##
## LEF for PtnCells ;
## created by Encounter v13.10-p003_1 on Wed Aug 21 15:55:15 2013
##

VERSION 5.6 ;

BUSBITCHARS "[]" ;
DIVIDERCHAR "/" ;

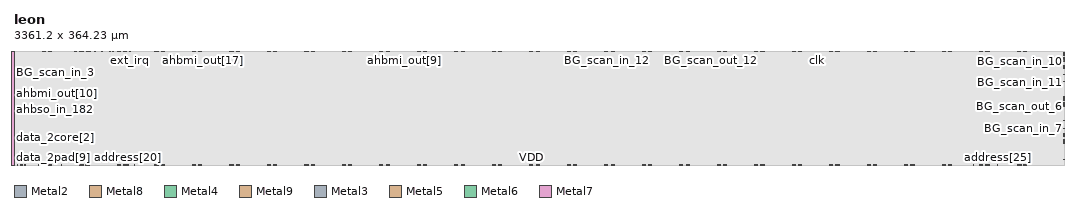
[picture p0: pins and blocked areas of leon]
MACRO leon
  CLASS BLOCK ;
  FOREIGN leon 0 0 ;
  ORIGIN 0.0000 0.0000 ;
  SIZE 3361.2000 BY 364.2300 ;
  SYMMETRY X Y R90 ;
  PIN resetn
    DIRECTION INPUT ;
    USE SIGNAL ;
    PORT
      LAYER Metal2 ;
        RECT 266.0650 363.9400 266.1350 364.2300 ;
    END
  END resetn
  PIN clk
    DIRECTION INPUT ;
    USE SIGNAL ;
    PORT
      LAYER Metal2 ;
        RECT 2571.4650 363.9400 2571.5350 364.2300 ;
    END
  END clk
  PIN clk_half
    DIRECTION INPUT ;
    USE CLOCK ;
    PORT
      LAYER Metal2 ;
        RECT 139.0650 363.9400 139.1350 364.2300 ;
    END
  END clk_half
  PIN address[27]
    DIRECTION OUTPUT ;
    USE SIGNAL ;
    PORT
      LAYER Metal2 ;
        RECT 2994.4650 0.0000 2994.5350 0.2900 ;
    END
  END address[27]
  PIN address[26]
    DIRECTION OUTPUT ;
    USE SIGNAL ;
    PORT
      LAYER Metal8 ;
        RECT 3071.6650 0.0000 3071.7350 0.2900 ;
    END
  END address[26]
  PIN address[25]
    DIRECTION OUTPUT ;
    USE SIGNAL ;
    PORT
      LAYER Metal2 ;
        RECT 3148.4650 0.0000 3148.5350 0.2900 ;
    END
  END address[25]
  PIN address[24]
    DIRECTION OUTPUT ;
    USE SIGNAL ;
    PORT
      LAYER Metal8 ;
        RECT 3225.2650 0.0000 3225.3350 0.2900 ;
    END
  END address[24]
  PIN address[23]
    DIRECTION OUTPUT ;
    USE SIGNAL ;
    PORT
      LAYER Metal2 ;
        RECT 366.0650 0.0000 366.1350 0.2900 ;
    END
  END address[23]
  PIN address[22]
    DIRECTION OUTPUT ;
    USE SIGNAL ;
    PORT
      LAYER Metal2 ;
        RECT 365.0650 0.0000 365.1350 0.2900 ;
    END
  END address[22]
  PIN address[21]
    DIRECTION OUTPUT ;
    USE SIGNAL ;
    PORT
      LAYER Metal4 ;
        RECT 365.8650 0.0000 365.9350 0.2900 ;
    END
  END address[21]
  PIN address[20]
    DIRECTION OUTPUT ;
    USE SIGNAL ;
    PORT
      LAYER Metal2 ;
        RECT 364.2650 0.0000 364.3350 0.2900 ;
    END
  END address[20]
  PIN address[19]
    DIRECTION OUTPUT ;
    USE SIGNAL ;
    PORT
      LAYER Metal9 ;
        RECT 3360.9100 19.0600 3361.2000 19.1300 ;
    END
  END address[19]
  PIN address[18]
    DIRECTION OUTPUT ;
    USE SIGNAL ;
    PORT
      LAYER Metal9 ;
        RECT 3360.9100 81.3800 3361.2000 81.4500 ;
    END
  END address[18]
  PIN address[17]
    DIRECTION OUTPUT ;
    USE SIGNAL ;
    PORT
      LAYER Metal9 ;
        RECT 3360.9100 143.7000 3361.2000 143.7700 ;
    END
  END address[17]
  PIN address[16]
    DIRECTION OUTPUT ;
    USE SIGNAL ;
    PORT
      LAYER Metal9 ;
        RECT 3360.9100 206.0200 3361.2000 206.0900 ;
    END
  END address[16]
  PIN address[15]
    DIRECTION OUTPUT ;
    USE SIGNAL ;
    PORT
      LAYER Metal9 ;
        RECT 3360.9100 268.3400 3361.2000 268.4100 ;
    END
  END address[15]
  PIN address[14]
    DIRECTION OUTPUT ;
    USE SIGNAL ;
    PORT
      LAYER Metal3 ;
        RECT 3360.9100 330.6600 3361.2000 330.7300 ;
    END
  END address[14]
  PIN address[13]
    DIRECTION OUTPUT ;
    USE SIGNAL ;
    PORT
      LAYER Metal2 ;
        RECT 338.8650 363.9400 338.9350 364.2300 ;
    END
  END address[13]
  PIN address[12]
    DIRECTION OUTPUT ;
    USE SIGNAL ;
    PORT
      LAYER Metal2 ;
        RECT 346.0650 363.9400 346.1350 364.2300 ;
    END
  END address[12]
  PIN address[11]
    DIRECTION OUTPUT ;
    USE SIGNAL ;
    PORT
      LAYER Metal2 ;
        RECT 3332.6650 363.9400 3332.7350 364.2300 ;
    END
  END address[11]
  PIN address[10]
    DIRECTION OUTPUT ;
    USE SIGNAL ;
    PORT
      LAYER Metal4 ;
        RECT 345.8650 363.9400 345.9350 364.2300 ;
    END
  END address[10]
  PIN address[9]
    DIRECTION OUTPUT ;
    USE SIGNAL ;
    PORT
      LAYER Metal2 ;
        RECT 348.0650 363.9400 348.1350 364.2300 ;
    END
  END address[9]
  PIN address[8]
    DIRECTION OUTPUT ;
    USE SIGNAL ;
    PORT
      LAYER Metal9 ;
        RECT 3360.9100 351.5600 3361.2000 351.6300 ;
    END
  END address[8]
  PIN address[7]
    DIRECTION OUTPUT ;
    USE SIGNAL ;
    PORT
      LAYER Metal3 ;
        RECT 3360.9100 351.9400 3361.2000 352.0100 ;
    END
  END address[7]
  PIN address[6]
    DIRECTION OUTPUT ;
    USE SIGNAL ;
    PORT
      LAYER Metal9 ;
        RECT 3360.9100 353.8400 3361.2000 353.9100 ;
    END
  END address[6]
  PIN address[5]
    DIRECTION OUTPUT ;
    USE SIGNAL ;
    PORT
      LAYER Metal2 ;
        RECT 341.0650 363.9400 341.1350 364.2300 ;
    END
  END address[5]
  PIN address[4]
    DIRECTION OUTPUT ;
    USE SIGNAL ;
    PORT
      LAYER Metal4 ;
        RECT 343.0650 363.9400 343.1350 364.2300 ;
    END
  END address[4]
  PIN address[3]
    DIRECTION OUTPUT ;
    USE SIGNAL ;
    PORT
      LAYER Metal9 ;
        RECT 3360.9100 357.2600 3361.2000 357.3300 ;
    END
  END address[3]
  PIN address[2]
    DIRECTION OUTPUT ;
    USE SIGNAL ;
    PORT
      LAYER Metal3 ;
        RECT 3360.9100 353.4600 3361.2000 353.5300 ;
    END
  END address[2]
  PIN address[1]
    DIRECTION OUTPUT ;
    USE SIGNAL ;
    PORT
      LAYER Metal2 ;
        RECT 328.0650 363.9400 328.1350 364.2300 ;
    END
  END address[1]
  PIN address[0]
    DIRECTION OUTPUT ;
    USE SIGNAL ;
    PORT
      LAYER Metal2 ;
        RECT 327.0650 363.9400 327.1350 364.2300 ;
    END
  END address[0]
  PIN data_2core[31]
    DIRECTION INPUT ;
    USE SIGNAL ;
    PORT
      LAYER Metal9 ;
        RECT 0.0000 261.8800 0.2900 261.9500 ;
    END
  END data_2core[31]
  PIN data_2core[30]
    DIRECTION INPUT ;
    USE SIGNAL ;
    PORT
      LAYER Metal3 ;
        RECT 0.0000 239.8400 0.2900 239.9100 ;
    END
  END data_2core[30]
  PIN data_2core[29]
    DIRECTION INPUT ;
    USE SIGNAL ;
    PORT
      LAYER Metal3 ;
        RECT 0.0000 224.6400 0.2900 224.7100 ;
    END
  END data_2core[29]
  PIN data_2core[28]
    DIRECTION INPUT ;
    USE SIGNAL ;
    PORT
      LAYER Metal3 ;
        RECT 0.0000 223.3100 0.2900 223.3800 ;
    END
  END data_2core[28]
  PIN data_2core[27]
    DIRECTION INPUT ;
    USE SIGNAL ;
    PORT
      LAYER Metal9 ;
        RECT 0.0000 221.2200 0.2900 221.2900 ;
    END
  END data_2core[27]
  PIN data_2core[26]
    DIRECTION INPUT ;
    USE SIGNAL ;
    PORT
      LAYER Metal3 ;
        RECT 0.0000 221.0300 0.2900 221.1000 ;
    END
  END data_2core[26]
  PIN data_2core[25]
    DIRECTION INPUT ;
    USE SIGNAL ;
    PORT
      LAYER Metal3 ;
        RECT 0.0000 238.1300 0.2900 238.2000 ;
    END
  END data_2core[25]
  PIN data_2core[24]
    DIRECTION INPUT ;
    USE SIGNAL ;
    PORT
      LAYER Metal9 ;
        RECT 0.0000 242.8800 0.2900 242.9500 ;
    END
  END data_2core[24]
  PIN data_2core[23]
    DIRECTION INPUT ;
    USE SIGNAL ;
    PORT
      LAYER Metal9 ;
        RECT 0.0000 241.7400 0.2900 241.8100 ;
    END
  END data_2core[23]
  PIN data_2core[22]
    DIRECTION INPUT ;
    USE SIGNAL ;
    PORT
      LAYER Metal3 ;
        RECT 0.0000 242.1200 0.2900 242.1900 ;
    END
  END data_2core[22]
  PIN data_2core[21]
    DIRECTION INPUT ;
    USE SIGNAL ;
    PORT
      LAYER Metal3 ;
        RECT 0.0000 244.9700 0.2900 245.0400 ;
    END
  END data_2core[21]
  PIN data_2core[20]
    DIRECTION INPUT ;
    USE SIGNAL ;
    PORT
      LAYER Metal9 ;
        RECT 0.0000 252.0000 0.2900 252.0700 ;
    END
  END data_2core[20]
  PIN data_2core[19]
    DIRECTION INPUT ;
    USE SIGNAL ;
    PORT
      LAYER Metal3 ;
        RECT 0.0000 255.2300 0.2900 255.3000 ;
    END
  END data_2core[19]
  PIN data_2core[18]
    DIRECTION INPUT ;
    USE SIGNAL ;
    PORT
      LAYER Metal9 ;
        RECT 0.0000 250.8600 0.2900 250.9300 ;
    END
  END data_2core[18]
  PIN data_2core[17]
    DIRECTION INPUT ;
    USE SIGNAL ;
    PORT
      LAYER Metal3 ;
        RECT 0.0000 241.7400 0.2900 241.8100 ;
    END
  END data_2core[17]
  PIN data_2core[16]
    DIRECTION INPUT ;
    USE SIGNAL ;
    PORT
      LAYER Metal5 ;
        RECT 0.0000 241.5500 0.2900 241.6200 ;
    END
  END data_2core[16]
  PIN data_2core[15]
    DIRECTION INPUT ;
    USE SIGNAL ;
    PORT
      LAYER Metal2 ;
        RECT 27.2650 0.0000 27.3350 0.2900 ;
    END
  END data_2core[15]
  PIN data_2core[14]
    DIRECTION INPUT ;
    USE SIGNAL ;
    PORT
      LAYER Metal9 ;
        RECT 0.0000 224.6400 0.2900 224.7100 ;
    END
  END data_2core[14]
  PIN data_2core[13]
    DIRECTION INPUT ;
    USE SIGNAL ;
    PORT
      LAYER Metal9 ;
        RECT 0.0000 223.1200 0.2900 223.1900 ;
    END
  END data_2core[13]
  PIN data_2core[12]
    DIRECTION INPUT ;
    USE SIGNAL ;
    PORT
      LAYER Metal2 ;
        RECT 21.2650 0.0000 21.3350 0.2900 ;
    END
  END data_2core[12]
  PIN data_2core[11]
    DIRECTION INPUT ;
    USE SIGNAL ;
    PORT
      LAYER Metal9 ;
        RECT 0.0000 234.9000 0.2900 234.9700 ;
    END
  END data_2core[11]
  PIN data_2core[10]
    DIRECTION INPUT ;
    USE SIGNAL ;
    PORT
      LAYER Metal9 ;
        RECT 0.0000 237.1800 0.2900 237.2500 ;
    END
  END data_2core[10]
  PIN data_2core[9]
    DIRECTION INPUT ;
    USE SIGNAL ;
    PORT
      LAYER Metal2 ;
        RECT 36.2650 0.0000 36.3350 0.2900 ;
    END
  END data_2core[9]
  PIN data_2core[8]
    DIRECTION INPUT ;
    USE SIGNAL ;
    PORT
      LAYER Metal9 ;
        RECT 0.0000 255.4200 0.2900 255.4900 ;
    END
  END data_2core[8]
  PIN data_2core[7]
    DIRECTION INPUT ;
    USE SIGNAL ;
    PORT
      LAYER Metal9 ;
        RECT 0.0000 304.8200 0.2900 304.8900 ;
    END
  END data_2core[7]
  PIN data_2core[6]
    DIRECTION INPUT ;
    USE SIGNAL ;
    PORT
      LAYER Metal9 ;
        RECT 0.0000 307.8600 0.2900 307.9300 ;
    END
  END data_2core[6]
  PIN data_2core[5]
    DIRECTION INPUT ;
    USE SIGNAL ;
    PORT
      LAYER Metal2 ;
        RECT 49.4650 363.9400 49.5350 364.2300 ;
    END
  END data_2core[5]
  PIN data_2core[4]
    DIRECTION INPUT ;
    USE SIGNAL ;
    PORT
      LAYER Metal3 ;
        RECT 0.0000 315.8400 0.2900 315.9100 ;
    END
  END data_2core[4]
  PIN data_2core[3]
    DIRECTION INPUT ;
    USE SIGNAL ;
    PORT
      LAYER Metal9 ;
        RECT 0.0000 306.3400 0.2900 306.4100 ;
    END
  END data_2core[3]
  PIN data_2core[2]
    DIRECTION INPUT ;
    USE SIGNAL ;
    PORT
      LAYER Metal9 ;
        RECT 0.0000 86.7000 0.2900 86.7700 ;
    END
  END data_2core[2]
  PIN data_2core[1]
    DIRECTION INPUT ;
    USE SIGNAL ;
    PORT
      LAYER Metal9 ;
        RECT 0.0000 55.9200 0.2900 55.9900 ;
    END
  END data_2core[1]
  PIN data_2core[0]
    DIRECTION INPUT ;
    USE SIGNAL ;
    PORT
      LAYER Metal9 ;
        RECT 0.0000 39.9600 0.2900 40.0300 ;
    END
  END data_2core[0]
  PIN data_2pad[31]
    DIRECTION OUTPUT ;
    USE SIGNAL ;
    PORT
      LAYER Metal9 ;
        RECT 0.0000 257.3200 0.2900 257.3900 ;
    END
  END data_2pad[31]
  PIN data_2pad[30]
    DIRECTION OUTPUT ;
    USE SIGNAL ;
    PORT
      LAYER Metal3 ;
        RECT 0.0000 237.1800 0.2900 237.2500 ;
    END
  END data_2pad[30]
  PIN data_2pad[29]
    DIRECTION OUTPUT ;
    USE SIGNAL ;
    PORT
      LAYER Metal5 ;
        RECT 0.0000 228.4400 0.2900 228.5100 ;
    END
  END data_2pad[29]
  PIN data_2pad[28]
    DIRECTION OUTPUT ;
    USE SIGNAL ;
    PORT
      LAYER Metal3 ;
        RECT 0.0000 231.2900 0.2900 231.3600 ;
    END
  END data_2pad[28]
  PIN data_2pad[27]
    DIRECTION OUTPUT ;
    USE SIGNAL ;
    PORT
      LAYER Metal5 ;
        RECT 0.0000 225.9700 0.2900 226.0400 ;
    END
  END data_2pad[27]
  PIN data_2pad[26]
    DIRECTION OUTPUT ;
    USE SIGNAL ;
    PORT
      LAYER Metal9 ;
        RECT 0.0000 228.4400 0.2900 228.5100 ;
    END
  END data_2pad[26]
  PIN data_2pad[25]
    DIRECTION OUTPUT ;
    USE SIGNAL ;
    PORT
      LAYER Metal5 ;
        RECT 0.0000 231.1000 0.2900 231.1700 ;
    END
  END data_2pad[25]
  PIN data_2pad[24]
    DIRECTION OUTPUT ;
    USE SIGNAL ;
    PORT
      LAYER Metal9 ;
        RECT 0.0000 233.3800 0.2900 233.4500 ;
    END
  END data_2pad[24]
  PIN data_2pad[23]
    DIRECTION OUTPUT ;
    USE SIGNAL ;
    PORT
      LAYER Metal9 ;
        RECT 0.0000 231.1000 0.2900 231.1700 ;
    END
  END data_2pad[23]
  PIN data_2pad[22]
    DIRECTION OUTPUT ;
    USE SIGNAL ;
    PORT
      LAYER Metal5 ;
        RECT 0.0000 230.7200 0.2900 230.7900 ;
    END
  END data_2pad[22]
  PIN data_2pad[21]
    DIRECTION OUTPUT ;
    USE SIGNAL ;
    PORT
      LAYER Metal9 ;
        RECT 0.0000 229.2000 0.2900 229.2700 ;
    END
  END data_2pad[21]
  PIN data_2pad[20]
    DIRECTION OUTPUT ;
    USE SIGNAL ;
    PORT
      LAYER Metal5 ;
        RECT 0.0000 226.3500 0.2900 226.4200 ;
    END
  END data_2pad[20]
  PIN data_2pad[19]
    DIRECTION OUTPUT ;
    USE SIGNAL ;
    PORT
      LAYER Metal5 ;
        RECT 0.0000 226.9200 0.2900 226.9900 ;
    END
  END data_2pad[19]
  PIN data_2pad[18]
    DIRECTION OUTPUT ;
    USE SIGNAL ;
    PORT
      LAYER Metal5 ;
        RECT 0.0000 231.6700 0.2900 231.7400 ;
    END
  END data_2pad[18]
  PIN data_2pad[17]
    DIRECTION OUTPUT ;
    USE SIGNAL ;
    PORT
      LAYER Metal9 ;
        RECT 0.0000 226.1600 0.2900 226.2300 ;
    END
  END data_2pad[17]
  PIN data_2pad[16]
    DIRECTION OUTPUT ;
    USE SIGNAL ;
    PORT
      LAYER Metal9 ;
        RECT 0.0000 227.6800 0.2900 227.7500 ;
    END
  END data_2pad[16]
  PIN data_2pad[15]
    DIRECTION OUTPUT ;
    USE SIGNAL ;
    PORT
      LAYER Metal2 ;
        RECT 23.2650 0.0000 23.3350 0.2900 ;
    END
  END data_2pad[15]
  PIN data_2pad[14]
    DIRECTION OUTPUT ;
    USE SIGNAL ;
    PORT
      LAYER Metal5 ;
        RECT 0.0000 230.3400 0.2900 230.4100 ;
    END
  END data_2pad[14]
  PIN data_2pad[13]
    DIRECTION OUTPUT ;
    USE SIGNAL ;
    PORT
      LAYER Metal9 ;
        RECT 0.0000 226.9200 0.2900 226.9900 ;
    END
  END data_2pad[13]
  PIN data_2pad[12]
    DIRECTION OUTPUT ;
    USE SIGNAL ;
    PORT
      LAYER Metal5 ;
        RECT 0.0000 227.3000 0.2900 227.3700 ;
    END
  END data_2pad[12]
  PIN data_2pad[11]
    DIRECTION OUTPUT ;
    USE SIGNAL ;
    PORT
      LAYER Metal9 ;
        RECT 0.0000 231.8600 0.2900 231.9300 ;
    END
  END data_2pad[11]
  PIN data_2pad[10]
    DIRECTION OUTPUT ;
    USE SIGNAL ;
    PORT
      LAYER Metal3 ;
        RECT 0.0000 240.6000 0.2900 240.6700 ;
    END
  END data_2pad[10]
  PIN data_2pad[9]
    DIRECTION OUTPUT ;
    USE SIGNAL ;
    PORT
      LAYER Metal2 ;
        RECT 34.2650 0.0000 34.3350 0.2900 ;
    END
  END data_2pad[9]
  PIN data_2pad[8]
    DIRECTION OUTPUT ;
    USE SIGNAL ;
    PORT
      LAYER Metal9 ;
        RECT 0.0000 245.5400 0.2900 245.6100 ;
    END
  END data_2pad[8]
  PIN data_2pad[7]
    DIRECTION OUTPUT ;
    USE SIGNAL ;
    PORT
      LAYER Metal9 ;
        RECT 0.0000 298.7400 0.2900 298.8100 ;
    END
  END data_2pad[7]
  PIN data_2pad[6]
    DIRECTION OUTPUT ;
    USE SIGNAL ;
    PORT
      LAYER Metal9 ;
        RECT 0.0000 302.1600 0.2900 302.2300 ;
    END
  END data_2pad[6]
  PIN data_2pad[5]
    DIRECTION OUTPUT ;
    USE SIGNAL ;
    PORT
      LAYER Metal9 ;
        RECT 0.0000 303.3000 0.2900 303.3700 ;
    END
  END data_2pad[5]
  PIN data_2pad[4]
    DIRECTION OUTPUT ;
    USE SIGNAL ;
    PORT
      LAYER Metal3 ;
        RECT 0.0000 306.7200 0.2900 306.7900 ;
    END
  END data_2pad[4]
  PIN data_2pad[3]
    DIRECTION OUTPUT ;
    USE SIGNAL ;
    PORT
      LAYER Metal4 ;
        RECT 26.4650 363.9400 26.5350 364.2300 ;
    END
  END data_2pad[3]
  PIN data_2pad[2]
    DIRECTION OUTPUT ;
    USE SIGNAL ;
    PORT
      LAYER Metal9 ;
        RECT 0.0000 282.7800 0.2900 282.8500 ;
    END
  END data_2pad[2]
  PIN data_2pad[1]
    DIRECTION OUTPUT ;
    USE SIGNAL ;
    PORT
      LAYER Metal3 ;
        RECT 0.0000 277.4600 0.2900 277.5300 ;
    END
  END data_2pad[1]
  PIN data_2pad[0]
    DIRECTION OUTPUT ;
    USE SIGNAL ;
    PORT
      LAYER Metal9 ;
        RECT 0.0000 274.4200 0.2900 274.4900 ;
    END
  END data_2pad[0]
  PIN data_en_n[3]
    DIRECTION OUTPUT ;
    USE SIGNAL ;
    PORT
      LAYER Metal2 ;
        RECT 10.8650 0.0000 10.9350 0.2900 ;
    END
  END data_en_n[3]
  PIN data_en_n[2]
    DIRECTION OUTPUT ;
    USE SIGNAL ;
    PORT
      LAYER Metal9 ;
        RECT 0.0000 35.7800 0.2900 35.8500 ;
    END
  END data_en_n[2]
  PIN data_en_n[1]
    DIRECTION OUTPUT ;
    USE SIGNAL ;
    PORT
      LAYER Metal9 ;
        RECT 0.0000 36.5400 0.2900 36.6100 ;
    END
  END data_en_n[1]
  PIN data_en_n[0]
    DIRECTION OUTPUT ;
    USE SIGNAL ;
    PORT
      LAYER Metal5 ;
        RECT 0.0000 330.8500 0.2900 330.9200 ;
    END
  END data_en_n[0]
  PIN ramsn_3
    DIRECTION OUTPUT ;
    USE SIGNAL ;
    PORT
      LAYER Metal2 ;
        RECT 309.0650 363.9400 309.1350 364.2300 ;
    END
  END ramsn_3
  PIN ramsn_2
    DIRECTION OUTPUT ;
    USE SIGNAL ;
    PORT
      LAYER Metal4 ;
        RECT 308.8650 363.9400 308.9350 364.2300 ;
    END
  END ramsn_2
  PIN ramsn_1
    DIRECTION OUTPUT ;
    USE SIGNAL ;
    PORT
      LAYER Metal2 ;
        RECT 309.8650 363.9400 309.9350 364.2300 ;
    END
  END ramsn_1
  PIN ramsn_0
    DIRECTION OUTPUT ;
    USE SIGNAL ;
    PORT
      LAYER Metal9 ;
        RECT 3360.9100 358.7800 3361.2000 358.8500 ;
    END
  END ramsn_0
  PIN ramoen_3
    DIRECTION OUTPUT ;
    USE SIGNAL ;
    PORT
      LAYER Metal2 ;
        RECT 317.0650 363.9400 317.1350 364.2300 ;
    END
  END ramoen_3
  PIN ramoen_2
    DIRECTION OUTPUT ;
    USE SIGNAL ;
    PORT
      LAYER Metal3 ;
        RECT 3360.9100 356.8800 3361.2000 356.9500 ;
    END
  END ramoen_2
  PIN ramoen_1
    DIRECTION OUTPUT ;
    USE SIGNAL ;
    PORT
      LAYER Metal4 ;
        RECT 316.8650 363.9400 316.9350 364.2300 ;
    END
  END ramoen_1
  PIN ramoen_0
    DIRECTION OUTPUT ;
    USE SIGNAL ;
    PORT
      LAYER Metal2 ;
        RECT 303.0650 363.9400 303.1350 364.2300 ;
    END
  END ramoen_0
  PIN rwen_2pad[3]
    DIRECTION OUTPUT ;
    USE SIGNAL ;
    PORT
      LAYER Metal2 ;
        RECT 267.0650 363.9400 267.1350 364.2300 ;
    END
  END rwen_2pad[3]
  PIN rwen_2pad[2]
    DIRECTION OUTPUT ;
    USE SIGNAL ;
    PORT
      LAYER Metal2 ;
        RECT 274.0650 363.9400 274.1350 364.2300 ;
    END
  END rwen_2pad[2]
  PIN rwen_2pad[1]
    DIRECTION OUTPUT ;
    USE SIGNAL ;
    PORT
      LAYER Metal9 ;
        RECT 3360.9100 353.0800 3361.2000 353.1500 ;
    END
  END rwen_2pad[1]
  PIN rwen_2pad[0]
    DIRECTION OUTPUT ;
    USE SIGNAL ;
    PORT
      LAYER Metal2 ;
        RECT 273.0650 363.9400 273.1350 364.2300 ;
    END
  END rwen_2pad[0]
  PIN romsn[1]
    DIRECTION OUTPUT ;
    USE SIGNAL ;
    PORT
      LAYER Metal2 ;
        RECT 301.0650 363.9400 301.1350 364.2300 ;
    END
  END romsn[1]
  PIN romsn[0]
    DIRECTION OUTPUT ;
    USE SIGNAL ;
    PORT
      LAYER Metal2 ;
        RECT 2506.2650 363.9400 2506.3350 364.2300 ;
    END
  END romsn[0]
  PIN iosn
    DIRECTION OUTPUT ;
    USE SIGNAL ;
    PORT
      LAYER Metal4 ;
        RECT 290.0650 363.9400 290.1350 364.2300 ;
    END
  END iosn
  PIN oen
    DIRECTION OUTPUT ;
    USE SIGNAL ;
    PORT
      LAYER Metal2 ;
        RECT 295.0650 363.9400 295.1350 364.2300 ;
    END
  END oen
  PIN read
    DIRECTION OUTPUT ;
    USE SIGNAL ;
    PORT
      LAYER Metal9 ;
        RECT 3360.9100 344.7200 3361.2000 344.7900 ;
    END
  END read
  PIN writen_2pad
    DIRECTION OUTPUT ;
    USE SIGNAL ;
    PORT
      LAYER Metal4 ;
        RECT 307.0650 363.9400 307.1350 364.2300 ;
    END
  END writen_2pad
  PIN pio_2core_14
    DIRECTION INPUT ;
    USE SIGNAL ;
    PORT
      LAYER Metal2 ;
        RECT 78.0650 0.0000 78.1350 0.2900 ;
    END
  END pio_2core_14
  PIN pio_2core_12
    DIRECTION INPUT ;
    USE SIGNAL ;
    PORT
      LAYER Metal2 ;
        RECT 385.4650 0.0000 385.5350 0.2900 ;
    END
  END pio_2core_12
  PIN pio_2core_0
    DIRECTION INPUT ;
    USE SIGNAL ;
    PORT
      LAYER Metal3 ;
        RECT 0.0000 255.9900 0.2900 256.0600 ;
    END
  END pio_2core_0
  PIN pio_2pad_15
    DIRECTION OUTPUT ;
    USE SIGNAL ;
    PORT
      LAYER Metal2 ;
        RECT 151.2650 0.0000 151.3350 0.2900 ;
    END
  END pio_2pad_15
  PIN pio_2pad_13
    DIRECTION OUTPUT ;
    USE SIGNAL ;
    PORT
      LAYER Metal2 ;
        RECT 228.2650 0.0000 228.3350 0.2900 ;
    END
  END pio_2pad_13
  PIN pio_2pad_5
    DIRECTION OUTPUT ;
    USE SIGNAL ;
    PORT
      LAYER Metal5 ;
        RECT 0.0000 286.7700 0.2900 286.8400 ;
    END
  END pio_2pad_5
  PIN pio_2pad_4
    DIRECTION OUTPUT ;
    USE SIGNAL ;
    PORT
      LAYER Metal3 ;
        RECT 0.0000 286.9600 0.2900 287.0300 ;
    END
  END pio_2pad_4
  PIN pio_2pad_1
    DIRECTION OUTPUT ;
    USE SIGNAL ;
    PORT
      LAYER Metal3 ;
        RECT 0.0000 288.1000 0.2900 288.1700 ;
    END
  END pio_2pad_1
  PIN ahbmi_out[35]
    DIRECTION OUTPUT ;
    USE SIGNAL ;
    PORT
      LAYER Metal5 ;
        RECT 0.0000 343.2000 0.2900 343.2700 ;
    END
  END ahbmi_out[35]
  PIN ahbmi_out[34]
    DIRECTION OUTPUT ;
    USE SIGNAL ;
    PORT
      LAYER Metal3 ;
        RECT 0.0000 340.5400 0.2900 340.6100 ;
    END
  END ahbmi_out[34]
  PIN ahbmi_out[33]
    DIRECTION OUTPUT ;
    USE SIGNAL ;
    PORT
      LAYER Metal5 ;
        RECT 0.0000 319.8300 0.2900 319.9000 ;
    END
  END ahbmi_out[33]
  PIN ahbmi_out[32]
    DIRECTION OUTPUT ;
    USE SIGNAL ;
    PORT
      LAYER Metal3 ;
        RECT 0.0000 283.5400 0.2900 283.6100 ;
    END
  END ahbmi_out[32]
  PIN ahbmi_out[31]
    DIRECTION OUTPUT ;
    USE SIGNAL ;
    PORT
      LAYER Metal5 ;
        RECT 0.0000 338.4500 0.2900 338.5200 ;
    END
  END ahbmi_out[31]
  PIN ahbmi_out[30]
    DIRECTION OUTPUT ;
    USE SIGNAL ;
    PORT
      LAYER Metal3 ;
        RECT 0.0000 278.2200 0.2900 278.2900 ;
    END
  END ahbmi_out[30]
  PIN ahbmi_out[29]
    DIRECTION OUTPUT ;
    USE SIGNAL ;
    PORT
      LAYER Metal3 ;
        RECT 0.0000 277.8400 0.2900 277.9100 ;
    END
  END ahbmi_out[29]
  PIN ahbmi_out[28]
    DIRECTION OUTPUT ;
    USE SIGNAL ;
    PORT
      LAYER Metal2 ;
        RECT 293.2650 363.9400 293.3350 364.2300 ;
    END
  END ahbmi_out[28]
  PIN ahbmi_out[27]
    DIRECTION OUTPUT ;
    USE SIGNAL ;
    PORT
      LAYER Metal3 ;
        RECT 0.0000 226.5400 0.2900 226.6100 ;
    END
  END ahbmi_out[27]
  PIN ahbmi_out[26]
    DIRECTION OUTPUT ;
    USE SIGNAL ;
    PORT
      LAYER Metal3 ;
        RECT 0.0000 226.1600 0.2900 226.2300 ;
    END
  END ahbmi_out[26]
  PIN ahbmi_out[25]
    DIRECTION OUTPUT ;
    USE SIGNAL ;
    PORT
      LAYER Metal3 ;
        RECT 0.0000 227.6800 0.2900 227.7500 ;
    END
  END ahbmi_out[25]
  PIN ahbmi_out[24]
    DIRECTION OUTPUT ;
    USE SIGNAL ;
    PORT
      LAYER Metal3 ;
        RECT 0.0000 228.0600 0.2900 228.1300 ;
    END
  END ahbmi_out[24]
  PIN ahbmi_out[23]
    DIRECTION OUTPUT ;
    USE SIGNAL ;
    PORT
      LAYER Metal3 ;
        RECT 0.0000 229.2000 0.2900 229.2700 ;
    END
  END ahbmi_out[23]
  PIN ahbmi_out[22]
    DIRECTION OUTPUT ;
    USE SIGNAL ;
    PORT
      LAYER Metal3 ;
        RECT 0.0000 229.5800 0.2900 229.6500 ;
    END
  END ahbmi_out[22]
  PIN ahbmi_out[21]
    DIRECTION OUTPUT ;
    USE SIGNAL ;
    PORT
      LAYER Metal2 ;
        RECT 620.0650 363.9400 620.1350 364.2300 ;
    END
  END ahbmi_out[21]
  PIN ahbmi_out[20]
    DIRECTION OUTPUT ;
    USE SIGNAL ;
    PORT
      LAYER Metal2 ;
        RECT 624.0650 363.9400 624.1350 364.2300 ;
    END
  END ahbmi_out[20]
  PIN ahbmi_out[19]
    DIRECTION OUTPUT ;
    USE SIGNAL ;
    PORT
      LAYER Metal2 ;
        RECT 627.6650 363.9400 627.7350 364.2300 ;
    END
  END ahbmi_out[19]
  PIN ahbmi_out[18]
    DIRECTION OUTPUT ;
    USE SIGNAL ;
    PORT
      LAYER Metal2 ;
        RECT 837.4650 363.9400 837.5350 364.2300 ;
    END
  END ahbmi_out[18]
  PIN ahbmi_out[17]
    DIRECTION OUTPUT ;
    USE SIGNAL ;
    PORT
      LAYER Metal2 ;
        RECT 604.8650 363.9400 604.9350 364.2300 ;
    END
  END ahbmi_out[17]
  PIN ahbmi_out[16]
    DIRECTION OUTPUT ;
    USE SIGNAL ;
    PORT
      LAYER Metal3 ;
        RECT 0.0000 230.3400 0.2900 230.4100 ;
    END
  END ahbmi_out[16]
  PIN ahbmi_out[15]
    DIRECTION OUTPUT ;
    USE SIGNAL ;
    PORT
      LAYER Metal3 ;
        RECT 0.0000 230.7200 0.2900 230.7900 ;
    END
  END ahbmi_out[15]
  PIN ahbmi_out[14]
    DIRECTION OUTPUT ;
    USE SIGNAL ;
    PORT
      LAYER Metal2 ;
        RECT 485.0650 363.9400 485.1350 364.2300 ;
    END
  END ahbmi_out[14]
  PIN ahbmi_out[13]
    DIRECTION OUTPUT ;
    USE SIGNAL ;
    PORT
      LAYER Metal2 ;
        RECT 488.2650 363.9400 488.3350 364.2300 ;
    END
  END ahbmi_out[13]
  PIN ahbmi_out[12]
    DIRECTION OUTPUT ;
    USE SIGNAL ;
    PORT
      LAYER Metal3 ;
        RECT 0.0000 228.8200 0.2900 228.8900 ;
    END
  END ahbmi_out[12]
  PIN ahbmi_out[11]
    DIRECTION OUTPUT ;
    USE SIGNAL ;
    PORT
      LAYER Metal2 ;
        RECT 506.0650 363.9400 506.1350 364.2300 ;
    END
  END ahbmi_out[11]
  PIN ahbmi_out[10]
    DIRECTION OUTPUT ;
    USE SIGNAL ;
    PORT
      LAYER Metal3 ;
        RECT 0.0000 229.9600 0.2900 230.0300 ;
    END
  END ahbmi_out[10]
  PIN ahbmi_out[9]
    DIRECTION OUTPUT ;
    USE SIGNAL ;
    PORT
      LAYER Metal2 ;
        RECT 1250.0650 363.9400 1250.1350 364.2300 ;
    END
  END ahbmi_out[9]
  PIN ahbmi_out[8]
    DIRECTION OUTPUT ;
    USE SIGNAL ;
    PORT
      LAYER Metal2 ;
        RECT 821.8650 363.9400 821.9350 364.2300 ;
    END
  END ahbmi_out[8]
  PIN ahbmi_out[7]
    DIRECTION OUTPUT ;
    USE SIGNAL ;
    PORT
      LAYER Metal5 ;
        RECT 0.0000 228.8200 0.2900 228.8900 ;
    END
  END ahbmi_out[7]
  PIN ahbmi_out[6]
    DIRECTION OUTPUT ;
    USE SIGNAL ;
    PORT
      LAYER Metal5 ;
        RECT 0.0000 228.0600 0.2900 228.1300 ;
    END
  END ahbmi_out[6]
  PIN ahbmi_out[5]
    DIRECTION OUTPUT ;
    USE SIGNAL ;
    PORT
      LAYER Metal5 ;
        RECT 0.0000 227.6800 0.2900 227.7500 ;
    END
  END ahbmi_out[5]
  PIN ahbmi_out[4]
    DIRECTION OUTPUT ;
    USE SIGNAL ;
    PORT
      LAYER Metal3 ;
        RECT 0.0000 228.4400 0.2900 228.5100 ;
    END
  END ahbmi_out[4]
  PIN ahbmi_out[3]
    DIRECTION OUTPUT ;
    USE SIGNAL ;
    PORT
      LAYER Metal3 ;
        RECT 0.0000 226.9200 0.2900 226.9900 ;
    END
  END ahbmi_out[3]
  PIN ahbmi_out[2]
    DIRECTION OUTPUT ;
    USE SIGNAL ;
    PORT
      LAYER Metal3 ;
        RECT 0.0000 227.3000 0.2900 227.3700 ;
    END
  END ahbmi_out[2]
  PIN ahbmi_out[1]
    DIRECTION OUTPUT ;
    USE SIGNAL ;
    PORT
      LAYER Metal3 ;
        RECT 0.0000 224.2600 0.2900 224.3300 ;
    END
  END ahbmi_out[1]
  PIN ahbmi_out[0]
    DIRECTION OUTPUT ;
    USE SIGNAL ;
    PORT
      LAYER Metal4 ;
        RECT 292.0650 363.9400 292.1350 364.2300 ;
    END
  END ahbmi_out[0]
  PIN ahbmo_in_78
    DIRECTION INPUT ;
    USE SIGNAL ;
    PORT
      LAYER Metal3 ;
        RECT 0.0000 297.2200 0.2900 297.2900 ;
    END
  END ahbmo_in_78
  PIN ahbmo_in_77
    DIRECTION INPUT ;
    USE SIGNAL ;
    PORT
      LAYER Metal2 ;
        RECT 247.4650 363.9400 247.5350 364.2300 ;
    END
  END ahbmo_in_77
  PIN ahbmo_in_76
    DIRECTION INPUT ;
    USE SIGNAL ;
    PORT
      LAYER Metal3 ;
        RECT 0.0000 297.6000 0.2900 297.6700 ;
    END
  END ahbmo_in_76
  PIN ahbmo_in_75
    DIRECTION INPUT ;
    USE SIGNAL ;
    PORT
      LAYER Metal2 ;
        RECT 245.2650 363.9400 245.3350 364.2300 ;
    END
  END ahbmo_in_75
  PIN ahbmo_in_74
    DIRECTION INPUT ;
    USE SIGNAL ;
    PORT
      LAYER Metal5 ;
        RECT 0.0000 298.7400 0.2900 298.8100 ;
    END
  END ahbmo_in_74
  PIN ahbmo_in_73
    DIRECTION INPUT ;
    USE SIGNAL ;
    PORT
      LAYER Metal2 ;
        RECT 246.2650 363.9400 246.3350 364.2300 ;
    END
  END ahbmo_in_73
  PIN ahbmo_in_72
    DIRECTION INPUT ;
    USE SIGNAL ;
    PORT
      LAYER Metal3 ;
        RECT 0.0000 298.7400 0.2900 298.8100 ;
    END
  END ahbmo_in_72
  PIN ahbmo_in_71
    DIRECTION INPUT ;
    USE SIGNAL ;
    PORT
      LAYER Metal5 ;
        RECT 0.0000 299.1200 0.2900 299.1900 ;
    END
  END ahbmo_in_71
  PIN ahbmo_in_70
    DIRECTION INPUT ;
    USE SIGNAL ;
    PORT
      LAYER Metal3 ;
        RECT 0.0000 299.1200 0.2900 299.1900 ;
    END
  END ahbmo_in_70
  PIN ahbmo_in_69
    DIRECTION INPUT ;
    USE SIGNAL ;
    PORT
      LAYER Metal5 ;
        RECT 0.0000 299.5000 0.2900 299.5700 ;
    END
  END ahbmo_in_69
  PIN ahbmo_in_68
    DIRECTION INPUT ;
    USE SIGNAL ;
    PORT
      LAYER Metal9 ;
        RECT 0.0000 299.8800 0.2900 299.9500 ;
    END
  END ahbmo_in_68
  PIN ahbmo_in_67
    DIRECTION INPUT ;
    USE SIGNAL ;
    PORT
      LAYER Metal2 ;
        RECT 255.2650 363.9400 255.3350 364.2300 ;
    END
  END ahbmo_in_67
  PIN ahbmo_in_66
    DIRECTION INPUT ;
    USE SIGNAL ;
    PORT
      LAYER Metal5 ;
        RECT 0.0000 299.8800 0.2900 299.9500 ;
    END
  END ahbmo_in_66
  PIN ahbmo_in_65
    DIRECTION INPUT ;
    USE SIGNAL ;
    PORT
      LAYER Metal3 ;
        RECT 0.0000 299.8800 0.2900 299.9500 ;
    END
  END ahbmo_in_65
  PIN ahbmo_in_64
    DIRECTION INPUT ;
    USE SIGNAL ;
    PORT
      LAYER Metal5 ;
        RECT 0.0000 300.2600 0.2900 300.3300 ;
    END
  END ahbmo_in_64
  PIN ahbmo_in_63
    DIRECTION INPUT ;
    USE SIGNAL ;
    PORT
      LAYER Metal9 ;
        RECT 0.0000 300.6400 0.2900 300.7100 ;
    END
  END ahbmo_in_63
  PIN ahbmo_in_62
    DIRECTION INPUT ;
    USE SIGNAL ;
    PORT
      LAYER Metal5 ;
        RECT 0.0000 300.6400 0.2900 300.7100 ;
    END
  END ahbmo_in_62
  PIN ahbmo_in_61
    DIRECTION INPUT ;
    USE SIGNAL ;
    PORT
      LAYER Metal2 ;
        RECT 252.2650 363.9400 252.3350 364.2300 ;
    END
  END ahbmo_in_61
  PIN ahbmo_in_60
    DIRECTION INPUT ;
    USE SIGNAL ;
    PORT
      LAYER Metal3 ;
        RECT 0.0000 300.6400 0.2900 300.7100 ;
    END
  END ahbmo_in_60
  PIN ahbmo_in_59
    DIRECTION INPUT ;
    USE SIGNAL ;
    PORT
      LAYER Metal5 ;
        RECT 0.0000 301.0200 0.2900 301.0900 ;
    END
  END ahbmo_in_59
  PIN ahbmo_in_58
    DIRECTION INPUT ;
    USE SIGNAL ;
    PORT
      LAYER Metal2 ;
        RECT 251.2650 363.9400 251.3350 364.2300 ;
    END
  END ahbmo_in_58
  PIN ahbmo_in_57
    DIRECTION INPUT ;
    USE SIGNAL ;
    PORT
      LAYER Metal2 ;
        RECT 249.2650 363.9400 249.3350 364.2300 ;
    END
  END ahbmo_in_57
  PIN ahbmo_in_56
    DIRECTION INPUT ;
    USE SIGNAL ;
    PORT
      LAYER Metal2 ;
        RECT 244.2650 363.9400 244.3350 364.2300 ;
    END
  END ahbmo_in_56
  PIN ahbmo_in_55
    DIRECTION INPUT ;
    USE SIGNAL ;
    PORT
      LAYER Metal9 ;
        RECT 0.0000 301.4000 0.2900 301.4700 ;
    END
  END ahbmo_in_55
  PIN ahbmo_in_54
    DIRECTION INPUT ;
    USE SIGNAL ;
    PORT
      LAYER Metal5 ;
        RECT 0.0000 301.4000 0.2900 301.4700 ;
    END
  END ahbmo_in_54
  PIN ahbmo_in_53
    DIRECTION INPUT ;
    USE SIGNAL ;
    PORT
      LAYER Metal5 ;
        RECT 0.0000 301.7800 0.2900 301.8500 ;
    END
  END ahbmo_in_53
  PIN ahbmo_in_52
    DIRECTION INPUT ;
    USE SIGNAL ;
    PORT
      LAYER Metal3 ;
        RECT 0.0000 301.7800 0.2900 301.8500 ;
    END
  END ahbmo_in_52
  PIN ahbmo_in_51
    DIRECTION INPUT ;
    USE SIGNAL ;
    PORT
      LAYER Metal5 ;
        RECT 0.0000 302.1600 0.2900 302.2300 ;
    END
  END ahbmo_in_51
  PIN ahbmo_in_50
    DIRECTION INPUT ;
    USE SIGNAL ;
    PORT
      LAYER Metal3 ;
        RECT 0.0000 302.1600 0.2900 302.2300 ;
    END
  END ahbmo_in_50
  PIN ahbmo_in_49
    DIRECTION INPUT ;
    USE SIGNAL ;
    PORT
      LAYER Metal5 ;
        RECT 0.0000 302.5400 0.2900 302.6100 ;
    END
  END ahbmo_in_49
  PIN ahbmo_in_48
    DIRECTION INPUT ;
    USE SIGNAL ;
    PORT
      LAYER Metal3 ;
        RECT 0.0000 302.5400 0.2900 302.6100 ;
    END
  END ahbmo_in_48
  PIN ahbmo_in_47
    DIRECTION INPUT ;
    USE SIGNAL ;
    PORT
      LAYER Metal5 ;
        RECT 0.0000 302.9200 0.2900 302.9900 ;
    END
  END ahbmo_in_47
  PIN ahbmo_in_46
    DIRECTION INPUT ;
    USE SIGNAL ;
    PORT
      LAYER Metal3 ;
        RECT 0.0000 302.9200 0.2900 302.9900 ;
    END
  END ahbmo_in_46
  PIN ahbmo_in_45
    DIRECTION INPUT ;
    USE SIGNAL ;
    PORT
      LAYER Metal5 ;
        RECT 0.0000 303.3000 0.2900 303.3700 ;
    END
  END ahbmo_in_45
  PIN ahbmo_in_44
    DIRECTION INPUT ;
    USE SIGNAL ;
    PORT
      LAYER Metal3 ;
        RECT 0.0000 303.3000 0.2900 303.3700 ;
    END
  END ahbmo_in_44
  PIN ahbmo_in_43
    DIRECTION INPUT ;
    USE SIGNAL ;
    PORT
      LAYER Metal5 ;
        RECT 0.0000 303.6800 0.2900 303.7500 ;
    END
  END ahbmo_in_43
  PIN ahbmo_in_42
    DIRECTION INPUT ;
    USE SIGNAL ;
    PORT
      LAYER Metal5 ;
        RECT 0.0000 297.6000 0.2900 297.6700 ;
    END
  END ahbmo_in_42
  PIN ahbmo_in_41
    DIRECTION INPUT ;
    USE SIGNAL ;
    PORT
      LAYER Metal9 ;
        RECT 0.0000 297.9800 0.2900 298.0500 ;
    END
  END ahbmo_in_41
  PIN ahbmo_in_40
    DIRECTION INPUT ;
    USE SIGNAL ;
    PORT
      LAYER Metal5 ;
        RECT 0.0000 297.9800 0.2900 298.0500 ;
    END
  END ahbmo_in_40
  PIN ahbmo_in_39
    DIRECTION INPUT ;
    USE SIGNAL ;
    PORT
      LAYER Metal3 ;
        RECT 0.0000 297.9800 0.2900 298.0500 ;
    END
  END ahbmo_in_39
  PIN ahbmo_in_36
    DIRECTION INPUT ;
    USE SIGNAL ;
    PORT
      LAYER Metal5 ;
        RECT 0.0000 298.3600 0.2900 298.4300 ;
    END
  END ahbmo_in_36
  PIN ahbmo_in_35
    DIRECTION INPUT ;
    USE SIGNAL ;
    PORT
      LAYER Metal3 ;
        RECT 0.0000 298.3600 0.2900 298.4300 ;
    END
  END ahbmo_in_35
  PIN ahbmo_in_34
    DIRECTION INPUT ;
    USE SIGNAL ;
    PORT
      LAYER Metal2 ;
        RECT 78.2650 363.9400 78.3350 364.2300 ;
    END
  END ahbmo_in_34
  PIN ahbmo_in_33
    DIRECTION INPUT ;
    USE SIGNAL ;
    PORT
      LAYER Metal2 ;
        RECT 171.2650 363.9400 171.3350 364.2300 ;
    END
  END ahbmo_in_33
  PIN ahbmo_in_32
    DIRECTION INPUT ;
    USE SIGNAL ;
    PORT
      LAYER Metal2 ;
        RECT 172.2650 363.9400 172.3350 364.2300 ;
    END
  END ahbmo_in_32
  PIN ahbmo_in_31
    DIRECTION INPUT ;
    USE SIGNAL ;
    PORT
      LAYER Metal3 ;
        RECT 0.0000 303.6800 0.2900 303.7500 ;
    END
  END ahbmo_in_31
  PIN ahbmo_in_30
    DIRECTION INPUT ;
    USE SIGNAL ;
    PORT
      LAYER Metal2 ;
        RECT 191.2650 363.9400 191.3350 364.2300 ;
    END
  END ahbmo_in_30
  PIN ahbmo_in_29
    DIRECTION INPUT ;
    USE SIGNAL ;
    PORT
      LAYER Metal9 ;
        RECT 0.0000 304.0600 0.2900 304.1300 ;
    END
  END ahbmo_in_29
  PIN ahbmo_in_28
    DIRECTION INPUT ;
    USE SIGNAL ;
    PORT
      LAYER Metal2 ;
        RECT 195.2650 363.9400 195.3350 364.2300 ;
    END
  END ahbmo_in_28
  PIN ahbmo_in_27
    DIRECTION INPUT ;
    USE SIGNAL ;
    PORT
      LAYER Metal5 ;
        RECT 0.0000 304.0600 0.2900 304.1300 ;
    END
  END ahbmo_in_27
  PIN ahbmo_in_26
    DIRECTION INPUT ;
    USE SIGNAL ;
    PORT
      LAYER Metal3 ;
        RECT 0.0000 304.0600 0.2900 304.1300 ;
    END
  END ahbmo_in_26
  PIN ahbmo_in_25
    DIRECTION INPUT ;
    USE SIGNAL ;
    PORT
      LAYER Metal2 ;
        RECT 206.4650 363.9400 206.5350 364.2300 ;
    END
  END ahbmo_in_25
  PIN ahbmo_in_24
    DIRECTION INPUT ;
    USE SIGNAL ;
    PORT
      LAYER Metal5 ;
        RECT 0.0000 304.4400 0.2900 304.5100 ;
    END
  END ahbmo_in_24
  PIN ahbmo_in_23
    DIRECTION INPUT ;
    USE SIGNAL ;
    PORT
      LAYER Metal3 ;
        RECT 0.0000 304.4400 0.2900 304.5100 ;
    END
  END ahbmo_in_23
  PIN ahbmo_in_22
    DIRECTION INPUT ;
    USE SIGNAL ;
    PORT
      LAYER Metal5 ;
        RECT 0.0000 304.8200 0.2900 304.8900 ;
    END
  END ahbmo_in_22
  PIN ahbmo_in_21
    DIRECTION INPUT ;
    USE SIGNAL ;
    PORT
      LAYER Metal5 ;
        RECT 0.0000 305.2000 0.2900 305.2700 ;
    END
  END ahbmo_in_21
  PIN ahbmo_in_20
    DIRECTION INPUT ;
    USE SIGNAL ;
    PORT
      LAYER Metal9 ;
        RECT 0.0000 305.5800 0.2900 305.6500 ;
    END
  END ahbmo_in_20
  PIN ahbmo_in_19
    DIRECTION INPUT ;
    USE SIGNAL ;
    PORT
      LAYER Metal5 ;
        RECT 0.0000 305.5800 0.2900 305.6500 ;
    END
  END ahbmo_in_19
  PIN ahbmo_in_18
    DIRECTION INPUT ;
    USE SIGNAL ;
    PORT
      LAYER Metal3 ;
        RECT 0.0000 305.5800 0.2900 305.6500 ;
    END
  END ahbmo_in_18
  PIN ahbmo_in_17
    DIRECTION INPUT ;
    USE SIGNAL ;
    PORT
      LAYER Metal5 ;
        RECT 0.0000 305.9600 0.2900 306.0300 ;
    END
  END ahbmo_in_17
  PIN ahbmo_in_16
    DIRECTION INPUT ;
    USE SIGNAL ;
    PORT
      LAYER Metal3 ;
        RECT 0.0000 305.9600 0.2900 306.0300 ;
    END
  END ahbmo_in_16
  PIN ahbmo_in_15
    DIRECTION INPUT ;
    USE SIGNAL ;
    PORT
      LAYER Metal5 ;
        RECT 0.0000 306.3400 0.2900 306.4100 ;
    END
  END ahbmo_in_15
  PIN ahbmo_in_14
    DIRECTION INPUT ;
    USE SIGNAL ;
    PORT
      LAYER Metal3 ;
        RECT 0.0000 306.3400 0.2900 306.4100 ;
    END
  END ahbmo_in_14
  PIN ahbmo_in_13
    DIRECTION INPUT ;
    USE SIGNAL ;
    PORT
      LAYER Metal5 ;
        RECT 0.0000 306.7200 0.2900 306.7900 ;
    END
  END ahbmo_in_13
  PIN ahbmo_in_12
    DIRECTION INPUT ;
    USE SIGNAL ;
    PORT
      LAYER Metal9 ;
        RECT 0.0000 307.1000 0.2900 307.1700 ;
    END
  END ahbmo_in_12
  PIN ahbmo_in_11
    DIRECTION INPUT ;
    USE SIGNAL ;
    PORT
      LAYER Metal5 ;
        RECT 0.0000 307.1000 0.2900 307.1700 ;
    END
  END ahbmo_in_11
  PIN ahbmo_in_10
    DIRECTION INPUT ;
    USE SIGNAL ;
    PORT
      LAYER Metal4 ;
        RECT 205.2650 363.9400 205.3350 364.2300 ;
    END
  END ahbmo_in_10
  PIN ahbmo_in_9
    DIRECTION INPUT ;
    USE SIGNAL ;
    PORT
      LAYER Metal5 ;
        RECT 0.0000 307.4800 0.2900 307.5500 ;
    END
  END ahbmo_in_9
  PIN ahbmo_in_8
    DIRECTION INPUT ;
    USE SIGNAL ;
    PORT
      LAYER Metal3 ;
        RECT 0.0000 307.4800 0.2900 307.5500 ;
    END
  END ahbmo_in_8
  PIN ahbmo_in_7
    DIRECTION INPUT ;
    USE SIGNAL ;
    PORT
      LAYER Metal5 ;
        RECT 0.0000 307.8600 0.2900 307.9300 ;
    END
  END ahbmo_in_7
  PIN ahbmo_in_6
    DIRECTION INPUT ;
    USE SIGNAL ;
    PORT
      LAYER Metal5 ;
        RECT 0.0000 308.2400 0.2900 308.3100 ;
    END
  END ahbmo_in_6
  PIN ahbmo_in_5
    DIRECTION INPUT ;
    USE SIGNAL ;
    PORT
      LAYER Metal3 ;
        RECT 0.0000 308.4300 0.2900 308.5000 ;
    END
  END ahbmo_in_5
  PIN ahbmo_in_4
    DIRECTION INPUT ;
    USE SIGNAL ;
    PORT
      LAYER Metal5 ;
        RECT 0.0000 308.6200 0.2900 308.6900 ;
    END
  END ahbmo_in_4
  PIN ahbmo_in_3
    DIRECTION INPUT ;
    USE SIGNAL ;
    PORT
      LAYER Metal3 ;
        RECT 0.0000 308.8100 0.2900 308.8800 ;
    END
  END ahbmo_in_3
  PIN ahbmo_in_2
    DIRECTION INPUT ;
    USE SIGNAL ;
    PORT
      LAYER Metal9 ;
        RECT 0.0000 309.0000 0.2900 309.0700 ;
    END
  END ahbmo_in_2
  PIN ahbmo_in_1
    DIRECTION INPUT ;
    USE SIGNAL ;
    PORT
      LAYER Metal5 ;
        RECT 0.0000 309.0000 0.2900 309.0700 ;
    END
  END ahbmo_in_1
  PIN ahbmo_in_0
    DIRECTION INPUT ;
    USE SIGNAL ;
    PORT
      LAYER Metal3 ;
        RECT 0.0000 309.1900 0.2900 309.2600 ;
    END
  END ahbmo_in_0
  PIN ahbsi_out[587]
    DIRECTION OUTPUT ;
    USE SIGNAL ;
    PORT
      LAYER Metal3 ;
        RECT 0.0000 346.4300 0.2900 346.5000 ;
    END
  END ahbsi_out[587]
  PIN ahbsi_out[586]
    DIRECTION OUTPUT ;
    USE SIGNAL ;
    PORT
      LAYER Metal2 ;
        RECT 1680.6650 363.9400 1680.7350 364.2300 ;
    END
  END ahbsi_out[586]
  PIN ahbsi_out[585]
    DIRECTION OUTPUT ;
    USE SIGNAL ;
    PORT
      LAYER Metal4 ;
        RECT 1680.6650 363.9400 1680.7350 364.2300 ;
    END
  END ahbsi_out[585]
  PIN ahbsi_out[584]
    DIRECTION OUTPUT ;
    USE SIGNAL ;
    PORT
      LAYER Metal6 ;
        RECT 1680.6650 363.9400 1680.7350 364.2300 ;
    END
  END ahbsi_out[584]
  PIN ahbsi_out[583]
    DIRECTION OUTPUT ;
    USE SIGNAL ;
    PORT
      LAYER Metal2 ;
        RECT 1680.2650 363.9400 1680.3350 364.2300 ;
    END
  END ahbsi_out[583]
  PIN ahbsi_out[582]
    DIRECTION OUTPUT ;
    USE SIGNAL ;
    PORT
      LAYER Metal4 ;
        RECT 1680.2650 363.9400 1680.3350 364.2300 ;
    END
  END ahbsi_out[582]
  PIN ahbsi_out[581]
    DIRECTION OUTPUT ;
    USE SIGNAL ;
    PORT
      LAYER Metal6 ;
        RECT 1680.2650 363.9400 1680.3350 364.2300 ;
    END
  END ahbsi_out[581]
  PIN ahbsi_out[580]
    DIRECTION OUTPUT ;
    USE SIGNAL ;
    PORT
      LAYER Metal2 ;
        RECT 1681.0650 363.9400 1681.1350 364.2300 ;
    END
  END ahbsi_out[580]
  PIN ahbsi_out[579]
    DIRECTION OUTPUT ;
    USE SIGNAL ;
    PORT
      LAYER Metal4 ;
        RECT 1681.0650 363.9400 1681.1350 364.2300 ;
    END
  END ahbsi_out[579]
  PIN ahbsi_out[578]
    DIRECTION OUTPUT ;
    USE SIGNAL ;
    PORT
      LAYER Metal6 ;
        RECT 1681.0650 363.9400 1681.1350 364.2300 ;
    END
  END ahbsi_out[578]
  PIN ahbsi_out[577]
    DIRECTION OUTPUT ;
    USE SIGNAL ;
    PORT
      LAYER Metal2 ;
        RECT 1679.8650 363.9400 1679.9350 364.2300 ;
    END
  END ahbsi_out[577]
  PIN ahbsi_out[576]
    DIRECTION OUTPUT ;
    USE SIGNAL ;
    PORT
      LAYER Metal4 ;
        RECT 1679.8650 363.9400 1679.9350 364.2300 ;
    END
  END ahbsi_out[576]
  PIN ahbsi_out[575]
    DIRECTION OUTPUT ;
    USE SIGNAL ;
    PORT
      LAYER Metal6 ;
        RECT 1679.8650 363.9400 1679.9350 364.2300 ;
    END
  END ahbsi_out[575]
  PIN ahbsi_out[574]
    DIRECTION OUTPUT ;
    USE SIGNAL ;
    PORT
      LAYER Metal2 ;
        RECT 1681.4650 363.9400 1681.5350 364.2300 ;
    END
  END ahbsi_out[574]
  PIN ahbsi_out[573]
    DIRECTION OUTPUT ;
    USE SIGNAL ;
    PORT
      LAYER Metal4 ;
        RECT 1681.4650 363.9400 1681.5350 364.2300 ;
    END
  END ahbsi_out[573]
  PIN ahbsi_out[572]
    DIRECTION OUTPUT ;
    USE SIGNAL ;
    PORT
      LAYER Metal6 ;
        RECT 1681.4650 363.9400 1681.5350 364.2300 ;
    END
  END ahbsi_out[572]
  PIN ahbsi_out[571]
    DIRECTION OUTPUT ;
    USE SIGNAL ;
    PORT
      LAYER Metal8 ;
        RECT 1681.4650 363.9400 1681.5350 364.2300 ;
    END
  END ahbsi_out[571]
  PIN ahbsi_out[570]
    DIRECTION OUTPUT ;
    USE SIGNAL ;
    PORT
      LAYER Metal2 ;
        RECT 1679.4650 363.9400 1679.5350 364.2300 ;
    END
  END ahbsi_out[570]
  PIN ahbsi_out[569]
    DIRECTION OUTPUT ;
    USE SIGNAL ;
    PORT
      LAYER Metal4 ;
        RECT 1679.4650 363.9400 1679.5350 364.2300 ;
    END
  END ahbsi_out[569]
  PIN ahbsi_out[568]
    DIRECTION OUTPUT ;
    USE SIGNAL ;
    PORT
      LAYER Metal6 ;
        RECT 1679.4650 363.9400 1679.5350 364.2300 ;
    END
  END ahbsi_out[568]
  PIN ahbsi_out[567]
    DIRECTION OUTPUT ;
    USE SIGNAL ;
    PORT
      LAYER Metal2 ;
        RECT 1681.8650 363.9400 1681.9350 364.2300 ;
    END
  END ahbsi_out[567]
  PIN ahbsi_out[566]
    DIRECTION OUTPUT ;
    USE SIGNAL ;
    PORT
      LAYER Metal4 ;
        RECT 1681.8650 363.9400 1681.9350 364.2300 ;
    END
  END ahbsi_out[566]
  PIN ahbsi_out[565]
    DIRECTION OUTPUT ;
    USE SIGNAL ;
    PORT
      LAYER Metal6 ;
        RECT 1681.8650 363.9400 1681.9350 364.2300 ;
    END
  END ahbsi_out[565]
  PIN ahbsi_out[564]
    DIRECTION OUTPUT ;
    USE SIGNAL ;
    PORT
      LAYER Metal8 ;
        RECT 1681.8650 363.9400 1681.9350 364.2300 ;
    END
  END ahbsi_out[564]
  PIN ahbsi_out[563]
    DIRECTION OUTPUT ;
    USE SIGNAL ;
    PORT
      LAYER Metal2 ;
        RECT 1679.0650 363.9400 1679.1350 364.2300 ;
    END
  END ahbsi_out[563]
  PIN ahbsi_out[562]
    DIRECTION OUTPUT ;
    USE SIGNAL ;
    PORT
      LAYER Metal4 ;
        RECT 1679.0650 363.9400 1679.1350 364.2300 ;
    END
  END ahbsi_out[562]
  PIN ahbsi_out[561]
    DIRECTION OUTPUT ;
    USE SIGNAL ;
    PORT
      LAYER Metal3 ;
        RECT 0.0000 353.0800 0.2900 353.1500 ;
    END
  END ahbsi_out[561]
  PIN ahbsi_out[560]
    DIRECTION OUTPUT ;
    USE SIGNAL ;
    PORT
      LAYER Metal4 ;
        RECT 56.2650 363.9400 56.3350 364.2300 ;
    END
  END ahbsi_out[560]
  PIN ahbsi_out[559]
    DIRECTION OUTPUT ;
    USE SIGNAL ;
    PORT
      LAYER Metal2 ;
        RECT 56.0650 363.9400 56.1350 364.2300 ;
    END
  END ahbsi_out[559]
  PIN ahbsi_out[558]
    DIRECTION OUTPUT ;
    USE SIGNAL ;
    PORT
      LAYER Metal3 ;
        RECT 0.0000 347.7600 0.2900 347.8300 ;
    END
  END ahbsi_out[558]
  PIN ahbsi_out[557]
    DIRECTION OUTPUT ;
    USE SIGNAL ;
    PORT
      LAYER Metal3 ;
        RECT 0.0000 345.2900 0.2900 345.3600 ;
    END
  END ahbsi_out[557]
  PIN ahbsi_out[556]
    DIRECTION OUTPUT ;
    USE SIGNAL ;
    PORT
      LAYER Metal6 ;
        RECT 1679.0650 363.9400 1679.1350 364.2300 ;
    END
  END ahbsi_out[556]
  PIN ahbsi_out[555]
    DIRECTION OUTPUT ;
    USE SIGNAL ;
    PORT
      LAYER Metal2 ;
        RECT 1682.2650 363.9400 1682.3350 364.2300 ;
    END
  END ahbsi_out[555]
  PIN ahbsi_out[554]
    DIRECTION OUTPUT ;
    USE SIGNAL ;
    PORT
      LAYER Metal3 ;
        RECT 0.0000 351.9400 0.2900 352.0100 ;
    END
  END ahbsi_out[554]
  PIN ahbsi_out[553]
    DIRECTION OUTPUT ;
    USE SIGNAL ;
    PORT
      LAYER Metal2 ;
        RECT 51.4650 363.9400 51.5350 364.2300 ;
    END
  END ahbsi_out[553]
  PIN ahbsi_out[552]
    DIRECTION OUTPUT ;
    USE SIGNAL ;
    PORT
      LAYER Metal3 ;
        RECT 0.0000 338.6400 0.2900 338.7100 ;
    END
  END ahbsi_out[552]
  PIN ahbsi_out[551]
    DIRECTION OUTPUT ;
    USE SIGNAL ;
    PORT
      LAYER Metal5 ;
        RECT 0.0000 350.4200 0.2900 350.4900 ;
    END
  END ahbsi_out[551]
  PIN ahbsi_out[550]
    DIRECTION OUTPUT ;
    USE SIGNAL ;
    PORT
      LAYER Metal3 ;
        RECT 0.0000 358.9700 0.2900 359.0400 ;
    END
  END ahbsi_out[550]
  PIN ahbsi_out[549]
    DIRECTION OUTPUT ;
    USE SIGNAL ;
    PORT
      LAYER Metal2 ;
        RECT 64.2650 363.9400 64.3350 364.2300 ;
    END
  END ahbsi_out[549]
  PIN ahbsi_out[548]
    DIRECTION OUTPUT ;
    USE SIGNAL ;
    PORT
      LAYER Metal4 ;
        RECT 1682.2650 363.9400 1682.3350 364.2300 ;
    END
  END ahbsi_out[548]
  PIN ahbsi_out[547]
    DIRECTION OUTPUT ;
    USE SIGNAL ;
    PORT
      LAYER Metal6 ;
        RECT 1682.2650 363.9400 1682.3350 364.2300 ;
    END
  END ahbsi_out[547]
  PIN ahbsi_out[546]
    DIRECTION OUTPUT ;
    USE SIGNAL ;
    PORT
      LAYER Metal8 ;
        RECT 1682.2650 363.9400 1682.3350 364.2300 ;
    END
  END ahbsi_out[546]
  PIN ahbsi_out[545]
    DIRECTION OUTPUT ;
    USE SIGNAL ;
    PORT
      LAYER Metal3 ;
        RECT 0.0000 350.6100 0.2900 350.6800 ;
    END
  END ahbsi_out[545]
  PIN ahbsi_out[544]
    DIRECTION OUTPUT ;
    USE SIGNAL ;
    PORT
      LAYER Metal3 ;
        RECT 0.0000 339.0200 0.2900 339.0900 ;
    END
  END ahbsi_out[544]
  PIN ahbsi_out[543]
    DIRECTION OUTPUT ;
    USE SIGNAL ;
    PORT
      LAYER Metal5 ;
        RECT 0.0000 316.6000 0.2900 316.6700 ;
    END
  END ahbsi_out[543]
  PIN ahbsi_out[542]
    DIRECTION OUTPUT ;
    USE SIGNAL ;
    PORT
      LAYER Metal3 ;
        RECT 0.0000 316.7900 0.2900 316.8600 ;
    END
  END ahbsi_out[542]
  PIN ahbsi_out[541]
    DIRECTION OUTPUT ;
    USE SIGNAL ;
    PORT
      LAYER Metal3 ;
        RECT 0.0000 324.9600 0.2900 325.0300 ;
    END
  END ahbsi_out[541]
  PIN ahbsi_out[540]
    DIRECTION OUTPUT ;
    USE SIGNAL ;
    PORT
      LAYER Metal2 ;
        RECT 11.0650 363.9400 11.1350 364.2300 ;
    END
  END ahbsi_out[540]
  PIN ahbsi_out[539]
    DIRECTION OUTPUT ;
    USE SIGNAL ;
    PORT
      LAYER Metal4 ;
        RECT 10.2650 363.9400 10.3350 364.2300 ;
    END
  END ahbsi_out[539]
  PIN ahbsi_out[538]
    DIRECTION OUTPUT ;
    USE SIGNAL ;
    PORT
      LAYER Metal3 ;
        RECT 0.0000 339.4000 0.2900 339.4700 ;
    END
  END ahbsi_out[538]
  PIN ahbsi_out[537]
    DIRECTION OUTPUT ;
    USE SIGNAL ;
    PORT
      LAYER Metal5 ;
        RECT 0.0000 339.9700 0.2900 340.0400 ;
    END
  END ahbsi_out[537]
  PIN ahbsi_out[536]
    DIRECTION OUTPUT ;
    USE SIGNAL ;
    PORT
      LAYER Metal3 ;
        RECT 0.0000 339.7800 0.2900 339.8500 ;
    END
  END ahbsi_out[536]
  PIN ahbsi_out[535]
    DIRECTION OUTPUT ;
    USE SIGNAL ;
    PORT
      LAYER Metal2 ;
        RECT 36.0650 363.9400 36.1350 364.2300 ;
    END
  END ahbsi_out[535]
  PIN ahbsi_out[534]
    DIRECTION OUTPUT ;
    USE SIGNAL ;
    PORT
      LAYER Metal3 ;
        RECT 0.0000 335.6000 0.2900 335.6700 ;
    END
  END ahbsi_out[534]
  PIN ahbsi_out[533]
    DIRECTION OUTPUT ;
    USE SIGNAL ;
    PORT
      LAYER Metal3 ;
        RECT 0.0000 331.4200 0.2900 331.4900 ;
    END
  END ahbsi_out[533]
  PIN ahbsi_out[532]
    DIRECTION OUTPUT ;
    USE SIGNAL ;
    PORT
      LAYER Metal3 ;
        RECT 0.0000 328.3800 0.2900 328.4500 ;
    END
  END ahbsi_out[532]
  PIN ahbsi_out[531]
    DIRECTION OUTPUT ;
    USE SIGNAL ;
    PORT
      LAYER Metal3 ;
        RECT 0.0000 323.8200 0.2900 323.8900 ;
    END
  END ahbsi_out[531]
  PIN ahbsi_out[530]
    DIRECTION OUTPUT ;
    USE SIGNAL ;
    PORT
      LAYER Metal3 ;
        RECT 0.0000 321.9200 0.2900 321.9900 ;
    END
  END ahbsi_out[530]
  PIN ahbsi_out[529]
    DIRECTION OUTPUT ;
    USE SIGNAL ;
    PORT
      LAYER Metal3 ;
        RECT 0.0000 325.3400 0.2900 325.4100 ;
    END
  END ahbsi_out[529]
  PIN ahbsi_out[528]
    DIRECTION OUTPUT ;
    USE SIGNAL ;
    PORT
      LAYER Metal3 ;
        RECT 0.0000 326.8600 0.2900 326.9300 ;
    END
  END ahbsi_out[528]
  PIN ahbsi_out[527]
    DIRECTION OUTPUT ;
    USE SIGNAL ;
    PORT
      LAYER Metal3 ;
        RECT 0.0000 328.0000 0.2900 328.0700 ;
    END
  END ahbsi_out[527]
  PIN ahbsi_out[526]
    DIRECTION OUTPUT ;
    USE SIGNAL ;
    PORT
      LAYER Metal2 ;
        RECT 10.4650 363.9400 10.5350 364.2300 ;
    END
  END ahbsi_out[526]
  PIN ahbsi_out[525]
    DIRECTION OUTPUT ;
    USE SIGNAL ;
    PORT
      LAYER Metal3 ;
        RECT 0.0000 348.5200 0.2900 348.5900 ;
    END
  END ahbsi_out[525]
  PIN ahbsi_out[524]
    DIRECTION OUTPUT ;
    USE SIGNAL ;
    PORT
      LAYER Metal3 ;
        RECT 0.0000 355.3600 0.2900 355.4300 ;
    END
  END ahbsi_out[524]
  PIN ahbsi_out[523]
    DIRECTION OUTPUT ;
    USE SIGNAL ;
    PORT
      LAYER Metal3 ;
        RECT 0.0000 354.9800 0.2900 355.0500 ;
    END
  END ahbsi_out[523]
  PIN ahbsi_out[522]
    DIRECTION OUTPUT ;
    USE SIGNAL ;
    PORT
      LAYER Metal2 ;
        RECT 13.4650 363.9400 13.5350 364.2300 ;
    END
  END ahbsi_out[522]
  PIN ahbsi_out[521]
    DIRECTION OUTPUT ;
    USE SIGNAL ;
    PORT
      LAYER Metal3 ;
        RECT 0.0000 358.4000 0.2900 358.4700 ;
    END
  END ahbsi_out[521]
  PIN ahbsi_out[520]
    DIRECTION OUTPUT ;
    USE SIGNAL ;
    PORT
      LAYER Metal3 ;
        RECT 0.0000 357.2600 0.2900 357.3300 ;
    END
  END ahbsi_out[520]
  PIN ahbsi_out[519]
    DIRECTION OUTPUT ;
    USE SIGNAL ;
    PORT
      LAYER Metal3 ;
        RECT 0.0000 356.5000 0.2900 356.5700 ;
    END
  END ahbsi_out[519]
  PIN ahbsi_out[518]
    DIRECTION OUTPUT ;
    USE SIGNAL ;
    PORT
      LAYER Metal3 ;
        RECT 0.0000 352.7000 0.2900 352.7700 ;
    END
  END ahbsi_out[518]
  PIN ahbsi_out[517]
    DIRECTION OUTPUT ;
    USE SIGNAL ;
    PORT
      LAYER Metal3 ;
        RECT 0.0000 349.2800 0.2900 349.3500 ;
    END
  END ahbsi_out[517]
  PIN ahbsi_out[516]
    DIRECTION OUTPUT ;
    USE SIGNAL ;
    PORT
      LAYER Metal3 ;
        RECT 0.0000 344.7200 0.2900 344.7900 ;
    END
  END ahbsi_out[516]
  PIN ahbsi_out[515]
    DIRECTION OUTPUT ;
    USE SIGNAL ;
    PORT
      LAYER Metal3 ;
        RECT 0.0000 331.9900 0.2900 332.0600 ;
    END
  END ahbsi_out[515]
  PIN ahbsi_out[514]
    DIRECTION OUTPUT ;
    USE SIGNAL ;
    PORT
      LAYER Metal3 ;
        RECT 0.0000 327.6200 0.2900 327.6900 ;
    END
  END ahbsi_out[514]
  PIN ahbsi_out[513]
    DIRECTION OUTPUT ;
    USE SIGNAL ;
    PORT
      LAYER Metal2 ;
        RECT 1678.6650 363.9400 1678.7350 364.2300 ;
    END
  END ahbsi_out[513]
  PIN ahbsi_out[512]
    DIRECTION OUTPUT ;
    USE SIGNAL ;
    PORT
      LAYER Metal4 ;
        RECT 1678.6650 363.9400 1678.7350 364.2300 ;
    END
  END ahbsi_out[512]
  PIN ahbsi_out[511]
    DIRECTION OUTPUT ;
    USE SIGNAL ;
    PORT
      LAYER Metal6 ;
        RECT 1678.6650 363.9400 1678.7350 364.2300 ;
    END
  END ahbsi_out[511]
  PIN ahbsi_out[510]
    DIRECTION OUTPUT ;
    USE SIGNAL ;
    PORT
      LAYER Metal2 ;
        RECT 1682.6650 363.9400 1682.7350 364.2300 ;
    END
  END ahbsi_out[510]
  PIN ahbsi_out[509]
    DIRECTION OUTPUT ;
    USE SIGNAL ;
    PORT
      LAYER Metal2 ;
        RECT 170.8650 363.9400 170.9350 364.2300 ;
    END
  END ahbsi_out[509]
  PIN ahbsi_out[508]
    DIRECTION OUTPUT ;
    USE SIGNAL ;
    PORT
      LAYER Metal4 ;
        RECT 1682.6650 363.9400 1682.7350 364.2300 ;
    END
  END ahbsi_out[508]
  PIN ahbsi_out[507]
    DIRECTION OUTPUT ;
    USE SIGNAL ;
    PORT
      LAYER Metal6 ;
        RECT 1682.6650 363.9400 1682.7350 364.2300 ;
    END
  END ahbsi_out[507]
  PIN ahbsi_out[506]
    DIRECTION OUTPUT ;
    USE SIGNAL ;
    PORT
      LAYER Metal8 ;
        RECT 1682.6650 363.9400 1682.7350 364.2300 ;
    END
  END ahbsi_out[506]
  PIN ahbsi_out[505]
    DIRECTION OUTPUT ;
    USE SIGNAL ;
    PORT
      LAYER Metal2 ;
        RECT 1678.2650 363.9400 1678.3350 364.2300 ;
    END
  END ahbsi_out[505]
  PIN ahbsi_out[504]
    DIRECTION OUTPUT ;
    USE SIGNAL ;
    PORT
      LAYER Metal4 ;
        RECT 1678.2650 363.9400 1678.3350 364.2300 ;
    END
  END ahbsi_out[504]
  PIN ahbsi_out[503]
    DIRECTION OUTPUT ;
    USE SIGNAL ;
    PORT
      LAYER Metal5 ;
        RECT 0.0000 332.9400 0.2900 333.0100 ;
    END
  END ahbsi_out[503]
  PIN ahbsi_out[502]
    DIRECTION OUTPUT ;
    USE SIGNAL ;
    PORT
      LAYER Metal6 ;
        RECT 1678.2650 363.9400 1678.3350 364.2300 ;
    END
  END ahbsi_out[502]
  PIN ahbsi_out[501]
    DIRECTION OUTPUT ;
    USE SIGNAL ;
    PORT
      LAYER Metal2 ;
        RECT 1683.0650 363.9400 1683.1350 364.2300 ;
    END
  END ahbsi_out[501]
  PIN ahbsi_out[500]
    DIRECTION OUTPUT ;
    USE SIGNAL ;
    PORT
      LAYER Metal4 ;
        RECT 1683.0650 363.9400 1683.1350 364.2300 ;
    END
  END ahbsi_out[500]
  PIN ahbsi_out[499]
    DIRECTION OUTPUT ;
    USE SIGNAL ;
    PORT
      LAYER Metal6 ;
        RECT 1683.0650 363.9400 1683.1350 364.2300 ;
    END
  END ahbsi_out[499]
  PIN ahbsi_out[498]
    DIRECTION OUTPUT ;
    USE SIGNAL ;
    PORT
      LAYER Metal8 ;
        RECT 1683.0650 363.9400 1683.1350 364.2300 ;
    END
  END ahbsi_out[498]
  PIN ahbsi_out[497]
    DIRECTION OUTPUT ;
    USE SIGNAL ;
    PORT
      LAYER Metal2 ;
        RECT 1677.8650 363.9400 1677.9350 364.2300 ;
    END
  END ahbsi_out[497]
  PIN ahbsi_out[496]
    DIRECTION OUTPUT ;
    USE SIGNAL ;
    PORT
      LAYER Metal4 ;
        RECT 1677.8650 363.9400 1677.9350 364.2300 ;
    END
  END ahbsi_out[496]
  PIN ahbsi_out[495]
    DIRECTION OUTPUT ;
    USE SIGNAL ;
    PORT
      LAYER Metal6 ;
        RECT 1677.8650 363.9400 1677.9350 364.2300 ;
    END
  END ahbsi_out[495]
  PIN ahbsi_out[494]
    DIRECTION OUTPUT ;
    USE SIGNAL ;
    PORT
      LAYER Metal2 ;
        RECT 1683.4650 363.9400 1683.5350 364.2300 ;
    END
  END ahbsi_out[494]
  PIN ahbsi_out[493]
    DIRECTION OUTPUT ;
    USE SIGNAL ;
    PORT
      LAYER Metal4 ;
        RECT 1683.4650 363.9400 1683.5350 364.2300 ;
    END
  END ahbsi_out[493]
  PIN ahbsi_out[492]
    DIRECTION OUTPUT ;
    USE SIGNAL ;
    PORT
      LAYER Metal6 ;
        RECT 1683.4650 363.9400 1683.5350 364.2300 ;
    END
  END ahbsi_out[492]
  PIN ahbsi_out[491]
    DIRECTION OUTPUT ;
    USE SIGNAL ;
    PORT
      LAYER Metal8 ;
        RECT 1683.4650 363.9400 1683.5350 364.2300 ;
    END
  END ahbsi_out[491]
  PIN ahbsi_out[490]
    DIRECTION OUTPUT ;
    USE SIGNAL ;
    PORT
      LAYER Metal2 ;
        RECT 1677.4650 363.9400 1677.5350 364.2300 ;
    END
  END ahbsi_out[490]
  PIN ahbsi_out[489]
    DIRECTION OUTPUT ;
    USE SIGNAL ;
    PORT
      LAYER Metal4 ;
        RECT 1677.4650 363.9400 1677.5350 364.2300 ;
    END
  END ahbsi_out[489]
  PIN ahbsi_out[488]
    DIRECTION OUTPUT ;
    USE SIGNAL ;
    PORT
      LAYER Metal6 ;
        RECT 1677.4650 363.9400 1677.5350 364.2300 ;
    END
  END ahbsi_out[488]
  PIN ahbsi_out[487]
    DIRECTION OUTPUT ;
    USE SIGNAL ;
    PORT
      LAYER Metal5 ;
        RECT 0.0000 333.7000 0.2900 333.7700 ;
    END
  END ahbsi_out[487]
  PIN ahbsi_out[486]
    DIRECTION OUTPUT ;
    USE SIGNAL ;
    PORT
      LAYER Metal2 ;
        RECT 1683.8650 363.9400 1683.9350 364.2300 ;
    END
  END ahbsi_out[486]
  PIN ahbsi_out[485]
    DIRECTION OUTPUT ;
    USE SIGNAL ;
    PORT
      LAYER Metal4 ;
        RECT 1683.8650 363.9400 1683.9350 364.2300 ;
    END
  END ahbsi_out[485]
  PIN ahbsi_out[484]
    DIRECTION OUTPUT ;
    USE SIGNAL ;
    PORT
      LAYER Metal6 ;
        RECT 1683.8650 363.9400 1683.9350 364.2300 ;
    END
  END ahbsi_out[484]
  PIN ahbsi_out[483]
    DIRECTION OUTPUT ;
    USE SIGNAL ;
    PORT
      LAYER Metal8 ;
        RECT 1683.8650 363.9400 1683.9350 364.2300 ;
    END
  END ahbsi_out[483]
  PIN ahbsi_out[482]
    DIRECTION OUTPUT ;
    USE SIGNAL ;
    PORT
      LAYER Metal3 ;
        RECT 0.0000 359.3500 0.2900 359.4200 ;
    END
  END ahbsi_out[482]
  PIN ahbsi_out[481]
    DIRECTION OUTPUT ;
    USE SIGNAL ;
    PORT
      LAYER Metal5 ;
        RECT 0.0000 359.1600 0.2900 359.2300 ;
    END
  END ahbsi_out[481]
  PIN ahbsi_out[480]
    DIRECTION OUTPUT ;
    USE SIGNAL ;
    PORT
      LAYER Metal9 ;
        RECT 0.0000 357.2600 0.2900 357.3300 ;
    END
  END ahbsi_out[480]
  PIN ahbsi_out[479]
    DIRECTION OUTPUT ;
    USE SIGNAL ;
    PORT
      LAYER Metal5 ;
        RECT 0.0000 347.7600 0.2900 347.8300 ;
    END
  END ahbsi_out[479]
  PIN ahbsi_out[478]
    DIRECTION OUTPUT ;
    USE SIGNAL ;
    PORT
      LAYER Metal5 ;
        RECT 0.0000 347.0000 0.2900 347.0700 ;
    END
  END ahbsi_out[478]
  PIN ahbsi_out[477]
    DIRECTION OUTPUT ;
    USE SIGNAL ;
    PORT
      LAYER Metal5 ;
        RECT 0.0000 348.1400 0.2900 348.2100 ;
    END
  END ahbsi_out[477]
  PIN ahbsi_out[476]
    DIRECTION OUTPUT ;
    USE SIGNAL ;
    PORT
      LAYER Metal5 ;
        RECT 0.0000 349.2800 0.2900 349.3500 ;
    END
  END ahbsi_out[476]
  PIN ahbsi_out[475]
    DIRECTION OUTPUT ;
    USE SIGNAL ;
    PORT
      LAYER Metal3 ;
        RECT 0.0000 353.8400 0.2900 353.9100 ;
    END
  END ahbsi_out[475]
  PIN ahbsi_out[474]
    DIRECTION OUTPUT ;
    USE SIGNAL ;
    PORT
      LAYER Metal5 ;
        RECT 0.0000 357.2600 0.2900 357.3300 ;
    END
  END ahbsi_out[474]
  PIN ahbsi_out[473]
    DIRECTION OUTPUT ;
    USE SIGNAL ;
    PORT
      LAYER Metal9 ;
        RECT 0.0000 356.5000 0.2900 356.5700 ;
    END
  END ahbsi_out[473]
  PIN ahbsi_out[472]
    DIRECTION OUTPUT ;
    USE SIGNAL ;
    PORT
      LAYER Metal2 ;
        RECT 1677.0650 363.9400 1677.1350 364.2300 ;
    END
  END ahbsi_out[472]
  PIN ahbsi_out[471]
    DIRECTION OUTPUT ;
    USE SIGNAL ;
    PORT
      LAYER Metal4 ;
        RECT 1677.0650 363.9400 1677.1350 364.2300 ;
    END
  END ahbsi_out[471]
  PIN ahbsi_out[470]
    DIRECTION OUTPUT ;
    USE SIGNAL ;
    PORT
      LAYER Metal5 ;
        RECT 0.0000 359.5400 0.2900 359.6100 ;
    END
  END ahbsi_out[470]
  PIN ahbsi_out[469]
    DIRECTION OUTPUT ;
    USE SIGNAL ;
    PORT
      LAYER Metal9 ;
        RECT 0.0000 347.3800 0.2900 347.4500 ;
    END
  END ahbsi_out[469]
  PIN ahbsi_out[468]
    DIRECTION OUTPUT ;
    USE SIGNAL ;
    PORT
      LAYER Metal5 ;
        RECT 0.0000 347.3800 0.2900 347.4500 ;
    END
  END ahbsi_out[468]
  PIN ahbsi_out[467]
    DIRECTION OUTPUT ;
    USE SIGNAL ;
    PORT
      LAYER Metal9 ;
        RECT 0.0000 353.8400 0.2900 353.9100 ;
    END
  END ahbsi_out[467]
  PIN ahbsi_out[466]
    DIRECTION OUTPUT ;
    USE SIGNAL ;
    PORT
      LAYER Metal5 ;
        RECT 0.0000 353.8400 0.2900 353.9100 ;
    END
  END ahbsi_out[466]
  PIN ahbsi_out[465]
    DIRECTION OUTPUT ;
    USE SIGNAL ;
    PORT
      LAYER Metal9 ;
        RECT 0.0000 351.9400 0.2900 352.0100 ;
    END
  END ahbsi_out[465]
  PIN ahbsi_out[464]
    DIRECTION OUTPUT ;
    USE SIGNAL ;
    PORT
      LAYER Metal6 ;
        RECT 1677.0650 363.9400 1677.1350 364.2300 ;
    END
  END ahbsi_out[464]
  PIN ahbsi_out[463]
    DIRECTION OUTPUT ;
    USE SIGNAL ;
    PORT
      LAYER Metal2 ;
        RECT 1684.2650 363.9400 1684.3350 364.2300 ;
    END
  END ahbsi_out[463]
  PIN ahbsi_out[462]
    DIRECTION OUTPUT ;
    USE SIGNAL ;
    PORT
      LAYER Metal4 ;
        RECT 1684.2650 363.9400 1684.3350 364.2300 ;
    END
  END ahbsi_out[462]
  PIN ahbsi_out[461]
    DIRECTION OUTPUT ;
    USE SIGNAL ;
    PORT
      LAYER Metal3 ;
        RECT 0.0000 346.0500 0.2900 346.1200 ;
    END
  END ahbsi_out[461]
  PIN ahbsi_out[460]
    DIRECTION OUTPUT ;
    USE SIGNAL ;
    PORT
      LAYER Metal4 ;
        RECT 18.4650 363.9400 18.5350 364.2300 ;
    END
  END ahbsi_out[460]
  PIN ahbsi_out[459]
    DIRECTION OUTPUT ;
    USE SIGNAL ;
    PORT
      LAYER Metal3 ;
        RECT 0.0000 324.5800 0.2900 324.6500 ;
    END
  END ahbsi_out[459]
  PIN ahbsi_out[458]
    DIRECTION OUTPUT ;
    USE SIGNAL ;
    PORT
      LAYER Metal4 ;
        RECT 18.8650 363.9400 18.9350 364.2300 ;
    END
  END ahbsi_out[458]
  PIN ahbsi_out[457]
    DIRECTION OUTPUT ;
    USE SIGNAL ;
    PORT
      LAYER Metal9 ;
        RECT 0.0000 323.4400 0.2900 323.5100 ;
    END
  END ahbsi_out[457]
  PIN ahbsi_out[456]
    DIRECTION OUTPUT ;
    USE SIGNAL ;
    PORT
      LAYER Metal5 ;
        RECT 0.0000 328.7600 0.2900 328.8300 ;
    END
  END ahbsi_out[456]
  PIN ahbsi_out[455]
    DIRECTION OUTPUT ;
    USE SIGNAL ;
    PORT
      LAYER Metal2 ;
        RECT 4.6650 363.9400 4.7350 364.2300 ;
    END
  END ahbsi_out[455]
  PIN ahbsi_out[454]
    DIRECTION OUTPUT ;
    USE SIGNAL ;
    PORT
      LAYER Metal5 ;
        RECT 0.0000 351.9400 0.2900 352.0100 ;
    END
  END ahbsi_out[454]
  PIN ahbsi_out[453]
    DIRECTION OUTPUT ;
    USE SIGNAL ;
    PORT
      LAYER Metal3 ;
        RECT 0.0000 351.1800 0.2900 351.2500 ;
    END
  END ahbsi_out[453]
  PIN ahbsi_out[452]
    DIRECTION OUTPUT ;
    USE SIGNAL ;
    PORT
      LAYER Metal3 ;
        RECT 0.0000 348.1400 0.2900 348.2100 ;
    END
  END ahbsi_out[452]
  PIN ahbsi_out[451]
    DIRECTION OUTPUT ;
    USE SIGNAL ;
    PORT
      LAYER Metal4 ;
        RECT 16.0650 363.9400 16.1350 364.2300 ;
    END
  END ahbsi_out[451]
  PIN ahbsi_out[450]
    DIRECTION OUTPUT ;
    USE SIGNAL ;
    PORT
      LAYER Metal2 ;
        RECT 18.2650 363.9400 18.3350 364.2300 ;
    END
  END ahbsi_out[450]
  PIN ahbsi_out[449]
    DIRECTION OUTPUT ;
    USE SIGNAL ;
    PORT
      LAYER Metal2 ;
        RECT 24.4650 363.9400 24.5350 364.2300 ;
    END
  END ahbsi_out[449]
  PIN ahbsi_out[448]
    DIRECTION OUTPUT ;
    USE SIGNAL ;
    PORT
      LAYER Metal2 ;
        RECT 41.0650 363.9400 41.1350 364.2300 ;
    END
  END ahbsi_out[448]
  PIN ahbsi_out[447]
    DIRECTION OUTPUT ;
    USE SIGNAL ;
    PORT
      LAYER Metal2 ;
        RECT 41.4650 363.9400 41.5350 364.2300 ;
    END
  END ahbsi_out[447]
  PIN ahbsi_out[446]
    DIRECTION OUTPUT ;
    USE SIGNAL ;
    PORT
      LAYER Metal2 ;
        RECT 28.2650 363.9400 28.3350 364.2300 ;
    END
  END ahbsi_out[446]
  PIN ahbsi_out[445]
    DIRECTION OUTPUT ;
    USE SIGNAL ;
    PORT
      LAYER Metal2 ;
        RECT 22.0650 363.9400 22.1350 364.2300 ;
    END
  END ahbsi_out[445]
  PIN ahbsi_out[444]
    DIRECTION OUTPUT ;
    USE SIGNAL ;
    PORT
      LAYER Metal2 ;
        RECT 16.2650 363.9400 16.3350 364.2300 ;
    END
  END ahbsi_out[444]
  PIN ahbsi_out[443]
    DIRECTION OUTPUT ;
    USE SIGNAL ;
    PORT
      LAYER Metal5 ;
        RECT 0.0000 340.5400 0.2900 340.6100 ;
    END
  END ahbsi_out[443]
  PIN ahbsi_out[442]
    DIRECTION OUTPUT ;
    USE SIGNAL ;
    PORT
      LAYER Metal9 ;
        RECT 0.0000 340.9200 0.2900 340.9900 ;
    END
  END ahbsi_out[442]
  PIN ahbsi_out[441]
    DIRECTION OUTPUT ;
    USE SIGNAL ;
    PORT
      LAYER Metal9 ;
        RECT 0.0000 345.8600 0.2900 345.9300 ;
    END
  END ahbsi_out[441]
  PIN ahbsi_out[440]
    DIRECTION OUTPUT ;
    USE SIGNAL ;
    PORT
      LAYER Metal5 ;
        RECT 0.0000 355.9300 0.2900 356.0000 ;
    END
  END ahbsi_out[440]
  PIN ahbsi_out[439]
    DIRECTION OUTPUT ;
    USE SIGNAL ;
    PORT
      LAYER Metal9 ;
        RECT 0.0000 359.5400 0.2900 359.6100 ;
    END
  END ahbsi_out[439]
  PIN ahbsi_out[438]
    DIRECTION OUTPUT ;
    USE SIGNAL ;
    PORT
      LAYER Metal2 ;
        RECT 13.0650 363.9400 13.1350 364.2300 ;
    END
  END ahbsi_out[438]
  PIN ahbsi_out[437]
    DIRECTION OUTPUT ;
    USE SIGNAL ;
    PORT
      LAYER Metal8 ;
        RECT 10.4650 363.9400 10.5350 364.2300 ;
    END
  END ahbsi_out[437]
  PIN ahbsi_out[436]
    DIRECTION OUTPUT ;
    USE SIGNAL ;
    PORT
      LAYER Metal2 ;
        RECT 14.4650 363.9400 14.5350 364.2300 ;
    END
  END ahbsi_out[436]
  PIN ahbsi_out[435]
    DIRECTION OUTPUT ;
    USE SIGNAL ;
    PORT
      LAYER Metal2 ;
        RECT 17.2650 363.9400 17.3350 364.2300 ;
    END
  END ahbsi_out[435]
  PIN ahbsi_out[434]
    DIRECTION OUTPUT ;
    USE SIGNAL ;
    PORT
      LAYER Metal2 ;
        RECT 21.6650 363.9400 21.7350 364.2300 ;
    END
  END ahbsi_out[434]
  PIN ahbsi_out[433]
    DIRECTION OUTPUT ;
    USE SIGNAL ;
    PORT
      LAYER Metal2 ;
        RECT 19.4650 363.9400 19.5350 364.2300 ;
    END
  END ahbsi_out[433]
  PIN ahbsi_out[432]
    DIRECTION OUTPUT ;
    USE SIGNAL ;
    PORT
      LAYER Metal2 ;
        RECT 15.0650 363.9400 15.1350 364.2300 ;
    END
  END ahbsi_out[432]
  PIN ahbsi_out[431]
    DIRECTION OUTPUT ;
    USE SIGNAL ;
    PORT
      LAYER Metal2 ;
        RECT 19.0650 363.9400 19.1350 364.2300 ;
    END
  END ahbsi_out[431]
  PIN ahbsi_out[430]
    DIRECTION OUTPUT ;
    USE SIGNAL ;
    PORT
      LAYER Metal2 ;
        RECT 27.4650 363.9400 27.5350 364.2300 ;
    END
  END ahbsi_out[430]
  PIN ahbsi_out[429]
    DIRECTION OUTPUT ;
    USE SIGNAL ;
    PORT
      LAYER Metal6 ;
        RECT 1684.2650 363.9400 1684.3350 364.2300 ;
    END
  END ahbsi_out[429]
  PIN ahbsi_out[428]
    DIRECTION OUTPUT ;
    USE SIGNAL ;
    PORT
      LAYER Metal8 ;
        RECT 1684.2650 363.9400 1684.3350 364.2300 ;
    END
  END ahbsi_out[428]
  PIN ahbsi_out[427]
    DIRECTION OUTPUT ;
    USE SIGNAL ;
    PORT
      LAYER Metal2 ;
        RECT 1676.6650 363.9400 1676.7350 364.2300 ;
    END
  END ahbsi_out[427]
  PIN ahbsi_out[426]
    DIRECTION OUTPUT ;
    USE SIGNAL ;
    PORT
      LAYER Metal4 ;
        RECT 1676.6650 363.9400 1676.7350 364.2300 ;
    END
  END ahbsi_out[426]
  PIN ahbsi_out[425]
    DIRECTION OUTPUT ;
    USE SIGNAL ;
    PORT
      LAYER Metal9 ;
        RECT 0.0000 349.2800 0.2900 349.3500 ;
    END
  END ahbsi_out[425]
  PIN ahbsi_out[424]
    DIRECTION OUTPUT ;
    USE SIGNAL ;
    PORT
      LAYER Metal6 ;
        RECT 1676.6650 363.9400 1676.7350 364.2300 ;
    END
  END ahbsi_out[424]
  PIN ahbsi_out[423]
    DIRECTION OUTPUT ;
    USE SIGNAL ;
    PORT
      LAYER Metal2 ;
        RECT 1684.6650 363.9400 1684.7350 364.2300 ;
    END
  END ahbsi_out[423]
  PIN ahbsi_out[422]
    DIRECTION OUTPUT ;
    USE SIGNAL ;
    PORT
      LAYER Metal4 ;
        RECT 1684.6650 363.9400 1684.7350 364.2300 ;
    END
  END ahbsi_out[422]
  PIN ahbsi_out[421]
    DIRECTION OUTPUT ;
    USE SIGNAL ;
    PORT
      LAYER Metal6 ;
        RECT 1684.6650 363.9400 1684.7350 364.2300 ;
    END
  END ahbsi_out[421]
  PIN ahbsi_out[420]
    DIRECTION OUTPUT ;
    USE SIGNAL ;
    PORT
      LAYER Metal8 ;
        RECT 1684.6650 363.9400 1684.7350 364.2300 ;
    END
  END ahbsi_out[420]
  PIN ahbsi_out[419]
    DIRECTION OUTPUT ;
    USE SIGNAL ;
    PORT
      LAYER Metal2 ;
        RECT 166.2650 363.9400 166.3350 364.2300 ;
    END
  END ahbsi_out[419]
  PIN ahbsi_out[418]
    DIRECTION OUTPUT ;
    USE SIGNAL ;
    PORT
      LAYER Metal5 ;
        RECT 0.0000 353.4600 0.2900 353.5300 ;
    END
  END ahbsi_out[418]
  PIN ahbsi_out[417]
    DIRECTION OUTPUT ;
    USE SIGNAL ;
    PORT
      LAYER Metal2 ;
        RECT 253.4650 363.9400 253.5350 364.2300 ;
    END
  END ahbsi_out[417]
  PIN ahbsi_out[416]
    DIRECTION OUTPUT ;
    USE SIGNAL ;
    PORT
      LAYER Metal2 ;
        RECT 284.2650 363.9400 284.3350 364.2300 ;
    END
  END ahbsi_out[416]
  PIN ahbsi_out[415]
    DIRECTION OUTPUT ;
    USE SIGNAL ;
    PORT
      LAYER Metal9 ;
        RECT 0.0000 343.5800 0.2900 343.6500 ;
    END
  END ahbsi_out[415]
  PIN ahbsi_out[414]
    DIRECTION OUTPUT ;
    USE SIGNAL ;
    PORT
      LAYER Metal5 ;
        RECT 0.0000 342.4400 0.2900 342.5100 ;
    END
  END ahbsi_out[414]
  PIN ahbsi_out[413]
    DIRECTION OUTPUT ;
    USE SIGNAL ;
    PORT
      LAYER Metal2 ;
        RECT 329.2650 363.9400 329.3350 364.2300 ;
    END
  END ahbsi_out[413]
  PIN ahbsi_out[412]
    DIRECTION OUTPUT ;
    USE SIGNAL ;
    PORT
      LAYER Metal9 ;
        RECT 0.0000 342.8200 0.2900 342.8900 ;
    END
  END ahbsi_out[412]
  PIN ahbsi_out[411]
    DIRECTION OUTPUT ;
    USE SIGNAL ;
    PORT
      LAYER Metal5 ;
        RECT 0.0000 345.1000 0.2900 345.1700 ;
    END
  END ahbsi_out[411]
  PIN ahbsi_out[410]
    DIRECTION OUTPUT ;
    USE SIGNAL ;
    PORT
      LAYER Metal2 ;
        RECT 346.8650 363.9400 346.9350 364.2300 ;
    END
  END ahbsi_out[410]
  PIN ahbsi_out[409]
    DIRECTION OUTPUT ;
    USE SIGNAL ;
    PORT
      LAYER Metal5 ;
        RECT 0.0000 342.0600 0.2900 342.1300 ;
    END
  END ahbsi_out[409]
  PIN ahbsi_out[408]
    DIRECTION OUTPUT ;
    USE SIGNAL ;
    PORT
      LAYER Metal3 ;
        RECT 0.0000 343.9600 0.2900 344.0300 ;
    END
  END ahbsi_out[408]
  PIN ahbsi_out[407]
    DIRECTION OUTPUT ;
    USE SIGNAL ;
    PORT
      LAYER Metal5 ;
        RECT 0.0000 344.3400 0.2900 344.4100 ;
    END
  END ahbsi_out[407]
  PIN ahbsi_out[406]
    DIRECTION OUTPUT ;
    USE SIGNAL ;
    PORT
      LAYER Metal5 ;
        RECT 0.0000 343.5800 0.2900 343.6500 ;
    END
  END ahbsi_out[406]
  PIN ahbsi_out[405]
    DIRECTION OUTPUT ;
    USE SIGNAL ;
    PORT
      LAYER Metal2 ;
        RECT 312.0650 363.9400 312.1350 364.2300 ;
    END
  END ahbsi_out[405]
  PIN ahbsi_out[404]
    DIRECTION OUTPUT ;
    USE SIGNAL ;
    PORT
      LAYER Metal5 ;
        RECT 0.0000 339.5900 0.2900 339.6600 ;
    END
  END ahbsi_out[404]
  PIN ahbsi_out[403]
    DIRECTION OUTPUT ;
    USE SIGNAL ;
    PORT
      LAYER Metal2 ;
        RECT 307.2650 363.9400 307.3350 364.2300 ;
    END
  END ahbsi_out[403]
  PIN ahbsi_out[402]
    DIRECTION OUTPUT ;
    USE SIGNAL ;
    PORT
      LAYER Metal3 ;
        RECT 0.0000 337.5000 0.2900 337.5700 ;
    END
  END ahbsi_out[402]
  PIN ahbsi_out[401]
    DIRECTION OUTPUT ;
    USE SIGNAL ;
    PORT
      LAYER Metal2 ;
        RECT 288.2650 363.9400 288.3350 364.2300 ;
    END
  END ahbsi_out[401]
  PIN ahbsi_out[400]
    DIRECTION OUTPUT ;
    USE SIGNAL ;
    PORT
      LAYER Metal4 ;
        RECT 264.0650 363.9400 264.1350 364.2300 ;
    END
  END ahbsi_out[400]
  PIN ahbsi_out[399]
    DIRECTION OUTPUT ;
    USE SIGNAL ;
    PORT
      LAYER Metal2 ;
        RECT 169.0650 363.9400 169.1350 364.2300 ;
    END
  END ahbsi_out[399]
  PIN ahbsi_out[398]
    DIRECTION OUTPUT ;
    USE SIGNAL ;
    PORT
      LAYER Metal9 ;
        RECT 0.0000 354.6000 0.2900 354.6700 ;
    END
  END ahbsi_out[398]
  PIN ahbsi_out[397]
    DIRECTION OUTPUT ;
    USE SIGNAL ;
    PORT
      LAYER Metal5 ;
        RECT 0.0000 354.7900 0.2900 354.8600 ;
    END
  END ahbsi_out[397]
  PIN ahbsi_out[396]
    DIRECTION OUTPUT ;
    USE SIGNAL ;
    PORT
      LAYER Metal3 ;
        RECT 0.0000 354.2200 0.2900 354.2900 ;
    END
  END ahbsi_out[396]
  PIN ahbsi_out[395]
    DIRECTION OUTPUT ;
    USE SIGNAL ;
    PORT
      LAYER Metal5 ;
        RECT 0.0000 348.5200 0.2900 348.5900 ;
    END
  END ahbsi_out[395]
  PIN ahbsi_out[394]
    DIRECTION OUTPUT ;
    USE SIGNAL ;
    PORT
      LAYER Metal9 ;
        RECT 0.0000 346.6200 0.2900 346.6900 ;
    END
  END ahbsi_out[394]
  PIN ahbsi_out[393]
    DIRECTION OUTPUT ;
    USE SIGNAL ;
    PORT
      LAYER Metal5 ;
        RECT 0.0000 356.8800 0.2900 356.9500 ;
    END
  END ahbsi_out[393]
  PIN ahbsi_out[392]
    DIRECTION OUTPUT ;
    USE SIGNAL ;
    PORT
      LAYER Metal3 ;
        RECT 0.0000 356.1200 0.2900 356.1900 ;
    END
  END ahbsi_out[392]
  PIN ahbsi_out[391]
    DIRECTION OUTPUT ;
    USE SIGNAL ;
    PORT
      LAYER Metal3 ;
        RECT 0.0000 354.6000 0.2900 354.6700 ;
    END
  END ahbsi_out[391]
  PIN ahbsi_out[390]
    DIRECTION OUTPUT ;
    USE SIGNAL ;
    PORT
      LAYER Metal3 ;
        RECT 0.0000 352.3200 0.2900 352.3900 ;
    END
  END ahbsi_out[390]
  PIN ahbsi_out[389]
    DIRECTION OUTPUT ;
    USE SIGNAL ;
    PORT
      LAYER Metal2 ;
        RECT 52.6650 363.9400 52.7350 364.2300 ;
    END
  END ahbsi_out[389]
  PIN ahbsi_out[388]
    DIRECTION OUTPUT ;
    USE SIGNAL ;
    PORT
      LAYER Metal2 ;
        RECT 85.2650 363.9400 85.3350 364.2300 ;
    END
  END ahbsi_out[388]
  PIN ahbsi_out[387]
    DIRECTION OUTPUT ;
    USE SIGNAL ;
    PORT
      LAYER Metal5 ;
        RECT 0.0000 351.5600 0.2900 351.6300 ;
    END
  END ahbsi_out[387]
  PIN ahbsi_out[386]
    DIRECTION OUTPUT ;
    USE SIGNAL ;
    PORT
      LAYER Metal3 ;
        RECT 0.0000 347.0000 0.2900 347.0700 ;
    END
  END ahbsi_out[386]
  PIN ahbsi_out[385]
    DIRECTION OUTPUT ;
    USE SIGNAL ;
    PORT
      LAYER Metal9 ;
        RECT 0.0000 348.5200 0.2900 348.5900 ;
    END
  END ahbsi_out[385]
  PIN ahbsi_out[384]
    DIRECTION OUTPUT ;
    USE SIGNAL ;
    PORT
      LAYER Metal2 ;
        RECT 1676.2650 363.9400 1676.3350 364.2300 ;
    END
  END ahbsi_out[384]
  PIN ahbsi_out[383]
    DIRECTION OUTPUT ;
    USE SIGNAL ;
    PORT
      LAYER Metal5 ;
        RECT 0.0000 343.9600 0.2900 344.0300 ;
    END
  END ahbsi_out[383]
  PIN ahbsi_out[382]
    DIRECTION OUTPUT ;
    USE SIGNAL ;
    PORT
      LAYER Metal9 ;
        RECT 0.0000 345.1000 0.2900 345.1700 ;
    END
  END ahbsi_out[382]
  PIN ahbsi_out[381]
    DIRECTION OUTPUT ;
    USE SIGNAL ;
    PORT
      LAYER Metal2 ;
        RECT 67.0650 363.9400 67.1350 364.2300 ;
    END
  END ahbsi_out[381]
  PIN ahbsi_out[380]
    DIRECTION OUTPUT ;
    USE SIGNAL ;
    PORT
      LAYER Metal9 ;
        RECT 0.0000 350.4200 0.2900 350.4900 ;
    END
  END ahbsi_out[380]
  PIN ahbsi_out[379]
    DIRECTION OUTPUT ;
    USE SIGNAL ;
    PORT
      LAYER Metal5 ;
        RECT 0.0000 350.8000 0.2900 350.8700 ;
    END
  END ahbsi_out[379]
  PIN ahbsi_out[378]
    DIRECTION OUTPUT ;
    USE SIGNAL ;
    PORT
      LAYER Metal2 ;
        RECT 103.0650 363.9400 103.1350 364.2300 ;
    END
  END ahbsi_out[378]
  PIN ahbsi_out[377]
    DIRECTION OUTPUT ;
    USE SIGNAL ;
    PORT
      LAYER Metal5 ;
        RECT 0.0000 346.6200 0.2900 346.6900 ;
    END
  END ahbsi_out[377]
  PIN ahbsi_out[376]
    DIRECTION OUTPUT ;
    USE SIGNAL ;
    PORT
      LAYER Metal5 ;
        RECT 0.0000 337.1200 0.2900 337.1900 ;
    END
  END ahbsi_out[376]
  PIN ahbsi_out[375]
    DIRECTION OUTPUT ;
    USE SIGNAL ;
    PORT
      LAYER Metal5 ;
        RECT 0.0000 337.6900 0.2900 337.7600 ;
    END
  END ahbsi_out[375]
  PIN ahbsi_out[374]
    DIRECTION OUTPUT ;
    USE SIGNAL ;
    PORT
      LAYER Metal3 ;
        RECT 0.0000 324.2000 0.2900 324.2700 ;
    END
  END ahbsi_out[374]
  PIN ahbsi_out[373]
    DIRECTION OUTPUT ;
    USE SIGNAL ;
    PORT
      LAYER Metal6 ;
        RECT 10.6650 363.9400 10.7350 364.2300 ;
    END
  END ahbsi_out[373]
  PIN ahbsi_out[372]
    DIRECTION OUTPUT ;
    USE SIGNAL ;
    PORT
      LAYER Metal5 ;
        RECT 0.0000 338.0700 0.2900 338.1400 ;
    END
  END ahbsi_out[372]
  PIN ahbsi_out[371]
    DIRECTION OUTPUT ;
    USE SIGNAL ;
    PORT
      LAYER Metal3 ;
        RECT 0.0000 320.9700 0.2900 321.0400 ;
    END
  END ahbsi_out[371]
  PIN ahbsi_out[370]
    DIRECTION OUTPUT ;
    USE SIGNAL ;
    PORT
      LAYER Metal3 ;
        RECT 0.0000 318.8800 0.2900 318.9500 ;
    END
  END ahbsi_out[370]
  PIN ahbsi_out[369]
    DIRECTION OUTPUT ;
    USE SIGNAL ;
    PORT
      LAYER Metal3 ;
        RECT 0.0000 326.4800 0.2900 326.5500 ;
    END
  END ahbsi_out[369]
  PIN ahbsi_out[368]
    DIRECTION OUTPUT ;
    USE SIGNAL ;
    PORT
      LAYER Metal3 ;
        RECT 0.0000 336.5500 0.2900 336.6200 ;
    END
  END ahbsi_out[368]
  PIN ahbsi_out[367]
    DIRECTION OUTPUT ;
    USE SIGNAL ;
    PORT
      LAYER Metal5 ;
        RECT 0.0000 335.4100 0.2900 335.4800 ;
    END
  END ahbsi_out[367]
  PIN ahbsi_out[366]
    DIRECTION OUTPUT ;
    USE SIGNAL ;
    PORT
      LAYER Metal3 ;
        RECT 0.0000 336.9300 0.2900 337.0000 ;
    END
  END ahbsi_out[366]
  PIN ahbsi_out[365]
    DIRECTION OUTPUT ;
    USE SIGNAL ;
    PORT
      LAYER Metal3 ;
        RECT 0.0000 337.8800 0.2900 337.9500 ;
    END
  END ahbsi_out[365]
  PIN ahbsi_out[364]
    DIRECTION OUTPUT ;
    USE SIGNAL ;
    PORT
      LAYER Metal3 ;
        RECT 0.0000 338.2600 0.2900 338.3300 ;
    END
  END ahbsi_out[364]
  PIN ahbsi_out[363]
    DIRECTION OUTPUT ;
    USE SIGNAL ;
    PORT
      LAYER Metal5 ;
        RECT 0.0000 341.3000 0.2900 341.3700 ;
    END
  END ahbsi_out[363]
  PIN ahbsi_out[362]
    DIRECTION OUTPUT ;
    USE SIGNAL ;
    PORT
      LAYER Metal3 ;
        RECT 0.0000 347.3800 0.2900 347.4500 ;
    END
  END ahbsi_out[362]
  PIN ahbsi_out[361]
    DIRECTION OUTPUT ;
    USE SIGNAL ;
    PORT
      LAYER Metal5 ;
        RECT 0.0000 346.2400 0.2900 346.3100 ;
    END
  END ahbsi_out[361]
  PIN ahbsi_out[360]
    DIRECTION OUTPUT ;
    USE SIGNAL ;
    PORT
      LAYER Metal5 ;
        RECT 0.0000 345.8600 0.2900 345.9300 ;
    END
  END ahbsi_out[360]
  PIN ahbsi_out[359]
    DIRECTION OUTPUT ;
    USE SIGNAL ;
    PORT
      LAYER Metal2 ;
        RECT 38.4650 363.9400 38.5350 364.2300 ;
    END
  END ahbsi_out[359]
  PIN ahbsi_out[358]
    DIRECTION OUTPUT ;
    USE SIGNAL ;
    PORT
      LAYER Metal5 ;
        RECT 0.0000 350.0400 0.2900 350.1100 ;
    END
  END ahbsi_out[358]
  PIN ahbsi_out[357]
    DIRECTION OUTPUT ;
    USE SIGNAL ;
    PORT
      LAYER Metal3 ;
        RECT 0.0000 351.5600 0.2900 351.6300 ;
    END
  END ahbsi_out[357]
  PIN ahbsi_out[356]
    DIRECTION OUTPUT ;
    USE SIGNAL ;
    PORT
      LAYER Metal2 ;
        RECT 34.8650 363.9400 34.9350 364.2300 ;
    END
  END ahbsi_out[356]
  PIN ahbsi_out[355]
    DIRECTION OUTPUT ;
    USE SIGNAL ;
    PORT
      LAYER Metal9 ;
        RECT 0.0000 358.0200 0.2900 358.0900 ;
    END
  END ahbsi_out[355]
  PIN ahbsi_out[354]
    DIRECTION OUTPUT ;
    USE SIGNAL ;
    PORT
      LAYER Metal2 ;
        RECT 23.2650 363.9400 23.3350 364.2300 ;
    END
  END ahbsi_out[354]
  PIN ahbsi_out[353]
    DIRECTION OUTPUT ;
    USE SIGNAL ;
    PORT
      LAYER Metal5 ;
        RECT 0.0000 356.5000 0.2900 356.5700 ;
    END
  END ahbsi_out[353]
  PIN ahbsi_out[352]
    DIRECTION OUTPUT ;
    USE SIGNAL ;
    PORT
      LAYER Metal3 ;
        RECT 0.0000 355.7400 0.2900 355.8100 ;
    END
  END ahbsi_out[352]
  PIN ahbsi_out[351]
    DIRECTION OUTPUT ;
    USE SIGNAL ;
    PORT
      LAYER Metal3 ;
        RECT 0.0000 349.6600 0.2900 349.7300 ;
    END
  END ahbsi_out[351]
  PIN ahbsi_out[350]
    DIRECTION OUTPUT ;
    USE SIGNAL ;
    PORT
      LAYER Metal5 ;
        RECT 0.0000 348.9000 0.2900 348.9700 ;
    END
  END ahbsi_out[350]
  PIN ahbsi_out[349]
    DIRECTION OUTPUT ;
    USE SIGNAL ;
    PORT
      LAYER Metal5 ;
        RECT 0.0000 313.3700 0.2900 313.4400 ;
    END
  END ahbsi_out[349]
  PIN ahbsi_out[348]
    DIRECTION OUTPUT ;
    USE SIGNAL ;
    PORT
      LAYER Metal3 ;
        RECT 0.0000 310.3300 0.2900 310.4000 ;
    END
  END ahbsi_out[348]
  PIN ahbsi_out[347]
    DIRECTION OUTPUT ;
    USE SIGNAL ;
    PORT
      LAYER Metal3 ;
        RECT 0.0000 316.4100 0.2900 316.4800 ;
    END
  END ahbsi_out[347]
  PIN ahbsi_out[346]
    DIRECTION OUTPUT ;
    USE SIGNAL ;
    PORT
      LAYER Metal3 ;
        RECT 0.0000 327.2400 0.2900 327.3100 ;
    END
  END ahbsi_out[346]
  PIN ahbsi_out[345]
    DIRECTION OUTPUT ;
    USE SIGNAL ;
    PORT
      LAYER Metal4 ;
        RECT 1676.2650 363.9400 1676.3350 364.2300 ;
    END
  END ahbsi_out[345]
  PIN ahbsi_out[344]
    DIRECTION OUTPUT ;
    USE SIGNAL ;
    PORT
      LAYER Metal6 ;
        RECT 1676.2650 363.9400 1676.3350 364.2300 ;
    END
  END ahbsi_out[344]
  PIN ahbsi_out[343]
    DIRECTION OUTPUT ;
    USE SIGNAL ;
    PORT
      LAYER Metal2 ;
        RECT 1685.0650 363.9400 1685.1350 364.2300 ;
    END
  END ahbsi_out[343]
  PIN ahbsi_out[342]
    DIRECTION OUTPUT ;
    USE SIGNAL ;
    PORT
      LAYER Metal4 ;
        RECT 1685.0650 363.9400 1685.1350 364.2300 ;
    END
  END ahbsi_out[342]
  PIN ahbsi_out[341]
    DIRECTION OUTPUT ;
    USE SIGNAL ;
    PORT
      LAYER Metal5 ;
        RECT 0.0000 349.6600 0.2900 349.7300 ;
    END
  END ahbsi_out[341]
  PIN ahbsi_out[340]
    DIRECTION OUTPUT ;
    USE SIGNAL ;
    PORT
      LAYER Metal6 ;
        RECT 1685.0650 363.9400 1685.1350 364.2300 ;
    END
  END ahbsi_out[340]
  PIN ahbsi_out[339]
    DIRECTION OUTPUT ;
    USE SIGNAL ;
    PORT
      LAYER Metal8 ;
        RECT 1685.0650 363.9400 1685.1350 364.2300 ;
    END
  END ahbsi_out[339]
  PIN ahbsi_out[338]
    DIRECTION OUTPUT ;
    USE SIGNAL ;
    PORT
      LAYER Metal2 ;
        RECT 1675.8650 363.9400 1675.9350 364.2300 ;
    END
  END ahbsi_out[338]
  PIN ahbsi_out[337]
    DIRECTION OUTPUT ;
    USE SIGNAL ;
    PORT
      LAYER Metal4 ;
        RECT 1675.8650 363.9400 1675.9350 364.2300 ;
    END
  END ahbsi_out[337]
  PIN ahbsi_out[336]
    DIRECTION OUTPUT ;
    USE SIGNAL ;
    PORT
      LAYER Metal6 ;
        RECT 1675.8650 363.9400 1675.9350 364.2300 ;
    END
  END ahbsi_out[336]
  PIN ahbsi_out[335]
    DIRECTION OUTPUT ;
    USE SIGNAL ;
    PORT
      LAYER Metal2 ;
        RECT 77.2650 363.9400 77.3350 364.2300 ;
    END
  END ahbsi_out[335]
  PIN ahbsi_out[334]
    DIRECTION OUTPUT ;
    USE SIGNAL ;
    PORT
      LAYER Metal2 ;
        RECT 1685.4650 363.9400 1685.5350 364.2300 ;
    END
  END ahbsi_out[334]
  PIN ahbsi_out[333]
    DIRECTION OUTPUT ;
    USE SIGNAL ;
    PORT
      LAYER Metal4 ;
        RECT 1685.4650 363.9400 1685.5350 364.2300 ;
    END
  END ahbsi_out[333]
  PIN ahbsi_out[332]
    DIRECTION OUTPUT ;
    USE SIGNAL ;
    PORT
      LAYER Metal6 ;
        RECT 1685.4650 363.9400 1685.5350 364.2300 ;
    END
  END ahbsi_out[332]
  PIN ahbsi_out[331]
    DIRECTION OUTPUT ;
    USE SIGNAL ;
    PORT
      LAYER Metal8 ;
        RECT 1685.4650 363.9400 1685.5350 364.2300 ;
    END
  END ahbsi_out[331]
  PIN ahbsi_out[330]
    DIRECTION OUTPUT ;
    USE SIGNAL ;
    PORT
      LAYER Metal2 ;
        RECT 1675.4650 363.9400 1675.5350 364.2300 ;
    END
  END ahbsi_out[330]
  PIN ahbsi_out[329]
    DIRECTION OUTPUT ;
    USE SIGNAL ;
    PORT
      LAYER Metal4 ;
        RECT 1675.4650 363.9400 1675.5350 364.2300 ;
    END
  END ahbsi_out[329]
  PIN ahbsi_out[328]
    DIRECTION OUTPUT ;
    USE SIGNAL ;
    PORT
      LAYER Metal6 ;
        RECT 1675.4650 363.9400 1675.5350 364.2300 ;
    END
  END ahbsi_out[328]
  PIN ahbsi_out[327]
    DIRECTION OUTPUT ;
    USE SIGNAL ;
    PORT
      LAYER Metal2 ;
        RECT 1685.8650 363.9400 1685.9350 364.2300 ;
    END
  END ahbsi_out[327]
  PIN ahbsi_out[326]
    DIRECTION OUTPUT ;
    USE SIGNAL ;
    PORT
      LAYER Metal4 ;
        RECT 1685.8650 363.9400 1685.9350 364.2300 ;
    END
  END ahbsi_out[326]
  PIN ahbsi_out[325]
    DIRECTION OUTPUT ;
    USE SIGNAL ;
    PORT
      LAYER Metal6 ;
        RECT 1685.8650 363.9400 1685.9350 364.2300 ;
    END
  END ahbsi_out[325]
  PIN ahbsi_out[324]
    DIRECTION OUTPUT ;
    USE SIGNAL ;
    PORT
      LAYER Metal8 ;
        RECT 1685.8650 363.9400 1685.9350 364.2300 ;
    END
  END ahbsi_out[324]
  PIN ahbsi_out[323]
    DIRECTION OUTPUT ;
    USE SIGNAL ;
    PORT
      LAYER Metal2 ;
        RECT 1675.0650 363.9400 1675.1350 364.2300 ;
    END
  END ahbsi_out[323]
  PIN ahbsi_out[322]
    DIRECTION OUTPUT ;
    USE SIGNAL ;
    PORT
      LAYER Metal4 ;
        RECT 1675.0650 363.9400 1675.1350 364.2300 ;
    END
  END ahbsi_out[322]
  PIN ahbsi_out[321]
    DIRECTION OUTPUT ;
    USE SIGNAL ;
    PORT
      LAYER Metal6 ;
        RECT 1675.0650 363.9400 1675.1350 364.2300 ;
    END
  END ahbsi_out[321]
  PIN ahbsi_out[320]
    DIRECTION OUTPUT ;
    USE SIGNAL ;
    PORT
      LAYER Metal2 ;
        RECT 1686.2650 363.9400 1686.3350 364.2300 ;
    END
  END ahbsi_out[320]
  PIN ahbsi_out[319]
    DIRECTION OUTPUT ;
    USE SIGNAL ;
    PORT
      LAYER Metal4 ;
        RECT 1686.2650 363.9400 1686.3350 364.2300 ;
    END
  END ahbsi_out[319]
  PIN ahbsi_out[318]
    DIRECTION OUTPUT ;
    USE SIGNAL ;
    PORT
      LAYER Metal6 ;
        RECT 1686.2650 363.9400 1686.3350 364.2300 ;
    END
  END ahbsi_out[318]
  PIN ahbsi_out[317]
    DIRECTION OUTPUT ;
    USE SIGNAL ;
    PORT
      LAYER Metal8 ;
        RECT 1686.2650 363.9400 1686.3350 364.2300 ;
    END
  END ahbsi_out[317]
  PIN ahbsi_out[316]
    DIRECTION OUTPUT ;
    USE SIGNAL ;
    PORT
      LAYER Metal2 ;
        RECT 1674.6650 363.9400 1674.7350 364.2300 ;
    END
  END ahbsi_out[316]
  PIN ahbsi_out[315]
    DIRECTION OUTPUT ;
    USE SIGNAL ;
    PORT
      LAYER Metal3 ;
        RECT 0.0000 334.8400 0.2900 334.9100 ;
    END
  END ahbsi_out[315]
  PIN ahbsi_out[314]
    DIRECTION OUTPUT ;
    USE SIGNAL ;
    PORT
      LAYER Metal5 ;
        RECT 0.0000 320.5900 0.2900 320.6600 ;
    END
  END ahbsi_out[314]
  PIN ahbsi_out[313]
    DIRECTION OUTPUT ;
    USE SIGNAL ;
    PORT
      LAYER Metal3 ;
        RECT 0.0000 325.7200 0.2900 325.7900 ;
    END
  END ahbsi_out[313]
  PIN ahbsi_out[312]
    DIRECTION OUTPUT ;
    USE SIGNAL ;
    PORT
      LAYER Metal5 ;
        RECT 0.0000 327.2400 0.2900 327.3100 ;
    END
  END ahbsi_out[312]
  PIN ahbsi_out[311]
    DIRECTION OUTPUT ;
    USE SIGNAL ;
    PORT
      LAYER Metal9 ;
        RECT 0.0000 326.4800 0.2900 326.5500 ;
    END
  END ahbsi_out[311]
  PIN ahbsi_out[310]
    DIRECTION OUTPUT ;
    USE SIGNAL ;
    PORT
      LAYER Metal9 ;
        RECT 0.0000 328.3800 0.2900 328.4500 ;
    END
  END ahbsi_out[310]
  PIN ahbsi_out[309]
    DIRECTION OUTPUT ;
    USE SIGNAL ;
    PORT
      LAYER Metal5 ;
        RECT 0.0000 331.9900 0.2900 332.0600 ;
    END
  END ahbsi_out[309]
  PIN ahbsi_out[308]
    DIRECTION OUTPUT ;
    USE SIGNAL ;
    PORT
      LAYER Metal5 ;
        RECT 0.0000 335.0300 0.2900 335.1000 ;
    END
  END ahbsi_out[308]
  PIN ahbsi_out[307]
    DIRECTION OUTPUT ;
    USE SIGNAL ;
    PORT
      LAYER Metal3 ;
        RECT 0.0000 336.1700 0.2900 336.2400 ;
    END
  END ahbsi_out[307]
  PIN ahbsi_out[306]
    DIRECTION OUTPUT ;
    USE SIGNAL ;
    PORT
      LAYER Metal5 ;
        RECT 0.0000 340.9200 0.2900 340.9900 ;
    END
  END ahbsi_out[306]
  PIN ahbsi_out[305]
    DIRECTION OUTPUT ;
    USE SIGNAL ;
    PORT
      LAYER Metal9 ;
        RECT 0.0000 340.1600 0.2900 340.2300 ;
    END
  END ahbsi_out[305]
  PIN ahbsi_out[304]
    DIRECTION OUTPUT ;
    USE SIGNAL ;
    PORT
      LAYER Metal4 ;
        RECT 1674.6650 363.9400 1674.7350 364.2300 ;
    END
  END ahbsi_out[304]
  PIN ahbsi_out[303]
    DIRECTION OUTPUT ;
    USE SIGNAL ;
    PORT
      LAYER Metal6 ;
        RECT 1674.6650 363.9400 1674.7350 364.2300 ;
    END
  END ahbsi_out[303]
  PIN ahbsi_out[302]
    DIRECTION OUTPUT ;
    USE SIGNAL ;
    PORT
      LAYER Metal2 ;
        RECT 72.8650 363.9400 72.9350 364.2300 ;
    END
  END ahbsi_out[302]
  PIN ahbsi_out[301]
    DIRECTION OUTPUT ;
    USE SIGNAL ;
    PORT
      LAYER Metal4 ;
        RECT 132.2650 363.9400 132.3350 364.2300 ;
    END
  END ahbsi_out[301]
  PIN ahbsi_out[300]
    DIRECTION OUTPUT ;
    USE SIGNAL ;
    PORT
      LAYER Metal4 ;
        RECT 133.8650 363.9400 133.9350 364.2300 ;
    END
  END ahbsi_out[300]
  PIN ahbsi_out[299]
    DIRECTION OUTPUT ;
    USE SIGNAL ;
    PORT
      LAYER Metal2 ;
        RECT 133.2650 363.9400 133.3350 364.2300 ;
    END
  END ahbsi_out[299]
  PIN ahbsi_out[298]
    DIRECTION OUTPUT ;
    USE SIGNAL ;
    PORT
      LAYER Metal2 ;
        RECT 132.2650 363.9400 132.3350 364.2300 ;
    END
  END ahbsi_out[298]
  PIN ahbsi_out[297]
    DIRECTION OUTPUT ;
    USE SIGNAL ;
    PORT
      LAYER Metal2 ;
        RECT 133.6650 363.9400 133.7350 364.2300 ;
    END
  END ahbsi_out[297]
  PIN ahbsi_out[296]
    DIRECTION OUTPUT ;
    USE SIGNAL ;
    PORT
      LAYER Metal2 ;
        RECT 1686.6650 363.9400 1686.7350 364.2300 ;
    END
  END ahbsi_out[296]
  PIN ahbsi_out[295]
    DIRECTION OUTPUT ;
    USE SIGNAL ;
    PORT
      LAYER Metal4 ;
        RECT 1686.6650 363.9400 1686.7350 364.2300 ;
    END
  END ahbsi_out[295]
  PIN ahbsi_out[294]
    DIRECTION OUTPUT ;
    USE SIGNAL ;
    PORT
      LAYER Metal6 ;
        RECT 1686.6650 363.9400 1686.7350 364.2300 ;
    END
  END ahbsi_out[294]
  PIN ahbsi_out[293]
    DIRECTION OUTPUT ;
    USE SIGNAL ;
    PORT
      LAYER Metal3 ;
        RECT 0.0000 257.3200 0.2900 257.3900 ;
    END
  END ahbsi_out[293]
  PIN ahbsi_out[292]
    DIRECTION OUTPUT ;
    USE SIGNAL ;
    PORT
      LAYER Metal5 ;
        RECT 0.0000 255.6100 0.2900 255.6800 ;
    END
  END ahbsi_out[292]
  PIN ahbsi_out[291]
    DIRECTION OUTPUT ;
    USE SIGNAL ;
    PORT
      LAYER Metal3 ;
        RECT 0.0000 250.4800 0.2900 250.5500 ;
    END
  END ahbsi_out[291]
  PIN ahbsi_out[290]
    DIRECTION OUTPUT ;
    USE SIGNAL ;
    PORT
      LAYER Metal9 ;
        RECT 0.0000 240.2200 0.2900 240.2900 ;
    END
  END ahbsi_out[290]
  PIN ahbsi_out[289]
    DIRECTION OUTPUT ;
    USE SIGNAL ;
    PORT
      LAYER Metal9 ;
        RECT 0.0000 229.9600 0.2900 230.0300 ;
    END
  END ahbsi_out[289]
  PIN ahbsi_out[288]
    DIRECTION OUTPUT ;
    USE SIGNAL ;
    PORT
      LAYER Metal5 ;
        RECT 0.0000 233.3800 0.2900 233.4500 ;
    END
  END ahbsi_out[288]
  PIN ahbsi_out[287]
    DIRECTION OUTPUT ;
    USE SIGNAL ;
    PORT
      LAYER Metal3 ;
        RECT 0.0000 233.3800 0.2900 233.4500 ;
    END
  END ahbsi_out[287]
  PIN ahbsi_out[286]
    DIRECTION OUTPUT ;
    USE SIGNAL ;
    PORT
      LAYER Metal5 ;
        RECT 0.0000 235.0900 0.2900 235.1600 ;
    END
  END ahbsi_out[286]
  PIN ahbsi_out[285]
    DIRECTION OUTPUT ;
    USE SIGNAL ;
    PORT
      LAYER Metal3 ;
        RECT 0.0000 231.6700 0.2900 231.7400 ;
    END
  END ahbsi_out[285]
  PIN ahbsi_out[284]
    DIRECTION OUTPUT ;
    USE SIGNAL ;
    PORT
      LAYER Metal5 ;
        RECT 0.0000 240.2200 0.2900 240.2900 ;
    END
  END ahbsi_out[284]
  PIN ahbsi_out[283]
    DIRECTION OUTPUT ;
    USE SIGNAL ;
    PORT
      LAYER Metal5 ;
        RECT 0.0000 229.9600 0.2900 230.0300 ;
    END
  END ahbsi_out[283]
  PIN ahbsi_out[282]
    DIRECTION OUTPUT ;
    USE SIGNAL ;
    PORT
      LAYER Metal5 ;
        RECT 0.0000 243.6400 0.2900 243.7100 ;
    END
  END ahbsi_out[282]
  PIN ahbsi_out[281]
    DIRECTION OUTPUT ;
    USE SIGNAL ;
    PORT
      LAYER Metal5 ;
        RECT 0.0000 245.3500 0.2900 245.4200 ;
    END
  END ahbsi_out[281]
  PIN ahbsi_out[280]
    DIRECTION OUTPUT ;
    USE SIGNAL ;
    PORT
      LAYER Metal5 ;
        RECT 0.0000 248.7700 0.2900 248.8400 ;
    END
  END ahbsi_out[280]
  PIN ahbsi_out[279]
    DIRECTION OUTPUT ;
    USE SIGNAL ;
    PORT
      LAYER Metal3 ;
        RECT 0.0000 235.0900 0.2900 235.1600 ;
    END
  END ahbsi_out[279]
  PIN ahbsi_out[278]
    DIRECTION OUTPUT ;
    USE SIGNAL ;
    PORT
      LAYER Metal5 ;
        RECT 0.0000 238.5100 0.2900 238.5800 ;
    END
  END ahbsi_out[278]
  PIN ahbsi_out[277]
    DIRECTION OUTPUT ;
    USE SIGNAL ;
    PORT
      LAYER Metal3 ;
        RECT 0.0000 238.5100 0.2900 238.5800 ;
    END
  END ahbsi_out[277]
  PIN ahbsi_out[276]
    DIRECTION OUTPUT ;
    USE SIGNAL ;
    PORT
      LAYER Metal3 ;
        RECT 0.0000 247.0600 0.2900 247.1300 ;
    END
  END ahbsi_out[276]
  PIN ahbsi_out[275]
    DIRECTION OUTPUT ;
    USE SIGNAL ;
    PORT
      LAYER Metal3 ;
        RECT 0.0000 240.2200 0.2900 240.2900 ;
    END
  END ahbsi_out[275]
  PIN ahbsi_out[274]
    DIRECTION OUTPUT ;
    USE SIGNAL ;
    PORT
      LAYER Metal3 ;
        RECT 0.0000 245.3500 0.2900 245.4200 ;
    END
  END ahbsi_out[274]
  PIN ahbsi_out[273]
    DIRECTION OUTPUT ;
    USE SIGNAL ;
    PORT
      LAYER Metal3 ;
        RECT 0.0000 243.6400 0.2900 243.7100 ;
    END
  END ahbsi_out[273]
  PIN ahbsi_out[272]
    DIRECTION OUTPUT ;
    USE SIGNAL ;
    PORT
      LAYER Metal3 ;
        RECT 0.0000 248.7700 0.2900 248.8400 ;
    END
  END ahbsi_out[272]
  PIN ahbsi_out[271]
    DIRECTION OUTPUT ;
    USE SIGNAL ;
    PORT
      LAYER Metal9 ;
        RECT 0.0000 238.7000 0.2900 238.7700 ;
    END
  END ahbsi_out[271]
  PIN ahbsi_out[270]
    DIRECTION OUTPUT ;
    USE SIGNAL ;
    PORT
      LAYER Metal9 ;
        RECT 0.0000 243.6400 0.2900 243.7100 ;
    END
  END ahbsi_out[270]
  PIN ahbsi_out[269]
    DIRECTION OUTPUT ;
    USE SIGNAL ;
    PORT
      LAYER Metal3 ;
        RECT 0.0000 252.1900 0.2900 252.2600 ;
    END
  END ahbsi_out[269]
  PIN ahbsi_out[268]
    DIRECTION OUTPUT ;
    USE SIGNAL ;
    PORT
      LAYER Metal3 ;
        RECT 0.0000 264.1600 0.2900 264.2300 ;
    END
  END ahbsi_out[268]
  PIN ahbsi_out[267]
    DIRECTION OUTPUT ;
    USE SIGNAL ;
    PORT
      LAYER Metal3 ;
        RECT 0.0000 288.4800 0.2900 288.5500 ;
    END
  END ahbsi_out[267]
  PIN ahbsi_out[266]
    DIRECTION OUTPUT ;
    USE SIGNAL ;
    PORT
      LAYER Metal5 ;
        RECT 0.0000 257.3200 0.2900 257.3900 ;
    END
  END ahbsi_out[266]
  PIN ahbsi_out[265]
    DIRECTION OUTPUT ;
    USE SIGNAL ;
    PORT
      LAYER Metal3 ;
        RECT 0.0000 255.6100 0.2900 255.6800 ;
    END
  END ahbsi_out[265]
  PIN ahbsi_out[264]
    DIRECTION OUTPUT ;
    USE SIGNAL ;
    PORT
      LAYER Metal9 ;
        RECT 0.0000 277.8400 0.2900 277.9100 ;
    END
  END ahbsi_out[264]
  PIN ahbsi_out[263]
    DIRECTION OUTPUT ;
    USE SIGNAL ;
    PORT
      LAYER Metal3 ;
        RECT 0.0000 276.1300 0.2900 276.2000 ;
    END
  END ahbsi_out[263]
  PIN ahbsi_out[262]
    DIRECTION OUTPUT ;
    USE SIGNAL ;
    PORT
      LAYER Metal5 ;
        RECT 0.0000 277.8400 0.2900 277.9100 ;
    END
  END ahbsi_out[262]
  PIN ahbsi_out[261]
    DIRECTION OUTPUT ;
    USE SIGNAL ;
    PORT
      LAYER Metal8 ;
        RECT 1686.6650 363.9400 1686.7350 364.2300 ;
    END
  END ahbsi_out[261]
  PIN ahbsi_out[260]
    DIRECTION OUTPUT ;
    USE SIGNAL ;
    PORT
      LAYER Metal2 ;
        RECT 1674.2650 363.9400 1674.3350 364.2300 ;
    END
  END ahbsi_out[260]
  PIN ahbsi_out[259]
    DIRECTION OUTPUT ;
    USE SIGNAL ;
    PORT
      LAYER Metal4 ;
        RECT 1674.2650 363.9400 1674.3350 364.2300 ;
    END
  END ahbsi_out[259]
  PIN ahbsi_out[258]
    DIRECTION OUTPUT ;
    USE SIGNAL ;
    PORT
      LAYER Metal6 ;
        RECT 1674.2650 363.9400 1674.3350 364.2300 ;
    END
  END ahbsi_out[258]
  PIN ahbsi_out[257]
    DIRECTION OUTPUT ;
    USE SIGNAL ;
    PORT
      LAYER Metal2 ;
        RECT 91.0650 363.9400 91.1350 364.2300 ;
    END
  END ahbsi_out[257]
  PIN ahbsi_out[256]
    DIRECTION OUTPUT ;
    USE SIGNAL ;
    PORT
      LAYER Metal2 ;
        RECT 1687.0650 363.9400 1687.1350 364.2300 ;
    END
  END ahbsi_out[256]
  PIN ahbsi_out[255]
    DIRECTION OUTPUT ;
    USE SIGNAL ;
    PORT
      LAYER Metal4 ;
        RECT 1687.0650 363.9400 1687.1350 364.2300 ;
    END
  END ahbsi_out[255]
  PIN ahbsi_out[254]
    DIRECTION OUTPUT ;
    USE SIGNAL ;
    PORT
      LAYER Metal6 ;
        RECT 1687.0650 363.9400 1687.1350 364.2300 ;
    END
  END ahbsi_out[254]
  PIN ahbsi_out[253]
    DIRECTION OUTPUT ;
    USE SIGNAL ;
    PORT
      LAYER Metal8 ;
        RECT 1687.0650 363.9400 1687.1350 364.2300 ;
    END
  END ahbsi_out[253]
  PIN ahbsi_out[252]
    DIRECTION OUTPUT ;
    USE SIGNAL ;
    PORT
      LAYER Metal2 ;
        RECT 1673.8650 363.9400 1673.9350 364.2300 ;
    END
  END ahbsi_out[252]
  PIN ahbsi_out[251]
    DIRECTION OUTPUT ;
    USE SIGNAL ;
    PORT
      LAYER Metal6 ;
        RECT 133.8650 363.9400 133.9350 364.2300 ;
    END
  END ahbsi_out[251]
  PIN ahbsi_out[250]
    DIRECTION OUTPUT ;
    USE SIGNAL ;
    PORT
      LAYER Metal4 ;
        RECT 1673.8650 363.9400 1673.9350 364.2300 ;
    END
  END ahbsi_out[250]
  PIN ahbsi_out[249]
    DIRECTION OUTPUT ;
    USE SIGNAL ;
    PORT
      LAYER Metal6 ;
        RECT 1673.8650 363.9400 1673.9350 364.2300 ;
    END
  END ahbsi_out[249]
  PIN ahbsi_out[248]
    DIRECTION OUTPUT ;
    USE SIGNAL ;
    PORT
      LAYER Metal2 ;
        RECT 1687.4650 363.9400 1687.5350 364.2300 ;
    END
  END ahbsi_out[248]
  PIN ahbsi_out[247]
    DIRECTION OUTPUT ;
    USE SIGNAL ;
    PORT
      LAYER Metal4 ;
        RECT 1687.4650 363.9400 1687.5350 364.2300 ;
    END
  END ahbsi_out[247]
  PIN ahbsi_out[246]
    DIRECTION OUTPUT ;
    USE SIGNAL ;
    PORT
      LAYER Metal6 ;
        RECT 1687.4650 363.9400 1687.5350 364.2300 ;
    END
  END ahbsi_out[246]
  PIN ahbsi_out[245]
    DIRECTION OUTPUT ;
    USE SIGNAL ;
    PORT
      LAYER Metal8 ;
        RECT 1687.4650 363.9400 1687.5350 364.2300 ;
    END
  END ahbsi_out[245]
  PIN ahbsi_out[244]
    DIRECTION OUTPUT ;
    USE SIGNAL ;
    PORT
      LAYER Metal2 ;
        RECT 1673.4650 363.9400 1673.5350 364.2300 ;
    END
  END ahbsi_out[244]
  PIN ahbsi_out[243]
    DIRECTION OUTPUT ;
    USE SIGNAL ;
    PORT
      LAYER Metal4 ;
        RECT 1673.4650 363.9400 1673.5350 364.2300 ;
    END
  END ahbsi_out[243]
  PIN ahbsi_out[242]
    DIRECTION OUTPUT ;
    USE SIGNAL ;
    PORT
      LAYER Metal6 ;
        RECT 1673.4650 363.9400 1673.5350 364.2300 ;
    END
  END ahbsi_out[242]
  PIN ahbsi_out[241]
    DIRECTION OUTPUT ;
    USE SIGNAL ;
    PORT
      LAYER Metal2 ;
        RECT 1687.8650 363.9400 1687.9350 364.2300 ;
    END
  END ahbsi_out[241]
  PIN ahbsi_out[240]
    DIRECTION OUTPUT ;
    USE SIGNAL ;
    PORT
      LAYER Metal4 ;
        RECT 1687.8650 363.9400 1687.9350 364.2300 ;
    END
  END ahbsi_out[240]
  PIN ahbsi_out[239]
    DIRECTION OUTPUT ;
    USE SIGNAL ;
    PORT
      LAYER Metal6 ;
        RECT 1687.8650 363.9400 1687.9350 364.2300 ;
    END
  END ahbsi_out[239]
  PIN ahbsi_out[238]
    DIRECTION OUTPUT ;
    USE SIGNAL ;
    PORT
      LAYER Metal8 ;
        RECT 1687.8650 363.9400 1687.9350 364.2300 ;
    END
  END ahbsi_out[238]
  PIN ahbsi_out[237]
    DIRECTION OUTPUT ;
    USE SIGNAL ;
    PORT
      LAYER Metal4 ;
        RECT 101.6650 363.9400 101.7350 364.2300 ;
    END
  END ahbsi_out[237]
  PIN ahbsi_out[236]
    DIRECTION OUTPUT ;
    USE SIGNAL ;
    PORT
      LAYER Metal2 ;
        RECT 108.0650 363.9400 108.1350 364.2300 ;
    END
  END ahbsi_out[236]
  PIN ahbsi_out[235]
    DIRECTION OUTPUT ;
    USE SIGNAL ;
    PORT
      LAYER Metal2 ;
        RECT 105.0650 363.9400 105.1350 364.2300 ;
    END
  END ahbsi_out[235]
  PIN ahbsi_out[234]
    DIRECTION OUTPUT ;
    USE SIGNAL ;
    PORT
      LAYER Metal4 ;
        RECT 107.4650 363.9400 107.5350 364.2300 ;
    END
  END ahbsi_out[234]
  PIN ahbsi_out[233]
    DIRECTION OUTPUT ;
    USE SIGNAL ;
    PORT
      LAYER Metal2 ;
        RECT 101.8650 363.9400 101.9350 364.2300 ;
    END
  END ahbsi_out[233]
  PIN ahbsi_out[232]
    DIRECTION OUTPUT ;
    USE SIGNAL ;
    PORT
      LAYER Metal2 ;
        RECT 98.4650 363.9400 98.5350 364.2300 ;
    END
  END ahbsi_out[232]
  PIN ahbsi_out[231]
    DIRECTION OUTPUT ;
    USE SIGNAL ;
    PORT
      LAYER Metal2 ;
        RECT 97.8650 363.9400 97.9350 364.2300 ;
    END
  END ahbsi_out[231]
  PIN ahbsi_out[230]
    DIRECTION OUTPUT ;
    USE SIGNAL ;
    PORT
      LAYER Metal2 ;
        RECT 92.4650 363.9400 92.5350 364.2300 ;
    END
  END ahbsi_out[230]
  PIN ahbsi_out[229]
    DIRECTION OUTPUT ;
    USE SIGNAL ;
    PORT
      LAYER Metal2 ;
        RECT 88.6650 363.9400 88.7350 364.2300 ;
    END
  END ahbsi_out[229]
  PIN ahbsi_out[228]
    DIRECTION OUTPUT ;
    USE SIGNAL ;
    PORT
      LAYER Metal2 ;
        RECT 84.4650 363.9400 84.5350 364.2300 ;
    END
  END ahbsi_out[228]
  PIN ahbsi_out[227]
    DIRECTION OUTPUT ;
    USE SIGNAL ;
    PORT
      LAYER Metal4 ;
        RECT 82.2650 363.9400 82.3350 364.2300 ;
    END
  END ahbsi_out[227]
  PIN ahbsi_out[226]
    DIRECTION OUTPUT ;
    USE SIGNAL ;
    PORT
      LAYER Metal2 ;
        RECT 81.4650 363.9400 81.5350 364.2300 ;
    END
  END ahbsi_out[226]
  PIN ahbsi_out[225]
    DIRECTION OUTPUT ;
    USE SIGNAL ;
    PORT
      LAYER Metal2 ;
        RECT 80.8650 363.9400 80.9350 364.2300 ;
    END
  END ahbsi_out[225]
  PIN ahbsi_out[224]
    DIRECTION OUTPUT ;
    USE SIGNAL ;
    PORT
      LAYER Metal2 ;
        RECT 79.8650 363.9400 79.9350 364.2300 ;
    END
  END ahbsi_out[224]
  PIN ahbsi_out[223]
    DIRECTION OUTPUT ;
    USE SIGNAL ;
    PORT
      LAYER Metal2 ;
        RECT 82.2650 363.9400 82.3350 364.2300 ;
    END
  END ahbsi_out[223]
  PIN ahbsi_out[222]
    DIRECTION OUTPUT ;
    USE SIGNAL ;
    PORT
      LAYER Metal2 ;
        RECT 91.8650 363.9400 91.9350 364.2300 ;
    END
  END ahbsi_out[222]
  PIN ahbsi_out[221]
    DIRECTION OUTPUT ;
    USE SIGNAL ;
    PORT
      LAYER Metal4 ;
        RECT 97.2650 363.9400 97.3350 364.2300 ;
    END
  END ahbsi_out[221]
  PIN ahbsi_out[220]
    DIRECTION OUTPUT ;
    USE SIGNAL ;
    PORT
      LAYER Metal2 ;
        RECT 1673.0650 363.9400 1673.1350 364.2300 ;
    END
  END ahbsi_out[220]
  PIN ahbsi_out[219]
    DIRECTION OUTPUT ;
    USE SIGNAL ;
    PORT
      LAYER Metal4 ;
        RECT 1673.0650 363.9400 1673.1350 364.2300 ;
    END
  END ahbsi_out[219]
  PIN ahbsi_out[218]
    DIRECTION OUTPUT ;
    USE SIGNAL ;
    PORT
      LAYER Metal4 ;
        RECT 128.0650 363.9400 128.1350 364.2300 ;
    END
  END ahbsi_out[218]
  PIN ahbsi_out[217]
    DIRECTION OUTPUT ;
    USE SIGNAL ;
    PORT
      LAYER Metal4 ;
        RECT 178.0650 363.9400 178.1350 364.2300 ;
    END
  END ahbsi_out[217]
  PIN ahbsi_out[216]
    DIRECTION OUTPUT ;
    USE SIGNAL ;
    PORT
      LAYER Metal4 ;
        RECT 184.6650 363.9400 184.7350 364.2300 ;
    END
  END ahbsi_out[216]
  PIN ahbsi_out[215]
    DIRECTION OUTPUT ;
    USE SIGNAL ;
    PORT
      LAYER Metal4 ;
        RECT 184.2650 363.9400 184.3350 364.2300 ;
    END
  END ahbsi_out[215]
  PIN ahbsi_out[214]
    DIRECTION OUTPUT ;
    USE SIGNAL ;
    PORT
      LAYER Metal2 ;
        RECT 178.2650 363.9400 178.3350 364.2300 ;
    END
  END ahbsi_out[214]
  PIN ahbsi_out[213]
    DIRECTION OUTPUT ;
    USE SIGNAL ;
    PORT
      LAYER Metal2 ;
        RECT 184.4650 363.9400 184.5350 364.2300 ;
    END
  END ahbsi_out[213]
  PIN ahbsi_out[212]
    DIRECTION OUTPUT ;
    USE SIGNAL ;
    PORT
      LAYER Metal6 ;
        RECT 1673.0650 363.9400 1673.1350 364.2300 ;
    END
  END ahbsi_out[212]
  PIN ahbsi_out[211]
    DIRECTION OUTPUT ;
    USE SIGNAL ;
    PORT
      LAYER Metal2 ;
        RECT 1688.2650 363.9400 1688.3350 364.2300 ;
    END
  END ahbsi_out[211]
  PIN ahbsi_out[210]
    DIRECTION OUTPUT ;
    USE SIGNAL ;
    PORT
      LAYER Metal4 ;
        RECT 1688.2650 363.9400 1688.3350 364.2300 ;
    END
  END ahbsi_out[210]
  PIN ahbsi_out[209]
    DIRECTION OUTPUT ;
    USE SIGNAL ;
    PORT
      LAYER Metal2 ;
        RECT 233.4650 363.9400 233.5350 364.2300 ;
    END
  END ahbsi_out[209]
  PIN ahbsi_out[208]
    DIRECTION OUTPUT ;
    USE SIGNAL ;
    PORT
      LAYER Metal2 ;
        RECT 232.6650 363.9400 232.7350 364.2300 ;
    END
  END ahbsi_out[208]
  PIN ahbsi_out[207]
    DIRECTION OUTPUT ;
    USE SIGNAL ;
    PORT
      LAYER Metal2 ;
        RECT 229.2650 363.9400 229.3350 364.2300 ;
    END
  END ahbsi_out[207]
  PIN ahbsi_out[206]
    DIRECTION OUTPUT ;
    USE SIGNAL ;
    PORT
      LAYER Metal2 ;
        RECT 228.6650 363.9400 228.7350 364.2300 ;
    END
  END ahbsi_out[206]
  PIN ahbsi_out[205]
    DIRECTION OUTPUT ;
    USE SIGNAL ;
    PORT
      LAYER Metal2 ;
        RECT 226.6650 363.9400 226.7350 364.2300 ;
    END
  END ahbsi_out[205]
  PIN ahbsi_out[204]
    DIRECTION OUTPUT ;
    USE SIGNAL ;
    PORT
      LAYER Metal2 ;
        RECT 225.6650 363.9400 225.7350 364.2300 ;
    END
  END ahbsi_out[204]
  PIN ahbsi_out[203]
    DIRECTION OUTPUT ;
    USE SIGNAL ;
    PORT
      LAYER Metal2 ;
        RECT 225.0650 363.9400 225.1350 364.2300 ;
    END
  END ahbsi_out[203]
  PIN ahbsi_out[202]
    DIRECTION OUTPUT ;
    USE SIGNAL ;
    PORT
      LAYER Metal2 ;
        RECT 227.6650 363.9400 227.7350 364.2300 ;
    END
  END ahbsi_out[202]
  PIN ahbsi_out[201]
    DIRECTION OUTPUT ;
    USE SIGNAL ;
    PORT
      LAYER Metal2 ;
        RECT 231.8650 363.9400 231.9350 364.2300 ;
    END
  END ahbsi_out[201]
  PIN ahbsi_out[200]
    DIRECTION OUTPUT ;
    USE SIGNAL ;
    PORT
      LAYER Metal4 ;
        RECT 233.6650 363.9400 233.7350 364.2300 ;
    END
  END ahbsi_out[200]
  PIN ahbsi_out[199]
    DIRECTION OUTPUT ;
    USE SIGNAL ;
    PORT
      LAYER Metal4 ;
        RECT 237.2650 363.9400 237.3350 364.2300 ;
    END
  END ahbsi_out[199]
  PIN ahbsi_out[198]
    DIRECTION OUTPUT ;
    USE SIGNAL ;
    PORT
      LAYER Metal4 ;
        RECT 239.6650 363.9400 239.7350 364.2300 ;
    END
  END ahbsi_out[198]
  PIN ahbsi_out[197]
    DIRECTION OUTPUT ;
    USE SIGNAL ;
    PORT
      LAYER Metal2 ;
        RECT 239.8650 363.9400 239.9350 364.2300 ;
    END
  END ahbsi_out[197]
  PIN ahbsi_out[196]
    DIRECTION OUTPUT ;
    USE SIGNAL ;
    PORT
      LAYER Metal2 ;
        RECT 237.4650 363.9400 237.5350 364.2300 ;
    END
  END ahbsi_out[196]
  PIN ahbsi_out[195]
    DIRECTION OUTPUT ;
    USE SIGNAL ;
    PORT
      LAYER Metal4 ;
        RECT 236.0650 363.9400 236.1350 364.2300 ;
    END
  END ahbsi_out[195]
  PIN ahbsi_out[194]
    DIRECTION OUTPUT ;
    USE SIGNAL ;
    PORT
      LAYER Metal2 ;
        RECT 235.8650 363.9400 235.9350 364.2300 ;
    END
  END ahbsi_out[194]
  PIN ahbsi_out[193]
    DIRECTION OUTPUT ;
    USE SIGNAL ;
    PORT
      LAYER Metal2 ;
        RECT 236.8650 363.9400 236.9350 364.2300 ;
    END
  END ahbsi_out[193]
  PIN ahbsi_out[192]
    DIRECTION OUTPUT ;
    USE SIGNAL ;
    PORT
      LAYER Metal2 ;
        RECT 237.8650 363.9400 237.9350 364.2300 ;
    END
  END ahbsi_out[192]
  PIN ahbsi_out[191]
    DIRECTION OUTPUT ;
    USE SIGNAL ;
    PORT
      LAYER Metal2 ;
        RECT 238.2650 363.9400 238.3350 364.2300 ;
    END
  END ahbsi_out[191]
  PIN ahbsi_out[190]
    DIRECTION OUTPUT ;
    USE SIGNAL ;
    PORT
      LAYER Metal2 ;
        RECT 236.2650 363.9400 236.3350 364.2300 ;
    END
  END ahbsi_out[190]
  PIN ahbsi_out[189]
    DIRECTION OUTPUT ;
    USE SIGNAL ;
    PORT
      LAYER Metal2 ;
        RECT 238.8650 363.9400 238.9350 364.2300 ;
    END
  END ahbsi_out[189]
  PIN ahbsi_out[188]
    DIRECTION OUTPUT ;
    USE SIGNAL ;
    PORT
      LAYER Metal2 ;
        RECT 235.0650 363.9400 235.1350 364.2300 ;
    END
  END ahbsi_out[188]
  PIN ahbsi_out[187]
    DIRECTION OUTPUT ;
    USE SIGNAL ;
    PORT
      LAYER Metal6 ;
        RECT 233.8650 363.9400 233.9350 364.2300 ;
    END
  END ahbsi_out[187]
  PIN ahbsi_out[186]
    DIRECTION OUTPUT ;
    USE SIGNAL ;
    PORT
      LAYER Metal4 ;
        RECT 234.0650 363.9400 234.1350 364.2300 ;
    END
  END ahbsi_out[186]
  PIN ahbsi_out[185]
    DIRECTION OUTPUT ;
    USE SIGNAL ;
    PORT
      LAYER Metal2 ;
        RECT 230.8650 363.9400 230.9350 364.2300 ;
    END
  END ahbsi_out[185]
  PIN ahbsi_out[184]
    DIRECTION OUTPUT ;
    USE SIGNAL ;
    PORT
      LAYER Metal2 ;
        RECT 224.6650 363.9400 224.7350 364.2300 ;
    END
  END ahbsi_out[184]
  PIN ahbsi_out[183]
    DIRECTION OUTPUT ;
    USE SIGNAL ;
    PORT
      LAYER Metal2 ;
        RECT 222.6650 363.9400 222.7350 364.2300 ;
    END
  END ahbsi_out[183]
  PIN ahbsi_out[182]
    DIRECTION OUTPUT ;
    USE SIGNAL ;
    PORT
      LAYER Metal2 ;
        RECT 220.4650 363.9400 220.5350 364.2300 ;
    END
  END ahbsi_out[182]
  PIN ahbsi_out[181]
    DIRECTION OUTPUT ;
    USE SIGNAL ;
    PORT
      LAYER Metal2 ;
        RECT 221.6650 363.9400 221.7350 364.2300 ;
    END
  END ahbsi_out[181]
  PIN ahbsi_out[180]
    DIRECTION OUTPUT ;
    USE SIGNAL ;
    PORT
      LAYER Metal2 ;
        RECT 211.4650 363.9400 211.5350 364.2300 ;
    END
  END ahbsi_out[180]
  PIN ahbsi_out[179]
    DIRECTION OUTPUT ;
    USE SIGNAL ;
    PORT
      LAYER Metal2 ;
        RECT 205.4650 363.9400 205.5350 364.2300 ;
    END
  END ahbsi_out[179]
  PIN ahbsi_out[178]
    DIRECTION OUTPUT ;
    USE SIGNAL ;
    PORT
      LAYER Metal2 ;
        RECT 137.2650 363.9400 137.3350 364.2300 ;
    END
  END ahbsi_out[178]
  PIN ahbsi_out[177]
    DIRECTION OUTPUT ;
    USE SIGNAL ;
    PORT
      LAYER Metal6 ;
        RECT 1688.2650 363.9400 1688.3350 364.2300 ;
    END
  END ahbsi_out[177]
  PIN ahbsi_out[176]
    DIRECTION OUTPUT ;
    USE SIGNAL ;
    PORT
      LAYER Metal8 ;
        RECT 1688.2650 363.9400 1688.3350 364.2300 ;
    END
  END ahbsi_out[176]
  PIN ahbsi_out[175]
    DIRECTION OUTPUT ;
    USE SIGNAL ;
    PORT
      LAYER Metal2 ;
        RECT 1672.6650 363.9400 1672.7350 364.2300 ;
    END
  END ahbsi_out[175]
  PIN ahbsi_out[174]
    DIRECTION OUTPUT ;
    USE SIGNAL ;
    PORT
      LAYER Metal4 ;
        RECT 1672.6650 363.9400 1672.7350 364.2300 ;
    END
  END ahbsi_out[174]
  PIN ahbsi_out[173]
    DIRECTION OUTPUT ;
    USE SIGNAL ;
    PORT
      LAYER Metal2 ;
        RECT 146.0650 363.9400 146.1350 364.2300 ;
    END
  END ahbsi_out[173]
  PIN ahbsi_out[172]
    DIRECTION OUTPUT ;
    USE SIGNAL ;
    PORT
      LAYER Metal6 ;
        RECT 1672.6650 363.9400 1672.7350 364.2300 ;
    END
  END ahbsi_out[172]
  PIN ahbsi_out[171]
    DIRECTION OUTPUT ;
    USE SIGNAL ;
    PORT
      LAYER Metal2 ;
        RECT 1688.6650 363.9400 1688.7350 364.2300 ;
    END
  END ahbsi_out[171]
  PIN ahbsi_out[170]
    DIRECTION OUTPUT ;
    USE SIGNAL ;
    PORT
      LAYER Metal4 ;
        RECT 1688.6650 363.9400 1688.7350 364.2300 ;
    END
  END ahbsi_out[170]
  PIN ahbsi_out[169]
    DIRECTION OUTPUT ;
    USE SIGNAL ;
    PORT
      LAYER Metal6 ;
        RECT 1688.6650 363.9400 1688.7350 364.2300 ;
    END
  END ahbsi_out[169]
  PIN ahbsi_out[168]
    DIRECTION OUTPUT ;
    USE SIGNAL ;
    PORT
      LAYER Metal8 ;
        RECT 1688.6650 363.9400 1688.7350 364.2300 ;
    END
  END ahbsi_out[168]
  PIN ahbsi_out[167]
    DIRECTION OUTPUT ;
    USE SIGNAL ;
    PORT
      LAYER Metal5 ;
        RECT 0.0000 331.6100 0.2900 331.6800 ;
    END
  END ahbsi_out[167]
  PIN ahbsi_out[166]
    DIRECTION OUTPUT ;
    USE SIGNAL ;
    PORT
      LAYER Metal2 ;
        RECT 1672.2650 363.9400 1672.3350 364.2300 ;
    END
  END ahbsi_out[166]
  PIN ahbsi_out[165]
    DIRECTION OUTPUT ;
    USE SIGNAL ;
    PORT
      LAYER Metal4 ;
        RECT 1672.2650 363.9400 1672.3350 364.2300 ;
    END
  END ahbsi_out[165]
  PIN ahbsi_out[164]
    DIRECTION OUTPUT ;
    USE SIGNAL ;
    PORT
      LAYER Metal6 ;
        RECT 1672.2650 363.9400 1672.3350 364.2300 ;
    END
  END ahbsi_out[164]
  PIN ahbsi_out[163]
    DIRECTION OUTPUT ;
    USE SIGNAL ;
    PORT
      LAYER Metal2 ;
        RECT 1689.0650 363.9400 1689.1350 364.2300 ;
    END
  END ahbsi_out[163]
  PIN ahbsi_out[162]
    DIRECTION OUTPUT ;
    USE SIGNAL ;
    PORT
      LAYER Metal4 ;
        RECT 1689.0650 363.9400 1689.1350 364.2300 ;
    END
  END ahbsi_out[162]
  PIN ahbsi_out[161]
    DIRECTION OUTPUT ;
    USE SIGNAL ;
    PORT
      LAYER Metal6 ;
        RECT 1689.0650 363.9400 1689.1350 364.2300 ;
    END
  END ahbsi_out[161]
  PIN ahbsi_out[160]
    DIRECTION OUTPUT ;
    USE SIGNAL ;
    PORT
      LAYER Metal8 ;
        RECT 1689.0650 363.9400 1689.1350 364.2300 ;
    END
  END ahbsi_out[160]
  PIN ahbsi_out[159]
    DIRECTION OUTPUT ;
    USE SIGNAL ;
    PORT
      LAYER Metal2 ;
        RECT 1671.8650 363.9400 1671.9350 364.2300 ;
    END
  END ahbsi_out[159]
  PIN ahbsi_out[158]
    DIRECTION OUTPUT ;
    USE SIGNAL ;
    PORT
      LAYER Metal4 ;
        RECT 1671.8650 363.9400 1671.9350 364.2300 ;
    END
  END ahbsi_out[158]
  PIN ahbsi_out[157]
    DIRECTION OUTPUT ;
    USE SIGNAL ;
    PORT
      LAYER Metal6 ;
        RECT 1671.8650 363.9400 1671.9350 364.2300 ;
    END
  END ahbsi_out[157]
  PIN ahbsi_out[156]
    DIRECTION OUTPUT ;
    USE SIGNAL ;
    PORT
      LAYER Metal2 ;
        RECT 1689.4650 363.9400 1689.5350 364.2300 ;
    END
  END ahbsi_out[156]
  PIN ahbsi_out[155]
    DIRECTION OUTPUT ;
    USE SIGNAL ;
    PORT
      LAYER Metal4 ;
        RECT 1689.4650 363.9400 1689.5350 364.2300 ;
    END
  END ahbsi_out[155]
  PIN ahbsi_out[154]
    DIRECTION OUTPUT ;
    USE SIGNAL ;
    PORT
      LAYER Metal6 ;
        RECT 1689.4650 363.9400 1689.5350 364.2300 ;
    END
  END ahbsi_out[154]
  PIN ahbsi_out[153]
    DIRECTION OUTPUT ;
    USE SIGNAL ;
    PORT
      LAYER Metal8 ;
        RECT 1689.4650 363.9400 1689.5350 364.2300 ;
    END
  END ahbsi_out[153]
  PIN ahbsi_out[152]
    DIRECTION OUTPUT ;
    USE SIGNAL ;
    PORT
      LAYER Metal2 ;
        RECT 1671.4650 363.9400 1671.5350 364.2300 ;
    END
  END ahbsi_out[152]
  PIN ahbsi_out[151]
    DIRECTION OUTPUT ;
    USE SIGNAL ;
    PORT
      LAYER Metal4 ;
        RECT 1671.4650 363.9400 1671.5350 364.2300 ;
    END
  END ahbsi_out[151]
  PIN ahbsi_out[150]
    DIRECTION OUTPUT ;
    USE SIGNAL ;
    PORT
      LAYER Metal6 ;
        RECT 1671.4650 363.9400 1671.5350 364.2300 ;
    END
  END ahbsi_out[150]
  PIN ahbsi_out[149]
    DIRECTION OUTPUT ;
    USE SIGNAL ;
    PORT
      LAYER Metal2 ;
        RECT 1689.8650 363.9400 1689.9350 364.2300 ;
    END
  END ahbsi_out[149]
  PIN ahbsi_out[148]
    DIRECTION OUTPUT ;
    USE SIGNAL ;
    PORT
      LAYER Metal4 ;
        RECT 1689.8650 363.9400 1689.9350 364.2300 ;
    END
  END ahbsi_out[148]
  PIN ahbsi_out[147]
    DIRECTION OUTPUT ;
    USE SIGNAL ;
    PORT
      LAYER Metal6 ;
        RECT 1689.8650 363.9400 1689.9350 364.2300 ;
    END
  END ahbsi_out[147]
  PIN ahbsi_out[146]
    DIRECTION OUTPUT ;
    USE SIGNAL ;
    PORT
      LAYER Metal3 ;
        RECT 0.0000 356.8800 0.2900 356.9500 ;
    END
  END ahbsi_out[146]
  PIN ahbsi_out[145]
    DIRECTION OUTPUT ;
    USE SIGNAL ;
    PORT
      LAYER Metal5 ;
        RECT 0.0000 357.8300 0.2900 357.9000 ;
    END
  END ahbsi_out[145]
  PIN ahbsi_out[144]
    DIRECTION OUTPUT ;
    USE SIGNAL ;
    PORT
      LAYER Metal9 ;
        RECT 0.0000 358.7800 0.2900 358.8500 ;
    END
  END ahbsi_out[144]
  PIN ahbsi_out[143]
    DIRECTION OUTPUT ;
    USE SIGNAL ;
    PORT
      LAYER Metal4 ;
        RECT 48.0650 363.9400 48.1350 364.2300 ;
    END
  END ahbsi_out[143]
  PIN ahbsi_out[142]
    DIRECTION OUTPUT ;
    USE SIGNAL ;
    PORT
      LAYER Metal5 ;
        RECT 0.0000 358.7800 0.2900 358.8500 ;
    END
  END ahbsi_out[142]
  PIN ahbsi_out[141]
    DIRECTION OUTPUT ;
    USE SIGNAL ;
    PORT
      LAYER Metal9 ;
        RECT 0.0000 353.0800 0.2900 353.1500 ;
    END
  END ahbsi_out[141]
  PIN ahbsi_out[140]
    DIRECTION OUTPUT ;
    USE SIGNAL ;
    PORT
      LAYER Metal3 ;
        RECT 0.0000 358.0200 0.2900 358.0900 ;
    END
  END ahbsi_out[140]
  PIN ahbsi_out[139]
    DIRECTION OUTPUT ;
    USE SIGNAL ;
    PORT
      LAYER Metal2 ;
        RECT 43.2650 363.9400 43.3350 364.2300 ;
    END
  END ahbsi_out[139]
  PIN ahbsi_out[138]
    DIRECTION OUTPUT ;
    USE SIGNAL ;
    PORT
      LAYER Metal5 ;
        RECT 0.0000 358.4000 0.2900 358.4700 ;
    END
  END ahbsi_out[138]
  PIN ahbsi_out[137]
    DIRECTION OUTPUT ;
    USE SIGNAL ;
    PORT
      LAYER Metal5 ;
        RECT 0.0000 339.2100 0.2900 339.2800 ;
    END
  END ahbsi_out[137]
  PIN ahbsi_out[136]
    DIRECTION OUTPUT ;
    USE SIGNAL ;
    PORT
      LAYER Metal8 ;
        RECT 1689.8650 363.9400 1689.9350 364.2300 ;
    END
  END ahbsi_out[136]
  PIN ahbsi_out[135]
    DIRECTION OUTPUT ;
    USE SIGNAL ;
    PORT
      LAYER Metal2 ;
        RECT 1671.0650 363.9400 1671.1350 364.2300 ;
    END
  END ahbsi_out[135]
  PIN ahbsi_out[134]
    DIRECTION OUTPUT ;
    USE SIGNAL ;
    PORT
      LAYER Metal3 ;
        RECT 0.0000 323.2500 0.2900 323.3200 ;
    END
  END ahbsi_out[134]
  PIN ahbsi_out[133]
    DIRECTION OUTPUT ;
    USE SIGNAL ;
    PORT
      LAYER Metal3 ;
        RECT 0.0000 345.6700 0.2900 345.7400 ;
    END
  END ahbsi_out[133]
  PIN ahbsi_out[132]
    DIRECTION OUTPUT ;
    USE SIGNAL ;
    PORT
      LAYER Metal3 ;
        RECT 0.0000 343.3900 0.2900 343.4600 ;
    END
  END ahbsi_out[132]
  PIN ahbsi_out[131]
    DIRECTION OUTPUT ;
    USE SIGNAL ;
    PORT
      LAYER Metal2 ;
        RECT 50.2650 363.9400 50.3350 364.2300 ;
    END
  END ahbsi_out[131]
  PIN ahbsi_out[130]
    DIRECTION OUTPUT ;
    USE SIGNAL ;
    PORT
      LAYER Metal5 ;
        RECT 0.0000 355.1700 0.2900 355.2400 ;
    END
  END ahbsi_out[130]
  PIN ahbsi_out[129]
    DIRECTION OUTPUT ;
    USE SIGNAL ;
    PORT
      LAYER Metal9 ;
        RECT 0.0000 355.3600 0.2900 355.4300 ;
    END
  END ahbsi_out[129]
  PIN ahbsi_out[128]
    DIRECTION OUTPUT ;
    USE SIGNAL ;
    PORT
      LAYER Metal3 ;
        RECT 0.0000 353.4600 0.2900 353.5300 ;
    END
  END ahbsi_out[128]
  PIN ahbsi_out[127]
    DIRECTION OUTPUT ;
    USE SIGNAL ;
    PORT
      LAYER Metal5 ;
        RECT 0.0000 352.7000 0.2900 352.7700 ;
    END
  END ahbsi_out[127]
  PIN ahbsi_out[126]
    DIRECTION OUTPUT ;
    USE SIGNAL ;
    PORT
      LAYER Metal5 ;
        RECT 0.0000 355.5500 0.2900 355.6200 ;
    END
  END ahbsi_out[126]
  PIN ahbsi_out[125]
    DIRECTION OUTPUT ;
    USE SIGNAL ;
    PORT
      LAYER Metal3 ;
        RECT 0.0000 341.3000 0.2900 341.3700 ;
    END
  END ahbsi_out[125]
  PIN ahbsi_out[124]
    DIRECTION OUTPUT ;
    USE SIGNAL ;
    PORT
      LAYER Metal9 ;
        RECT 0.0000 341.6800 0.2900 341.7500 ;
    END
  END ahbsi_out[124]
  PIN ahbsi_out[123]
    DIRECTION OUTPUT ;
    USE SIGNAL ;
    PORT
      LAYER Metal5 ;
        RECT 0.0000 328.3800 0.2900 328.4500 ;
    END
  END ahbsi_out[123]
  PIN ahbsi_out[122]
    DIRECTION OUTPUT ;
    USE SIGNAL ;
    PORT
      LAYER Metal3 ;
        RECT 0.0000 328.7600 0.2900 328.8300 ;
    END
  END ahbsi_out[122]
  PIN ahbsi_out[121]
    DIRECTION OUTPUT ;
    USE SIGNAL ;
    PORT
      LAYER Metal3 ;
        RECT 0.0000 317.9300 0.2900 318.0000 ;
    END
  END ahbsi_out[121]
  PIN ahbsi_out[120]
    DIRECTION OUTPUT ;
    USE SIGNAL ;
    PORT
      LAYER Metal3 ;
        RECT 0.0000 333.5100 0.2900 333.5800 ;
    END
  END ahbsi_out[120]
  PIN ahbsi_out[119]
    DIRECTION OUTPUT ;
    USE SIGNAL ;
    PORT
      LAYER Metal3 ;
        RECT 0.0000 332.9400 0.2900 333.0100 ;
    END
  END ahbsi_out[119]
  PIN ahbsi_out[118]
    DIRECTION OUTPUT ;
    USE SIGNAL ;
    PORT
      LAYER Metal3 ;
        RECT 0.0000 344.3400 0.2900 344.4100 ;
    END
  END ahbsi_out[118]
  PIN ahbsi_out[117]
    DIRECTION OUTPUT ;
    USE SIGNAL ;
    PORT
      LAYER Metal3 ;
        RECT 0.0000 342.4400 0.2900 342.5100 ;
    END
  END ahbsi_out[117]
  PIN ahbsi_out[116]
    DIRECTION OUTPUT ;
    USE SIGNAL ;
    PORT
      LAYER Metal5 ;
        RECT 0.0000 341.6800 0.2900 341.7500 ;
    END
  END ahbsi_out[116]
  PIN ahbsi_out[115]
    DIRECTION OUTPUT ;
    USE SIGNAL ;
    PORT
      LAYER Metal3 ;
        RECT 0.0000 341.6800 0.2900 341.7500 ;
    END
  END ahbsi_out[115]
  PIN ahbsi_out[114]
    DIRECTION OUTPUT ;
    USE SIGNAL ;
    PORT
      LAYER Metal5 ;
        RECT 0.0000 338.8300 0.2900 338.9000 ;
    END
  END ahbsi_out[114]
  PIN ahbsi_out[113]
    DIRECTION OUTPUT ;
    USE SIGNAL ;
    PORT
      LAYER Metal5 ;
        RECT 0.0000 331.2300 0.2900 331.3000 ;
    END
  END ahbsi_out[113]
  PIN ahbsi_out[112]
    DIRECTION OUTPUT ;
    USE SIGNAL ;
    PORT
      LAYER Metal2 ;
        RECT 32.0650 363.9400 32.1350 364.2300 ;
    END
  END ahbsi_out[112]
  PIN ahbsi_out[111]
    DIRECTION OUTPUT ;
    USE SIGNAL ;
    PORT
      LAYER Metal3 ;
        RECT 0.0000 335.2200 0.2900 335.2900 ;
    END
  END ahbsi_out[111]
  PIN ahbsi_out[110]
    DIRECTION OUTPUT ;
    USE SIGNAL ;
    PORT
      LAYER Metal2 ;
        RECT 33.8650 363.9400 33.9350 364.2300 ;
    END
  END ahbsi_out[110]
  PIN ahbsi_out[109]
    DIRECTION OUTPUT ;
    USE SIGNAL ;
    PORT
      LAYER Metal5 ;
        RECT 0.0000 342.8200 0.2900 342.8900 ;
    END
  END ahbsi_out[109]
  PIN ahbsi_out[108]
    DIRECTION OUTPUT ;
    USE SIGNAL ;
    PORT
      LAYER Metal2 ;
        RECT 48.2650 363.9400 48.3350 364.2300 ;
    END
  END ahbsi_out[108]
  PIN ahbsi_out[107]
    DIRECTION OUTPUT ;
    USE SIGNAL ;
    PORT
      LAYER Metal3 ;
        RECT 0.0000 340.1600 0.2900 340.2300 ;
    END
  END ahbsi_out[107]
  PIN ahbsi_out[106]
    DIRECTION OUTPUT ;
    USE SIGNAL ;
    PORT
      LAYER Metal2 ;
        RECT 36.4650 363.9400 36.5350 364.2300 ;
    END
  END ahbsi_out[106]
  PIN ahbsi_out[105]
    DIRECTION OUTPUT ;
    USE SIGNAL ;
    PORT
      LAYER Metal2 ;
        RECT 37.8650 363.9400 37.9350 364.2300 ;
    END
  END ahbsi_out[105]
  PIN ahbsi_out[104]
    DIRECTION OUTPUT ;
    USE SIGNAL ;
    PORT
      LAYER Metal3 ;
        RECT 0.0000 350.0400 0.2900 350.1100 ;
    END
  END ahbsi_out[104]
  PIN ahbsi_out[103]
    DIRECTION OUTPUT ;
    USE SIGNAL ;
    PORT
      LAYER Metal3 ;
        RECT 0.0000 348.9000 0.2900 348.9700 ;
    END
  END ahbsi_out[103]
  PIN ahbsi_out[102]
    DIRECTION OUTPUT ;
    USE SIGNAL ;
    PORT
      LAYER Metal5 ;
        RECT 0.0000 353.0800 0.2900 353.1500 ;
    END
  END ahbsi_out[102]
  PIN ahbsi_out[101]
    DIRECTION OUTPUT ;
    USE SIGNAL ;
    PORT
      LAYER Metal4 ;
        RECT 10.8650 363.9400 10.9350 364.2300 ;
    END
  END ahbsi_out[101]
  PIN ahbsi_out[100]
    DIRECTION OUTPUT ;
    USE SIGNAL ;
    PORT
      LAYER Metal5 ;
        RECT 0.0000 327.6200 0.2900 327.6900 ;
    END
  END ahbsi_out[100]
  PIN ahbsi_out[99]
    DIRECTION OUTPUT ;
    USE SIGNAL ;
    PORT
      LAYER Metal3 ;
        RECT 0.0000 311.4700 0.2900 311.5400 ;
    END
  END ahbsi_out[99]
  PIN ahbsi_out[98]
    DIRECTION OUTPUT ;
    USE SIGNAL ;
    PORT
      LAYER Metal3 ;
        RECT 0.0000 313.1800 0.2900 313.2500 ;
    END
  END ahbsi_out[98]
  PIN ahbsi_out[97]
    DIRECTION OUTPUT ;
    USE SIGNAL ;
    PORT
      LAYER Metal3 ;
        RECT 0.0000 320.0200 0.2900 320.0900 ;
    END
  END ahbsi_out[97]
  PIN ahbsi_out[96]
    DIRECTION OUTPUT ;
    USE SIGNAL ;
    PORT
      LAYER Metal3 ;
        RECT 0.0000 342.0600 0.2900 342.1300 ;
    END
  END ahbsi_out[96]
  PIN ahbsi_out[95]
    DIRECTION OUTPUT ;
    USE SIGNAL ;
    PORT
      LAYER Metal3 ;
        RECT 0.0000 342.8200 0.2900 342.8900 ;
    END
  END ahbsi_out[95]
  PIN ahbsi_out[94]
    DIRECTION OUTPUT ;
    USE SIGNAL ;
    PORT
      LAYER Metal2 ;
        RECT 29.8650 363.9400 29.9350 364.2300 ;
    END
  END ahbsi_out[94]
  PIN ahbsi_out[93]
    DIRECTION OUTPUT ;
    USE SIGNAL ;
    PORT
      LAYER Metal4 ;
        RECT 1671.0650 363.9400 1671.1350 364.2300 ;
    END
  END ahbsi_out[93]
  PIN ahbsi_out[92]
    DIRECTION OUTPUT ;
    USE SIGNAL ;
    PORT
      LAYER Metal6 ;
        RECT 1671.0650 363.9400 1671.1350 364.2300 ;
    END
  END ahbsi_out[92]
  PIN ahbsi_out[91]
    DIRECTION OUTPUT ;
    USE SIGNAL ;
    PORT
      LAYER Metal8 ;
        RECT 1690.2650 363.9400 1690.3350 364.2300 ;
    END
  END ahbsi_out[91]
  PIN ahbsi_out[90]
    DIRECTION OUTPUT ;
    USE SIGNAL ;
    PORT
      LAYER Metal2 ;
        RECT 1690.2650 363.9400 1690.3350 364.2300 ;
    END
  END ahbsi_out[90]
  PIN ahbsi_out[89]
    DIRECTION OUTPUT ;
    USE SIGNAL ;
    PORT
      LAYER Metal5 ;
        RECT 0.0000 344.7200 0.2900 344.7900 ;
    END
  END ahbsi_out[89]
  PIN ahbsi_out[88]
    DIRECTION OUTPUT ;
    USE SIGNAL ;
    PORT
      LAYER Metal4 ;
        RECT 1690.2650 363.9400 1690.3350 364.2300 ;
    END
  END ahbsi_out[88]
  PIN ahbsi_out[87]
    DIRECTION OUTPUT ;
    USE SIGNAL ;
    PORT
      LAYER Metal6 ;
        RECT 1690.2650 363.9400 1690.3350 364.2300 ;
    END
  END ahbsi_out[87]
  PIN ahbsi_out[86]
    DIRECTION OUTPUT ;
    USE SIGNAL ;
    PORT
      LAYER Metal8 ;
        RECT 1670.8650 363.9400 1670.9350 364.2300 ;
    END
  END ahbsi_out[86]
  PIN ahbsi_out[85]
    DIRECTION OUTPUT ;
    USE SIGNAL ;
    PORT
      LAYER Metal2 ;
        RECT 1670.6650 363.9400 1670.7350 364.2300 ;
    END
  END ahbsi_out[85]
  PIN ahbsi_out[84]
    DIRECTION OUTPUT ;
    USE SIGNAL ;
    PORT
      LAYER Metal4 ;
        RECT 1670.6650 363.9400 1670.7350 364.2300 ;
    END
  END ahbsi_out[84]
  PIN ahbsi_out[83]
    DIRECTION OUTPUT ;
    USE SIGNAL ;
    PORT
      LAYER Metal3 ;
        RECT 0.0000 363.1500 0.2900 363.2200 ;
    END
  END ahbsi_out[83]
  PIN ahbsi_out[82]
    DIRECTION OUTPUT ;
    USE SIGNAL ;
    PORT
      LAYER Metal2 ;
        RECT 145.2650 363.9400 145.3350 364.2300 ;
    END
  END ahbsi_out[82]
  PIN ahbsi_out[81]
    DIRECTION OUTPUT ;
    USE SIGNAL ;
    PORT
      LAYER Metal5 ;
        RECT 0.0000 334.2700 0.2900 334.3400 ;
    END
  END ahbsi_out[81]
  PIN ahbsi_out[80]
    DIRECTION OUTPUT ;
    USE SIGNAL ;
    PORT
      LAYER Metal6 ;
        RECT 1670.6650 363.9400 1670.7350 364.2300 ;
    END
  END ahbsi_out[80]
  PIN ahbsi_out[79]
    DIRECTION OUTPUT ;
    USE SIGNAL ;
    PORT
      LAYER Metal2 ;
        RECT 1690.6650 363.9400 1690.7350 364.2300 ;
    END
  END ahbsi_out[79]
  PIN ahbsi_out[78]
    DIRECTION OUTPUT ;
    USE SIGNAL ;
    PORT
      LAYER Metal4 ;
        RECT 1690.6650 363.9400 1690.7350 364.2300 ;
    END
  END ahbsi_out[78]
  PIN ahbsi_out[77]
    DIRECTION OUTPUT ;
    USE SIGNAL ;
    PORT
      LAYER Metal6 ;
        RECT 1690.6650 363.9400 1690.7350 364.2300 ;
    END
  END ahbsi_out[77]
  PIN ahbsi_out[76]
    DIRECTION OUTPUT ;
    USE SIGNAL ;
    PORT
      LAYER Metal8 ;
        RECT 1670.4650 363.9400 1670.5350 364.2300 ;
    END
  END ahbsi_out[76]
  PIN ahbsi_out[75]
    DIRECTION OUTPUT ;
    USE SIGNAL ;
    PORT
      LAYER Metal8 ;
        RECT 1690.6650 363.9400 1690.7350 364.2300 ;
    END
  END ahbsi_out[75]
  PIN ahbsi_out[74]
    DIRECTION OUTPUT ;
    USE SIGNAL ;
    PORT
      LAYER Metal2 ;
        RECT 1670.2650 363.9400 1670.3350 364.2300 ;
    END
  END ahbsi_out[74]
  PIN ahbsi_out[73]
    DIRECTION OUTPUT ;
    USE SIGNAL ;
    PORT
      LAYER Metal4 ;
        RECT 1670.2650 363.9400 1670.3350 364.2300 ;
    END
  END ahbsi_out[73]
  PIN ahbsi_out[72]
    DIRECTION OUTPUT ;
    USE SIGNAL ;
    PORT
      LAYER Metal6 ;
        RECT 1670.2650 363.9400 1670.3350 364.2300 ;
    END
  END ahbsi_out[72]
  PIN ahbsi_out[71]
    DIRECTION OUTPUT ;
    USE SIGNAL ;
    PORT
      LAYER Metal2 ;
        RECT 1691.0650 363.9400 1691.1350 364.2300 ;
    END
  END ahbsi_out[71]
  PIN ahbsi_out[70]
    DIRECTION OUTPUT ;
    USE SIGNAL ;
    PORT
      LAYER Metal4 ;
        RECT 1691.0650 363.9400 1691.1350 364.2300 ;
    END
  END ahbsi_out[70]
  PIN ahbsi_out[69]
    DIRECTION OUTPUT ;
    USE SIGNAL ;
    PORT
      LAYER Metal6 ;
        RECT 1691.0650 363.9400 1691.1350 364.2300 ;
    END
  END ahbsi_out[69]
  PIN ahbsi_out[68]
    DIRECTION OUTPUT ;
    USE SIGNAL ;
    PORT
      LAYER Metal8 ;
        RECT 1670.0650 363.9400 1670.1350 364.2300 ;
    END
  END ahbsi_out[68]
  PIN ahbsi_out[67]
    DIRECTION OUTPUT ;
    USE SIGNAL ;
    PORT
      LAYER Metal8 ;
        RECT 1691.0650 363.9400 1691.1350 364.2300 ;
    END
  END ahbsi_out[67]
  PIN ahbsi_out[66]
    DIRECTION OUTPUT ;
    USE SIGNAL ;
    PORT
      LAYER Metal2 ;
        RECT 1669.8650 363.9400 1669.9350 364.2300 ;
    END
  END ahbsi_out[66]
  PIN ahbsi_out[65]
    DIRECTION OUTPUT ;
    USE SIGNAL ;
    PORT
      LAYER Metal4 ;
        RECT 1669.8650 363.9400 1669.9350 364.2300 ;
    END
  END ahbsi_out[65]
  PIN ahbsi_out[64]
    DIRECTION OUTPUT ;
    USE SIGNAL ;
    PORT
      LAYER Metal6 ;
        RECT 1669.8650 363.9400 1669.9350 364.2300 ;
    END
  END ahbsi_out[64]
  PIN ahbsi_out[63]
    DIRECTION OUTPUT ;
    USE SIGNAL ;
    PORT
      LAYER Metal2 ;
        RECT 1691.4650 363.9400 1691.5350 364.2300 ;
    END
  END ahbsi_out[63]
  PIN ahbsi_out[62]
    DIRECTION OUTPUT ;
    USE SIGNAL ;
    PORT
      LAYER Metal4 ;
        RECT 1691.4650 363.9400 1691.5350 364.2300 ;
    END
  END ahbsi_out[62]
  PIN ahbsi_out[61]
    DIRECTION OUTPUT ;
    USE SIGNAL ;
    PORT
      LAYER Metal3 ;
        RECT 0.0000 361.2500 0.2900 361.3200 ;
    END
  END ahbsi_out[61]
  PIN ahbsi_out[60]
    DIRECTION OUTPUT ;
    USE SIGNAL ;
    PORT
      LAYER Metal9 ;
        RECT 0.0000 361.0600 0.2900 361.1300 ;
    END
  END ahbsi_out[60]
  PIN ahbsi_out[59]
    DIRECTION OUTPUT ;
    USE SIGNAL ;
    PORT
      LAYER Metal5 ;
        RECT 0.0000 361.0600 0.2900 361.1300 ;
    END
  END ahbsi_out[59]
  PIN ahbsi_out[58]
    DIRECTION OUTPUT ;
    USE SIGNAL ;
    PORT
      LAYER Metal5 ;
        RECT 0.0000 360.6800 0.2900 360.7500 ;
    END
  END ahbsi_out[58]
  PIN ahbsi_out[57]
    DIRECTION OUTPUT ;
    USE SIGNAL ;
    PORT
      LAYER Metal3 ;
        RECT 0.0000 360.4900 0.2900 360.5600 ;
    END
  END ahbsi_out[57]
  PIN ahbsi_out[56]
    DIRECTION OUTPUT ;
    USE SIGNAL ;
    PORT
      LAYER Metal9 ;
        RECT 0.0000 360.3000 0.2900 360.3700 ;
    END
  END ahbsi_out[56]
  PIN ahbsi_out[55]
    DIRECTION OUTPUT ;
    USE SIGNAL ;
    PORT
      LAYER Metal5 ;
        RECT 0.0000 360.3000 0.2900 360.3700 ;
    END
  END ahbsi_out[55]
  PIN ahbsi_out[54]
    DIRECTION OUTPUT ;
    USE SIGNAL ;
    PORT
      LAYER Metal3 ;
        RECT 0.0000 360.1100 0.2900 360.1800 ;
    END
  END ahbsi_out[54]
  PIN ahbsi_out[53]
    DIRECTION OUTPUT ;
    USE SIGNAL ;
    PORT
      LAYER Metal5 ;
        RECT 0.0000 359.9200 0.2900 359.9900 ;
    END
  END ahbsi_out[53]
  PIN ahbsi_out[52]
    DIRECTION OUTPUT ;
    USE SIGNAL ;
    PORT
      LAYER Metal6 ;
        RECT 1691.4650 363.9400 1691.5350 364.2300 ;
    END
  END ahbsi_out[52]
  PIN ahbsi_out[51]
    DIRECTION OUTPUT ;
    USE SIGNAL ;
    PORT
      LAYER Metal8 ;
        RECT 1669.6650 363.9400 1669.7350 364.2300 ;
    END
  END ahbsi_out[51]
  PIN ahbsi_out[50]
    DIRECTION OUTPUT ;
    USE SIGNAL ;
    PORT
      LAYER Metal5 ;
        RECT 0.0000 362.2000 0.2900 362.2700 ;
    END
  END ahbsi_out[50]
  PIN ahbsi_out[49]
    DIRECTION OUTPUT ;
    USE SIGNAL ;
    PORT
      LAYER Metal4 ;
        RECT 104.0650 363.9400 104.1350 364.2300 ;
    END
  END ahbsi_out[49]
  PIN ahbsi_out[48]
    DIRECTION OUTPUT ;
    USE SIGNAL ;
    PORT
      LAYER Metal2 ;
        RECT 104.2650 363.9400 104.3350 364.2300 ;
    END
  END ahbsi_out[48]
  PIN ahbsi_out[47]
    DIRECTION OUTPUT ;
    USE SIGNAL ;
    PORT
      LAYER Metal5 ;
        RECT 0.0000 361.8200 0.2900 361.8900 ;
    END
  END ahbsi_out[47]
  PIN ahbsi_out[46]
    DIRECTION OUTPUT ;
    USE SIGNAL ;
    PORT
      LAYER Metal3 ;
        RECT 0.0000 361.6300 0.2900 361.7000 ;
    END
  END ahbsi_out[46]
  PIN ahbsi_out[45]
    DIRECTION OUTPUT ;
    USE SIGNAL ;
    PORT
      LAYER Metal5 ;
        RECT 0.0000 361.4400 0.2900 361.5100 ;
    END
  END ahbsi_out[45]
  PIN ahbsi_out[44]
    DIRECTION OUTPUT ;
    USE SIGNAL ;
    PORT
      LAYER Metal8 ;
        RECT 1691.4650 363.9400 1691.5350 364.2300 ;
    END
  END ahbsi_out[44]
  PIN ahbsi_out[43]
    DIRECTION OUTPUT ;
    USE SIGNAL ;
    PORT
      LAYER Metal2 ;
        RECT 1669.4650 363.9400 1669.5350 364.2300 ;
    END
  END ahbsi_out[43]
  PIN ahbsi_out[42]
    DIRECTION OUTPUT ;
    USE SIGNAL ;
    PORT
      LAYER Metal4 ;
        RECT 1669.4650 363.9400 1669.5350 364.2300 ;
    END
  END ahbsi_out[42]
  PIN ahbsi_out[41]
    DIRECTION OUTPUT ;
    USE SIGNAL ;
    PORT
      LAYER Metal5 ;
        RECT 0.0000 330.4700 0.2900 330.5400 ;
    END
  END ahbsi_out[41]
  PIN ahbsi_out[40]
    DIRECTION OUTPUT ;
    USE SIGNAL ;
    PORT
      LAYER Metal5 ;
        RECT 0.0000 333.3200 0.2900 333.3900 ;
    END
  END ahbsi_out[40]
  PIN ahbsi_out[39]
    DIRECTION OUTPUT ;
    USE SIGNAL ;
    PORT
      LAYER Metal5 ;
        RECT 0.0000 332.5600 0.2900 332.6300 ;
    END
  END ahbsi_out[39]
  PIN ahbsi_out[38]
    DIRECTION OUTPUT ;
    USE SIGNAL ;
    PORT
      LAYER Metal5 ;
        RECT 0.0000 320.2100 0.2900 320.2800 ;
    END
  END ahbsi_out[38]
  PIN ahbsi_out[37]
    DIRECTION OUTPUT ;
    USE SIGNAL ;
    PORT
      LAYER Metal3 ;
        RECT 0.0000 321.3500 0.2900 321.4200 ;
    END
  END ahbsi_out[37]
  PIN ahbsi_out[36]
    DIRECTION OUTPUT ;
    USE SIGNAL ;
    PORT
      LAYER Metal3 ;
        RECT 0.0000 315.0800 0.2900 315.1500 ;
    END
  END ahbsi_out[36]
  PIN ahbsi_out[35]
    DIRECTION OUTPUT ;
    USE SIGNAL ;
    PORT
      LAYER Metal5 ;
        RECT 0.0000 312.9900 0.2900 313.0600 ;
    END
  END ahbsi_out[35]
  PIN ahbsi_out[34]
    DIRECTION OUTPUT ;
    USE SIGNAL ;
    PORT
      LAYER Metal5 ;
        RECT 0.0000 311.2800 0.2900 311.3500 ;
    END
  END ahbsi_out[34]
  PIN ahbsi_out[33]
    DIRECTION OUTPUT ;
    USE SIGNAL ;
    PORT
      LAYER Metal3 ;
        RECT 0.0000 307.1000 0.2900 307.1700 ;
    END
  END ahbsi_out[33]
  PIN ahbsi_out[32]
    DIRECTION OUTPUT ;
    USE SIGNAL ;
    PORT
      LAYER Metal3 ;
        RECT 0.0000 329.9000 0.2900 329.9700 ;
    END
  END ahbsi_out[32]
  PIN ahbsi_out[31]
    DIRECTION OUTPUT ;
    USE SIGNAL ;
    PORT
      LAYER Metal2 ;
        RECT 18.6650 363.9400 18.7350 364.2300 ;
    END
  END ahbsi_out[31]
  PIN ahbsi_out[30]
    DIRECTION OUTPUT ;
    USE SIGNAL ;
    PORT
      LAYER Metal3 ;
        RECT 0.0000 329.5200 0.2900 329.5900 ;
    END
  END ahbsi_out[30]
  PIN ahbsi_out[29]
    DIRECTION OUTPUT ;
    USE SIGNAL ;
    PORT
      LAYER Metal5 ;
        RECT 0.0000 325.7200 0.2900 325.7900 ;
    END
  END ahbsi_out[29]
  PIN ahbsi_out[28]
    DIRECTION OUTPUT ;
    USE SIGNAL ;
    PORT
      LAYER Metal5 ;
        RECT 0.0000 326.1000 0.2900 326.1700 ;
    END
  END ahbsi_out[28]
  PIN ahbsi_out[27]
    DIRECTION OUTPUT ;
    USE SIGNAL ;
    PORT
      LAYER Metal9 ;
        RECT 0.0000 327.6200 0.2900 327.6900 ;
    END
  END ahbsi_out[27]
  PIN ahbsi_out[26]
    DIRECTION OUTPUT ;
    USE SIGNAL ;
    PORT
      LAYER Metal2 ;
        RECT 30.8650 363.9400 30.9350 364.2300 ;
    END
  END ahbsi_out[26]
  PIN ahbsi_out[25]
    DIRECTION OUTPUT ;
    USE SIGNAL ;
    PORT
      LAYER Metal3 ;
        RECT 0.0000 329.1400 0.2900 329.2100 ;
    END
  END ahbsi_out[25]
  PIN ahbsi_out[24]
    DIRECTION OUTPUT ;
    USE SIGNAL ;
    PORT
      LAYER Metal5 ;
        RECT 0.0000 318.1200 0.2900 318.1900 ;
    END
  END ahbsi_out[24]
  PIN ahbsi_out[23]
    DIRECTION OUTPUT ;
    USE SIGNAL ;
    PORT
      LAYER Metal3 ;
        RECT 0.0000 318.3100 0.2900 318.3800 ;
    END
  END ahbsi_out[23]
  PIN ahbsi_out[22]
    DIRECTION OUTPUT ;
    USE SIGNAL ;
    PORT
      LAYER Metal5 ;
        RECT 0.0000 354.2200 0.2900 354.2900 ;
    END
  END ahbsi_out[22]
  PIN ahbsi_out[21]
    DIRECTION OUTPUT ;
    USE SIGNAL ;
    PORT
      LAYER Metal9 ;
        RECT 0.0000 351.1800 0.2900 351.2500 ;
    END
  END ahbsi_out[21]
  PIN ahbsi_out[20]
    DIRECTION OUTPUT ;
    USE SIGNAL ;
    PORT
      LAYER Metal5 ;
        RECT 0.0000 352.3200 0.2900 352.3900 ;
    END
  END ahbsi_out[20]
  PIN ahbsi_out[19]
    DIRECTION OUTPUT ;
    USE SIGNAL ;
    PORT
      LAYER Metal3 ;
        RECT 0.0000 362.3900 0.2900 362.4600 ;
    END
  END ahbsi_out[19]
  PIN ahbsi_out[18]
    DIRECTION OUTPUT ;
    USE SIGNAL ;
    PORT
      LAYER Metal9 ;
        RECT 0.0000 361.8200 0.2900 361.8900 ;
    END
  END ahbsi_out[18]
  PIN ahbsi_out[17]
    DIRECTION OUTPUT ;
    USE SIGNAL ;
    PORT
      LAYER Metal2 ;
        RECT 9.6650 363.9400 9.7350 364.2300 ;
    END
  END ahbsi_out[17]
  PIN ahbsi_out[16]
    DIRECTION OUTPUT ;
    USE SIGNAL ;
    PORT
      LAYER Metal5 ;
        RECT 0.0000 325.3400 0.2900 325.4100 ;
    END
  END ahbsi_out[16]
  PIN ahbsi_out[15]
    DIRECTION OUTPUT ;
    USE SIGNAL ;
    PORT
      LAYER Metal5 ;
        RECT 0.0000 334.6500 0.2900 334.7200 ;
    END
  END ahbsi_out[15]
  PIN ahbsi_out[14]
    DIRECTION OUTPUT ;
    USE SIGNAL ;
    PORT
      LAYER Metal3 ;
        RECT 0.0000 360.8700 0.2900 360.9400 ;
    END
  END ahbsi_out[14]
  PIN ahbsi_out[13]
    DIRECTION OUTPUT ;
    USE SIGNAL ;
    PORT
      LAYER Metal3 ;
        RECT 0.0000 359.7300 0.2900 359.8000 ;
    END
  END ahbsi_out[13]
  PIN ahbsi_out[12]
    DIRECTION OUTPUT ;
    USE SIGNAL ;
    PORT
      LAYER Metal3 ;
        RECT 0.0000 332.3700 0.2900 332.4400 ;
    END
  END ahbsi_out[12]
  PIN ahbsi_out[11]
    DIRECTION OUTPUT ;
    USE SIGNAL ;
    PORT
      LAYER Metal3 ;
        RECT 0.0000 326.1000 0.2900 326.1700 ;
    END
  END ahbsi_out[11]
  PIN ahbsi_out[10]
    DIRECTION OUTPUT ;
    USE SIGNAL ;
    PORT
      LAYER Metal5 ;
        RECT 0.0000 351.1800 0.2900 351.2500 ;
    END
  END ahbsi_out[10]
  PIN ahbsi_out[9]
    DIRECTION OUTPUT ;
    USE SIGNAL ;
    PORT
      LAYER Metal6 ;
        RECT 1669.4650 363.9400 1669.5350 364.2300 ;
    END
  END ahbsi_out[9]
  PIN ahbsi_out[8]
    DIRECTION OUTPUT ;
    USE SIGNAL ;
    PORT
      LAYER Metal2 ;
        RECT 1691.8650 363.9400 1691.9350 364.2300 ;
    END
  END ahbsi_out[8]
  PIN ahbsi_out[7]
    DIRECTION OUTPUT ;
    USE SIGNAL ;
    PORT
      LAYER Metal4 ;
        RECT 1691.8650 363.9400 1691.9350 364.2300 ;
    END
  END ahbsi_out[7]
  PIN ahbsi_out[6]
    DIRECTION OUTPUT ;
    USE SIGNAL ;
    PORT
      LAYER Metal6 ;
        RECT 1691.8650 363.9400 1691.9350 364.2300 ;
    END
  END ahbsi_out[6]
  PIN ahbsi_out[5]
    DIRECTION OUTPUT ;
    USE SIGNAL ;
    PORT
      LAYER Metal3 ;
        RECT 0.0000 362.0100 0.2900 362.0800 ;
    END
  END ahbsi_out[5]
  PIN ahbsi_out[4]
    DIRECTION OUTPUT ;
    USE SIGNAL ;
    PORT
      LAYER Metal8 ;
        RECT 1669.2650 363.9400 1669.3350 364.2300 ;
    END
  END ahbsi_out[4]
  PIN ahbsi_out[3]
    DIRECTION OUTPUT ;
    USE SIGNAL ;
    PORT
      LAYER Metal8 ;
        RECT 1691.8650 363.9400 1691.9350 364.2300 ;
    END
  END ahbsi_out[3]
  PIN ahbsi_out[2]
    DIRECTION OUTPUT ;
    USE SIGNAL ;
    PORT
      LAYER Metal2 ;
        RECT 1669.0650 363.9400 1669.1350 364.2300 ;
    END
  END ahbsi_out[2]
  PIN ahbsi_out[1]
    DIRECTION OUTPUT ;
    USE SIGNAL ;
    PORT
      LAYER Metal4 ;
        RECT 1669.0650 363.9400 1669.1350 364.2300 ;
    END
  END ahbsi_out[1]
  PIN ahbsi_out[0]
    DIRECTION OUTPUT ;
    USE SIGNAL ;
    PORT
      LAYER Metal6 ;
        RECT 1669.0650 363.9400 1669.1350 364.2300 ;
    END
  END ahbsi_out[0]
  PIN ahbso_in_356
    DIRECTION INPUT ;
    USE SIGNAL ;
    PORT
      LAYER Metal3 ;
        RECT 0.0000 295.7000 0.2900 295.7700 ;
    END
  END ahbso_in_356
  PIN ahbso_in_354
    DIRECTION INPUT ;
    USE SIGNAL ;
    PORT
      LAYER Metal5 ;
        RECT 0.0000 309.3800 0.2900 309.4500 ;
    END
  END ahbso_in_354
  PIN ahbso_in_353
    DIRECTION INPUT ;
    USE SIGNAL ;
    PORT
      LAYER Metal3 ;
        RECT 0.0000 309.5700 0.2900 309.6400 ;
    END
  END ahbso_in_353
  PIN ahbso_in_352
    DIRECTION INPUT ;
    USE SIGNAL ;
    PORT
      LAYER Metal9 ;
        RECT 0.0000 309.7600 0.2900 309.8300 ;
    END
  END ahbso_in_352
  PIN ahbso_in_351
    DIRECTION INPUT ;
    USE SIGNAL ;
    PORT
      LAYER Metal5 ;
        RECT 0.0000 309.7600 0.2900 309.8300 ;
    END
  END ahbso_in_351
  PIN ahbso_in_350
    DIRECTION INPUT ;
    USE SIGNAL ;
    PORT
      LAYER Metal2 ;
        RECT 69.2650 363.9400 69.3350 364.2300 ;
    END
  END ahbso_in_350
  PIN ahbso_in_349
    DIRECTION INPUT ;
    USE SIGNAL ;
    PORT
      LAYER Metal2 ;
        RECT 76.2650 363.9400 76.3350 364.2300 ;
    END
  END ahbso_in_349
  PIN ahbso_in_348
    DIRECTION INPUT ;
    USE SIGNAL ;
    PORT
      LAYER Metal3 ;
        RECT 0.0000 309.9500 0.2900 310.0200 ;
    END
  END ahbso_in_348
  PIN ahbso_in_347
    DIRECTION INPUT ;
    USE SIGNAL ;
    PORT
      LAYER Metal5 ;
        RECT 0.0000 310.1400 0.2900 310.2100 ;
    END
  END ahbso_in_347
  PIN ahbso_in_346
    DIRECTION INPUT ;
    USE SIGNAL ;
    PORT
      LAYER Metal5 ;
        RECT 0.0000 310.5200 0.2900 310.5900 ;
    END
  END ahbso_in_346
  PIN ahbso_in_345
    DIRECTION INPUT ;
    USE SIGNAL ;
    PORT
      LAYER Metal5 ;
        RECT 0.0000 310.9000 0.2900 310.9700 ;
    END
  END ahbso_in_345
  PIN ahbso_in_344
    DIRECTION INPUT ;
    USE SIGNAL ;
    PORT
      LAYER Metal5 ;
        RECT 0.0000 311.8500 0.2900 311.9200 ;
    END
  END ahbso_in_344
  PIN ahbso_in_343
    DIRECTION INPUT ;
    USE SIGNAL ;
    PORT
      LAYER Metal3 ;
        RECT 0.0000 312.0400 0.2900 312.1100 ;
    END
  END ahbso_in_343
  PIN ahbso_in_342
    DIRECTION INPUT ;
    USE SIGNAL ;
    PORT
      LAYER Metal5 ;
        RECT 0.0000 312.2300 0.2900 312.3000 ;
    END
  END ahbso_in_342
  PIN ahbso_in_341
    DIRECTION INPUT ;
    USE SIGNAL ;
    PORT
      LAYER Metal4 ;
        RECT 81.2650 363.9400 81.3350 364.2300 ;
    END
  END ahbso_in_341
  PIN ahbso_in_340
    DIRECTION INPUT ;
    USE SIGNAL ;
    PORT
      LAYER Metal3 ;
        RECT 0.0000 312.4200 0.2900 312.4900 ;
    END
  END ahbso_in_340
  PIN ahbso_in_339
    DIRECTION INPUT ;
    USE SIGNAL ;
    PORT
      LAYER Metal5 ;
        RECT 0.0000 312.6100 0.2900 312.6800 ;
    END
  END ahbso_in_339
  PIN ahbso_in_338
    DIRECTION INPUT ;
    USE SIGNAL ;
    PORT
      LAYER Metal3 ;
        RECT 0.0000 312.8000 0.2900 312.8700 ;
    END
  END ahbso_in_338
  PIN ahbso_in_337
    DIRECTION INPUT ;
    USE SIGNAL ;
    PORT
      LAYER Metal3 ;
        RECT 0.0000 313.7500 0.2900 313.8200 ;
    END
  END ahbso_in_337
  PIN ahbso_in_336
    DIRECTION INPUT ;
    USE SIGNAL ;
    PORT
      LAYER Metal5 ;
        RECT 0.0000 313.9400 0.2900 314.0100 ;
    END
  END ahbso_in_336
  PIN ahbso_in_335
    DIRECTION INPUT ;
    USE SIGNAL ;
    PORT
      LAYER Metal5 ;
        RECT 0.0000 314.7000 0.2900 314.7700 ;
    END
  END ahbso_in_335
  PIN ahbso_in_334
    DIRECTION INPUT ;
    USE SIGNAL ;
    PORT
      LAYER Metal3 ;
        RECT 0.0000 314.7000 0.2900 314.7700 ;
    END
  END ahbso_in_334
  PIN ahbso_in_333
    DIRECTION INPUT ;
    USE SIGNAL ;
    PORT
      LAYER Metal5 ;
        RECT 0.0000 315.0800 0.2900 315.1500 ;
    END
  END ahbso_in_333
  PIN ahbso_in_332
    DIRECTION INPUT ;
    USE SIGNAL ;
    PORT
      LAYER Metal5 ;
        RECT 0.0000 315.4600 0.2900 315.5300 ;
    END
  END ahbso_in_332
  PIN ahbso_in_331
    DIRECTION INPUT ;
    USE SIGNAL ;
    PORT
      LAYER Metal5 ;
        RECT 0.0000 315.8400 0.2900 315.9100 ;
    END
  END ahbso_in_331
  PIN ahbso_in_330
    DIRECTION INPUT ;
    USE SIGNAL ;
    PORT
      LAYER Metal5 ;
        RECT 0.0000 316.2200 0.2900 316.2900 ;
    END
  END ahbso_in_330
  PIN ahbso_in_329
    DIRECTION INPUT ;
    USE SIGNAL ;
    PORT
      LAYER Metal5 ;
        RECT 0.0000 316.9800 0.2900 317.0500 ;
    END
  END ahbso_in_329
  PIN ahbso_in_328
    DIRECTION INPUT ;
    USE SIGNAL ;
    PORT
      LAYER Metal3 ;
        RECT 0.0000 317.1700 0.2900 317.2400 ;
    END
  END ahbso_in_328
  PIN ahbso_in_327
    DIRECTION INPUT ;
    USE SIGNAL ;
    PORT
      LAYER Metal5 ;
        RECT 0.0000 317.3600 0.2900 317.4300 ;
    END
  END ahbso_in_327
  PIN ahbso_in_326
    DIRECTION INPUT ;
    USE SIGNAL ;
    PORT
      LAYER Metal3 ;
        RECT 0.0000 317.5500 0.2900 317.6200 ;
    END
  END ahbso_in_326
  PIN ahbso_in_325
    DIRECTION INPUT ;
    USE SIGNAL ;
    PORT
      LAYER Metal4 ;
        RECT 67.2650 363.9400 67.3350 364.2300 ;
    END
  END ahbso_in_325
  PIN ahbso_in_324
    DIRECTION INPUT ;
    USE SIGNAL ;
    PORT
      LAYER Metal5 ;
        RECT 0.0000 317.7400 0.2900 317.8100 ;
    END
  END ahbso_in_324
  PIN ahbso_in_323
    DIRECTION INPUT ;
    USE SIGNAL ;
    PORT
      LAYER Metal5 ;
        RECT 0.0000 318.6900 0.2900 318.7600 ;
    END
  END ahbso_in_323
  PIN ahbso_in_322
    DIRECTION INPUT ;
    USE SIGNAL ;
    PORT
      LAYER Metal5 ;
        RECT 0.0000 319.0700 0.2900 319.1400 ;
    END
  END ahbso_in_322
  PIN ahbso_in_321
    DIRECTION INPUT ;
    USE SIGNAL ;
    PORT
      LAYER Metal6 ;
        RECT 1.0650 363.9400 1.1350 364.2300 ;
    END
  END ahbso_in_321
  PIN ahbso_in_320
    DIRECTION INPUT ;
    USE SIGNAL ;
    PORT
      LAYER Metal6 ;
        RECT 1.4650 363.9400 1.5350 364.2300 ;
    END
  END ahbso_in_320
  PIN ahbso_in_319
    DIRECTION INPUT ;
    USE SIGNAL ;
    PORT
      LAYER Metal6 ;
        RECT 1.8650 363.9400 1.9350 364.2300 ;
    END
  END ahbso_in_319
  PIN ahbso_in_318
    DIRECTION INPUT ;
    USE SIGNAL ;
    PORT
      LAYER Metal6 ;
        RECT 2.2650 363.9400 2.3350 364.2300 ;
    END
  END ahbso_in_318
  PIN ahbso_in_317
    DIRECTION INPUT ;
    USE SIGNAL ;
    PORT
      LAYER Metal6 ;
        RECT 2.6650 363.9400 2.7350 364.2300 ;
    END
  END ahbso_in_317
  PIN ahbso_in_316
    DIRECTION INPUT ;
    USE SIGNAL ;
    PORT
      LAYER Metal6 ;
        RECT 3.0650 363.9400 3.1350 364.2300 ;
    END
  END ahbso_in_316
  PIN ahbso_in_315
    DIRECTION INPUT ;
    USE SIGNAL ;
    PORT
      LAYER Metal6 ;
        RECT 3.4650 363.9400 3.5350 364.2300 ;
    END
  END ahbso_in_315
  PIN ahbso_in_314
    DIRECTION INPUT ;
    USE SIGNAL ;
    PORT
      LAYER Metal6 ;
        RECT 3.8650 363.9400 3.9350 364.2300 ;
    END
  END ahbso_in_314
  PIN ahbso_in_313
    DIRECTION INPUT ;
    USE SIGNAL ;
    PORT
      LAYER Metal6 ;
        RECT 4.2650 363.9400 4.3350 364.2300 ;
    END
  END ahbso_in_313
  PIN ahbso_in_312
    DIRECTION INPUT ;
    USE SIGNAL ;
    PORT
      LAYER Metal6 ;
        RECT 4.6650 363.9400 4.7350 364.2300 ;
    END
  END ahbso_in_312
  PIN ahbso_in_311
    DIRECTION INPUT ;
    USE SIGNAL ;
    PORT
      LAYER Metal6 ;
        RECT 5.0650 363.9400 5.1350 364.2300 ;
    END
  END ahbso_in_311
  PIN ahbso_in_310
    DIRECTION INPUT ;
    USE SIGNAL ;
    PORT
      LAYER Metal6 ;
        RECT 5.4650 363.9400 5.5350 364.2300 ;
    END
  END ahbso_in_310
  PIN ahbso_in_309
    DIRECTION INPUT ;
    USE SIGNAL ;
    PORT
      LAYER Metal6 ;
        RECT 5.8650 363.9400 5.9350 364.2300 ;
    END
  END ahbso_in_309
  PIN ahbso_in_308
    DIRECTION INPUT ;
    USE SIGNAL ;
    PORT
      LAYER Metal6 ;
        RECT 6.2650 363.9400 6.3350 364.2300 ;
    END
  END ahbso_in_308
  PIN ahbso_in_307
    DIRECTION INPUT ;
    USE SIGNAL ;
    PORT
      LAYER Metal6 ;
        RECT 6.6650 363.9400 6.7350 364.2300 ;
    END
  END ahbso_in_307
  PIN ahbso_in_306
    DIRECTION INPUT ;
    USE SIGNAL ;
    PORT
      LAYER Metal6 ;
        RECT 7.0650 363.9400 7.1350 364.2300 ;
    END
  END ahbso_in_306
  PIN ahbso_in_305
    DIRECTION INPUT ;
    USE SIGNAL ;
    PORT
      LAYER Metal5 ;
        RECT 0.0000 293.0400 0.2900 293.1100 ;
    END
  END ahbso_in_305
  PIN ahbso_in_303
    DIRECTION INPUT ;
    USE SIGNAL ;
    PORT
      LAYER Metal3 ;
        RECT 0.0000 293.0400 0.2900 293.1100 ;
    END
  END ahbso_in_303
  PIN ahbso_in_302
    DIRECTION INPUT ;
    USE SIGNAL ;
    PORT
      LAYER Metal2 ;
        RECT 164.2650 363.9400 164.3350 364.2300 ;
    END
  END ahbso_in_302
  PIN ahbso_in_301
    DIRECTION INPUT ;
    USE SIGNAL ;
    PORT
      LAYER Metal2 ;
        RECT 148.2650 363.9400 148.3350 364.2300 ;
    END
  END ahbso_in_301
  PIN ahbso_in_300
    DIRECTION INPUT ;
    USE SIGNAL ;
    PORT
      LAYER Metal2 ;
        RECT 143.4650 363.9400 143.5350 364.2300 ;
    END
  END ahbso_in_300
  PIN ahbso_in_299
    DIRECTION INPUT ;
    USE SIGNAL ;
    PORT
      LAYER Metal4 ;
        RECT 139.2650 363.9400 139.3350 364.2300 ;
    END
  END ahbso_in_299
  PIN ahbso_in_298
    DIRECTION INPUT ;
    USE SIGNAL ;
    PORT
      LAYER Metal4 ;
        RECT 137.2650 363.9400 137.3350 364.2300 ;
    END
  END ahbso_in_298
  PIN ahbso_in_297
    DIRECTION INPUT ;
    USE SIGNAL ;
    PORT
      LAYER Metal9 ;
        RECT 0.0000 293.4200 0.2900 293.4900 ;
    END
  END ahbso_in_297
  PIN ahbso_in_296
    DIRECTION INPUT ;
    USE SIGNAL ;
    PORT
      LAYER Metal5 ;
        RECT 0.0000 293.4200 0.2900 293.4900 ;
    END
  END ahbso_in_296
  PIN ahbso_in_295
    DIRECTION INPUT ;
    USE SIGNAL ;
    PORT
      LAYER Metal3 ;
        RECT 0.0000 293.4200 0.2900 293.4900 ;
    END
  END ahbso_in_295
  PIN ahbso_in_294
    DIRECTION INPUT ;
    USE SIGNAL ;
    PORT
      LAYER Metal2 ;
        RECT 125.2650 363.9400 125.3350 364.2300 ;
    END
  END ahbso_in_294
  PIN ahbso_in_293
    DIRECTION INPUT ;
    USE SIGNAL ;
    PORT
      LAYER Metal5 ;
        RECT 0.0000 293.8000 0.2900 293.8700 ;
    END
  END ahbso_in_293
  PIN ahbso_in_292
    DIRECTION INPUT ;
    USE SIGNAL ;
    PORT
      LAYER Metal9 ;
        RECT 0.0000 294.1800 0.2900 294.2500 ;
    END
  END ahbso_in_292
  PIN ahbso_in_291
    DIRECTION INPUT ;
    USE SIGNAL ;
    PORT
      LAYER Metal5 ;
        RECT 0.0000 294.1800 0.2900 294.2500 ;
    END
  END ahbso_in_291
  PIN ahbso_in_290
    DIRECTION INPUT ;
    USE SIGNAL ;
    PORT
      LAYER Metal3 ;
        RECT 0.0000 294.1800 0.2900 294.2500 ;
    END
  END ahbso_in_290
  PIN ahbso_in_289
    DIRECTION INPUT ;
    USE SIGNAL ;
    PORT
      LAYER Metal5 ;
        RECT 0.0000 294.5600 0.2900 294.6300 ;
    END
  END ahbso_in_289
  PIN ahbso_in_288
    DIRECTION INPUT ;
    USE SIGNAL ;
    PORT
      LAYER Metal3 ;
        RECT 0.0000 294.5600 0.2900 294.6300 ;
    END
  END ahbso_in_288
  PIN ahbso_in_287
    DIRECTION INPUT ;
    USE SIGNAL ;
    PORT
      LAYER Metal9 ;
        RECT 0.0000 294.9400 0.2900 295.0100 ;
    END
  END ahbso_in_287
  PIN ahbso_in_286
    DIRECTION INPUT ;
    USE SIGNAL ;
    PORT
      LAYER Metal5 ;
        RECT 0.0000 294.9400 0.2900 295.0100 ;
    END
  END ahbso_in_286
  PIN ahbso_in_285
    DIRECTION INPUT ;
    USE SIGNAL ;
    PORT
      LAYER Metal3 ;
        RECT 0.0000 294.9400 0.2900 295.0100 ;
    END
  END ahbso_in_285
  PIN ahbso_in_284
    DIRECTION INPUT ;
    USE SIGNAL ;
    PORT
      LAYER Metal5 ;
        RECT 0.0000 295.3200 0.2900 295.3900 ;
    END
  END ahbso_in_284
  PIN ahbso_in_283
    DIRECTION INPUT ;
    USE SIGNAL ;
    PORT
      LAYER Metal3 ;
        RECT 0.0000 295.3200 0.2900 295.3900 ;
    END
  END ahbso_in_283
  PIN ahbso_in_282
    DIRECTION INPUT ;
    USE SIGNAL ;
    PORT
      LAYER Metal9 ;
        RECT 0.0000 295.7000 0.2900 295.7700 ;
    END
  END ahbso_in_282
  PIN ahbso_in_281
    DIRECTION INPUT ;
    USE SIGNAL ;
    PORT
      LAYER Metal5 ;
        RECT 0.0000 295.7000 0.2900 295.7700 ;
    END
  END ahbso_in_281
  PIN ahbso_in_280
    DIRECTION INPUT ;
    USE SIGNAL ;
    PORT
      LAYER Metal5 ;
        RECT 0.0000 296.0800 0.2900 296.1500 ;
    END
  END ahbso_in_280
  PIN ahbso_in_279
    DIRECTION INPUT ;
    USE SIGNAL ;
    PORT
      LAYER Metal3 ;
        RECT 0.0000 296.0800 0.2900 296.1500 ;
    END
  END ahbso_in_279
  PIN ahbso_in_278
    DIRECTION INPUT ;
    USE SIGNAL ;
    PORT
      LAYER Metal9 ;
        RECT 0.0000 296.4600 0.2900 296.5300 ;
    END
  END ahbso_in_278
  PIN ahbso_in_277
    DIRECTION INPUT ;
    USE SIGNAL ;
    PORT
      LAYER Metal5 ;
        RECT 0.0000 296.4600 0.2900 296.5300 ;
    END
  END ahbso_in_277
  PIN ahbso_in_276
    DIRECTION INPUT ;
    USE SIGNAL ;
    PORT
      LAYER Metal2 ;
        RECT 154.2650 363.9400 154.3350 364.2300 ;
    END
  END ahbso_in_276
  PIN ahbso_in_275
    DIRECTION INPUT ;
    USE SIGNAL ;
    PORT
      LAYER Metal2 ;
        RECT 149.2650 363.9400 149.3350 364.2300 ;
    END
  END ahbso_in_275
  PIN ahbso_in_274
    DIRECTION INPUT ;
    USE SIGNAL ;
    PORT
      LAYER Metal3 ;
        RECT 0.0000 296.4600 0.2900 296.5300 ;
    END
  END ahbso_in_274
  PIN ahbso_in_273
    DIRECTION INPUT ;
    USE SIGNAL ;
    PORT
      LAYER Metal5 ;
        RECT 0.0000 296.8400 0.2900 296.9100 ;
    END
  END ahbso_in_273
  PIN ahbso_in_272
    DIRECTION INPUT ;
    USE SIGNAL ;
    PORT
      LAYER Metal4 ;
        RECT 133.2650 363.9400 133.3350 364.2300 ;
    END
  END ahbso_in_272
  PIN ahbso_in_271
    DIRECTION INPUT ;
    USE SIGNAL ;
    PORT
      LAYER Metal2 ;
        RECT 155.2650 363.9400 155.3350 364.2300 ;
    END
  END ahbso_in_271
  PIN ahbso_in_270
    DIRECTION INPUT ;
    USE SIGNAL ;
    PORT
      LAYER Metal6 ;
        RECT 7.4650 363.9400 7.5350 364.2300 ;
    END
  END ahbso_in_270
  PIN ahbso_in_269
    DIRECTION INPUT ;
    USE SIGNAL ;
    PORT
      LAYER Metal6 ;
        RECT 7.8650 363.9400 7.9350 364.2300 ;
    END
  END ahbso_in_269
  PIN ahbso_in_268
    DIRECTION INPUT ;
    USE SIGNAL ;
    PORT
      LAYER Metal6 ;
        RECT 8.2650 363.9400 8.3350 364.2300 ;
    END
  END ahbso_in_268
  PIN ahbso_in_267
    DIRECTION INPUT ;
    USE SIGNAL ;
    PORT
      LAYER Metal6 ;
        RECT 8.6650 363.9400 8.7350 364.2300 ;
    END
  END ahbso_in_267
  PIN ahbso_in_266
    DIRECTION INPUT ;
    USE SIGNAL ;
    PORT
      LAYER Metal6 ;
        RECT 9.0650 363.9400 9.1350 364.2300 ;
    END
  END ahbso_in_266
  PIN ahbso_in_265
    DIRECTION INPUT ;
    USE SIGNAL ;
    PORT
      LAYER Metal6 ;
        RECT 9.4650 363.9400 9.5350 364.2300 ;
    END
  END ahbso_in_265
  PIN ahbso_in_264
    DIRECTION INPUT ;
    USE SIGNAL ;
    PORT
      LAYER Metal6 ;
        RECT 9.8650 363.9400 9.9350 364.2300 ;
    END
  END ahbso_in_264
  PIN ahbso_in_263
    DIRECTION INPUT ;
    USE SIGNAL ;
    PORT
      LAYER Metal6 ;
        RECT 10.2650 363.9400 10.3350 364.2300 ;
    END
  END ahbso_in_263
  PIN ahbso_in_262
    DIRECTION INPUT ;
    USE SIGNAL ;
    PORT
      LAYER Metal6 ;
        RECT 11.0650 363.9400 11.1350 364.2300 ;
    END
  END ahbso_in_262
  PIN ahbso_in_261
    DIRECTION INPUT ;
    USE SIGNAL ;
    PORT
      LAYER Metal6 ;
        RECT 11.4650 363.9400 11.5350 364.2300 ;
    END
  END ahbso_in_261
  PIN ahbso_in_260
    DIRECTION INPUT ;
    USE SIGNAL ;
    PORT
      LAYER Metal6 ;
        RECT 11.8650 363.9400 11.9350 364.2300 ;
    END
  END ahbso_in_260
  PIN ahbso_in_259
    DIRECTION INPUT ;
    USE SIGNAL ;
    PORT
      LAYER Metal6 ;
        RECT 12.2650 363.9400 12.3350 364.2300 ;
    END
  END ahbso_in_259
  PIN ahbso_in_258
    DIRECTION INPUT ;
    USE SIGNAL ;
    PORT
      LAYER Metal6 ;
        RECT 12.6650 363.9400 12.7350 364.2300 ;
    END
  END ahbso_in_258
  PIN ahbso_in_257
    DIRECTION INPUT ;
    USE SIGNAL ;
    PORT
      LAYER Metal6 ;
        RECT 13.0650 363.9400 13.1350 364.2300 ;
    END
  END ahbso_in_257
  PIN ahbso_in_256
    DIRECTION INPUT ;
    USE SIGNAL ;
    PORT
      LAYER Metal6 ;
        RECT 13.4650 363.9400 13.5350 364.2300 ;
    END
  END ahbso_in_256
  PIN ahbso_in_255
    DIRECTION INPUT ;
    USE SIGNAL ;
    PORT
      LAYER Metal6 ;
        RECT 13.8650 363.9400 13.9350 364.2300 ;
    END
  END ahbso_in_255
  PIN ahbso_in_254
    DIRECTION INPUT ;
    USE SIGNAL ;
    PORT
      LAYER Metal3 ;
        RECT 0.0000 293.8000 0.2900 293.8700 ;
    END
  END ahbso_in_254
  PIN ahbso_in_253
    DIRECTION INPUT ;
    USE SIGNAL ;
    PORT
      LAYER Metal3 ;
        RECT 0.0000 305.2000 0.2900 305.2700 ;
    END
  END ahbso_in_253
  PIN ahbso_in_252
    DIRECTION INPUT ;
    USE SIGNAL ;
    PORT
      LAYER Metal3 ;
        RECT 0.0000 304.8200 0.2900 304.8900 ;
    END
  END ahbso_in_252
  PIN ahbso_in_251
    DIRECTION INPUT ;
    USE SIGNAL ;
    PORT
      LAYER Metal3 ;
        RECT 0.0000 301.4000 0.2900 301.4700 ;
    END
  END ahbso_in_251
  PIN ahbso_in_250
    DIRECTION INPUT ;
    USE SIGNAL ;
    PORT
      LAYER Metal3 ;
        RECT 0.0000 307.8600 0.2900 307.9300 ;
    END
  END ahbso_in_250
  PIN ahbso_in_249
    DIRECTION INPUT ;
    USE SIGNAL ;
    PORT
      LAYER Metal2 ;
        RECT 156.2650 363.9400 156.3350 364.2300 ;
    END
  END ahbso_in_249
  PIN ahbso_in_248
    DIRECTION INPUT ;
    USE SIGNAL ;
    PORT
      LAYER Metal3 ;
        RECT 0.0000 322.3000 0.2900 322.3700 ;
    END
  END ahbso_in_248
  PIN ahbso_in_247
    DIRECTION INPUT ;
    USE SIGNAL ;
    PORT
      LAYER Metal2 ;
        RECT 136.2650 363.9400 136.3350 364.2300 ;
    END
  END ahbso_in_247
  PIN ahbso_in_246
    DIRECTION INPUT ;
    USE SIGNAL ;
    PORT
      LAYER Metal5 ;
        RECT 0.0000 323.4400 0.2900 323.5100 ;
    END
  END ahbso_in_246
  PIN ahbso_in_245
    DIRECTION INPUT ;
    USE SIGNAL ;
    PORT
      LAYER Metal5 ;
        RECT 0.0000 326.4800 0.2900 326.5500 ;
    END
  END ahbso_in_245
  PIN ahbso_in_244
    DIRECTION INPUT ;
    USE SIGNAL ;
    PORT
      LAYER Metal3 ;
        RECT 0.0000 334.0800 0.2900 334.1500 ;
    END
  END ahbso_in_244
  PIN ahbso_in_243
    DIRECTION INPUT ;
    USE SIGNAL ;
    PORT
      LAYER Metal5 ;
        RECT 0.0000 335.7900 0.2900 335.8600 ;
    END
  END ahbso_in_243
  PIN ahbso_in_242
    DIRECTION INPUT ;
    USE SIGNAL ;
    PORT
      LAYER Metal2 ;
        RECT 106.2650 363.9400 106.3350 364.2300 ;
    END
  END ahbso_in_242
  PIN ahbso_in_241
    DIRECTION INPUT ;
    USE SIGNAL ;
    PORT
      LAYER Metal3 ;
        RECT 0.0000 340.9200 0.2900 340.9900 ;
    END
  END ahbso_in_241
  PIN ahbso_in_240
    DIRECTION INPUT ;
    USE SIGNAL ;
    PORT
      LAYER Metal5 ;
        RECT 0.0000 336.3600 0.2900 336.4300 ;
    END
  END ahbso_in_240
  PIN ahbso_in_239
    DIRECTION INPUT ;
    USE SIGNAL ;
    PORT
      LAYER Metal5 ;
        RECT 0.0000 336.7400 0.2900 336.8100 ;
    END
  END ahbso_in_239
  PIN ahbso_in_238
    DIRECTION INPUT ;
    USE SIGNAL ;
    PORT
      LAYER Metal9 ;
        RECT 0.0000 344.3400 0.2900 344.4100 ;
    END
  END ahbso_in_238
  PIN ahbso_in_237
    DIRECTION INPUT ;
    USE SIGNAL ;
    PORT
      LAYER Metal3 ;
        RECT 0.0000 357.6400 0.2900 357.7100 ;
    END
  END ahbso_in_237
  PIN ahbso_in_236
    DIRECTION INPUT ;
    USE SIGNAL ;
    PORT
      LAYER Metal2 ;
        RECT 83.2650 363.9400 83.3350 364.2300 ;
    END
  END ahbso_in_236
  PIN ahbso_in_235
    DIRECTION INPUT ;
    USE SIGNAL ;
    PORT
      LAYER Metal5 ;
        RECT 0.0000 345.4800 0.2900 345.5500 ;
    END
  END ahbso_in_235
  PIN ahbso_in_234
    DIRECTION INPUT ;
    USE SIGNAL ;
    PORT
      LAYER Metal5 ;
        RECT 0.0000 330.0900 0.2900 330.1600 ;
    END
  END ahbso_in_234
  PIN ahbso_in_233
    DIRECTION INPUT ;
    USE SIGNAL ;
    PORT
      LAYER Metal2 ;
        RECT 124.2650 363.9400 124.3350 364.2300 ;
    END
  END ahbso_in_233
  PIN ahbso_in_232
    DIRECTION INPUT ;
    USE SIGNAL ;
    PORT
      LAYER Metal3 ;
        RECT 0.0000 330.6600 0.2900 330.7300 ;
    END
  END ahbso_in_232
  PIN ahbso_in_231
    DIRECTION INPUT ;
    USE SIGNAL ;
    PORT
      LAYER Metal3 ;
        RECT 0.0000 331.0400 0.2900 331.1100 ;
    END
  END ahbso_in_231
  PIN ahbso_in_230
    DIRECTION INPUT ;
    USE SIGNAL ;
    PORT
      LAYER Metal2 ;
        RECT 128.2650 363.9400 128.3350 364.2300 ;
    END
  END ahbso_in_230
  PIN ahbso_in_229
    DIRECTION INPUT ;
    USE SIGNAL ;
    PORT
      LAYER Metal5 ;
        RECT 0.0000 326.8600 0.2900 326.9300 ;
    END
  END ahbso_in_229
  PIN ahbso_in_228
    DIRECTION INPUT ;
    USE SIGNAL ;
    PORT
      LAYER Metal3 ;
        RECT 0.0000 320.4000 0.2900 320.4700 ;
    END
  END ahbso_in_228
  PIN ahbso_in_227
    DIRECTION INPUT ;
    USE SIGNAL ;
    PORT
      LAYER Metal3 ;
        RECT 0.0000 314.1300 0.2900 314.2000 ;
    END
  END ahbso_in_227
  PIN ahbso_in_226
    DIRECTION INPUT ;
    USE SIGNAL ;
    PORT
      LAYER Metal2 ;
        RECT 152.2650 363.9400 152.3350 364.2300 ;
    END
  END ahbso_in_226
  PIN ahbso_in_225
    DIRECTION INPUT ;
    USE SIGNAL ;
    PORT
      LAYER Metal5 ;
        RECT 0.0000 328.0000 0.2900 328.0700 ;
    END
  END ahbso_in_225
  PIN ahbso_in_224
    DIRECTION INPUT ;
    USE SIGNAL ;
    PORT
      LAYER Metal3 ;
        RECT 0.0000 315.4600 0.2900 315.5300 ;
    END
  END ahbso_in_224
  PIN ahbso_in_223
    DIRECTION INPUT ;
    USE SIGNAL ;
    PORT
      LAYER Metal3 ;
        RECT 0.0000 310.9000 0.2900 310.9700 ;
    END
  END ahbso_in_223
  PIN ahbso_in_222
    DIRECTION INPUT ;
    USE SIGNAL ;
    PORT
      LAYER Metal3 ;
        RECT 0.0000 301.0200 0.2900 301.0900 ;
    END
  END ahbso_in_222
  PIN ahbso_in_221
    DIRECTION INPUT ;
    USE SIGNAL ;
    PORT
      LAYER Metal3 ;
        RECT 0.0000 334.4600 0.2900 334.5300 ;
    END
  END ahbso_in_221
  PIN ahbso_in_220
    DIRECTION INPUT ;
    USE SIGNAL ;
    PORT
      LAYER Metal3 ;
        RECT 0.0000 330.2800 0.2900 330.3500 ;
    END
  END ahbso_in_220
  PIN ahbso_in_219
    DIRECTION INPUT ;
    USE SIGNAL ;
    PORT
      LAYER Metal6 ;
        RECT 14.2650 363.9400 14.3350 364.2300 ;
    END
  END ahbso_in_219
  PIN ahbso_in_218
    DIRECTION INPUT ;
    USE SIGNAL ;
    PORT
      LAYER Metal6 ;
        RECT 14.6650 363.9400 14.7350 364.2300 ;
    END
  END ahbso_in_218
  PIN ahbso_in_217
    DIRECTION INPUT ;
    USE SIGNAL ;
    PORT
      LAYER Metal6 ;
        RECT 15.0650 363.9400 15.1350 364.2300 ;
    END
  END ahbso_in_217
  PIN ahbso_in_216
    DIRECTION INPUT ;
    USE SIGNAL ;
    PORT
      LAYER Metal6 ;
        RECT 15.4650 363.9400 15.5350 364.2300 ;
    END
  END ahbso_in_216
  PIN ahbso_in_215
    DIRECTION INPUT ;
    USE SIGNAL ;
    PORT
      LAYER Metal6 ;
        RECT 15.8650 363.9400 15.9350 364.2300 ;
    END
  END ahbso_in_215
  PIN ahbso_in_214
    DIRECTION INPUT ;
    USE SIGNAL ;
    PORT
      LAYER Metal6 ;
        RECT 16.2650 363.9400 16.3350 364.2300 ;
    END
  END ahbso_in_214
  PIN ahbso_in_213
    DIRECTION INPUT ;
    USE SIGNAL ;
    PORT
      LAYER Metal6 ;
        RECT 16.6650 363.9400 16.7350 364.2300 ;
    END
  END ahbso_in_213
  PIN ahbso_in_212
    DIRECTION INPUT ;
    USE SIGNAL ;
    PORT
      LAYER Metal6 ;
        RECT 17.0650 363.9400 17.1350 364.2300 ;
    END
  END ahbso_in_212
  PIN ahbso_in_211
    DIRECTION INPUT ;
    USE SIGNAL ;
    PORT
      LAYER Metal6 ;
        RECT 17.4650 363.9400 17.5350 364.2300 ;
    END
  END ahbso_in_211
  PIN ahbso_in_210
    DIRECTION INPUT ;
    USE SIGNAL ;
    PORT
      LAYER Metal6 ;
        RECT 17.8650 363.9400 17.9350 364.2300 ;
    END
  END ahbso_in_210
  PIN ahbso_in_209
    DIRECTION INPUT ;
    USE SIGNAL ;
    PORT
      LAYER Metal6 ;
        RECT 18.2650 363.9400 18.3350 364.2300 ;
    END
  END ahbso_in_209
  PIN ahbso_in_208
    DIRECTION INPUT ;
    USE SIGNAL ;
    PORT
      LAYER Metal6 ;
        RECT 18.6650 363.9400 18.7350 364.2300 ;
    END
  END ahbso_in_208
  PIN ahbso_in_207
    DIRECTION INPUT ;
    USE SIGNAL ;
    PORT
      LAYER Metal6 ;
        RECT 19.0650 363.9400 19.1350 364.2300 ;
    END
  END ahbso_in_207
  PIN ahbso_in_206
    DIRECTION INPUT ;
    USE SIGNAL ;
    PORT
      LAYER Metal6 ;
        RECT 19.4650 363.9400 19.5350 364.2300 ;
    END
  END ahbso_in_206
  PIN ahbso_in_205
    DIRECTION INPUT ;
    USE SIGNAL ;
    PORT
      LAYER Metal6 ;
        RECT 19.8650 363.9400 19.9350 364.2300 ;
    END
  END ahbso_in_205
  PIN ahbso_in_204
    DIRECTION INPUT ;
    USE SIGNAL ;
    PORT
      LAYER Metal4 ;
        RECT 1.0650 363.9400 1.1350 364.2300 ;
    END
  END ahbso_in_204
  PIN ahbso_in_203
    DIRECTION INPUT ;
    USE SIGNAL ;
    PORT
      LAYER Metal2 ;
        RECT 154.6650 363.9400 154.7350 364.2300 ;
    END
  END ahbso_in_203
  PIN ahbso_in_201
    DIRECTION INPUT ;
    USE SIGNAL ;
    PORT
      LAYER Metal2 ;
        RECT 65.6650 363.9400 65.7350 364.2300 ;
    END
  END ahbso_in_201
  PIN ahbso_in_200
    DIRECTION INPUT ;
    USE SIGNAL ;
    PORT
      LAYER Metal3 ;
        RECT 0.0000 247.4400 0.2900 247.5100 ;
    END
  END ahbso_in_200
  PIN ahbso_in_199
    DIRECTION INPUT ;
    USE SIGNAL ;
    PORT
      LAYER Metal5 ;
        RECT 0.0000 247.2500 0.2900 247.3200 ;
    END
  END ahbso_in_199
  PIN ahbso_in_198
    DIRECTION INPUT ;
    USE SIGNAL ;
    PORT
      LAYER Metal3 ;
        RECT 0.0000 241.3600 0.2900 241.4300 ;
    END
  END ahbso_in_198
  PIN ahbso_in_197
    DIRECTION INPUT ;
    USE SIGNAL ;
    PORT
      LAYER Metal5 ;
        RECT 0.0000 229.5800 0.2900 229.6500 ;
    END
  END ahbso_in_197
  PIN ahbso_in_196
    DIRECTION INPUT ;
    USE SIGNAL ;
    PORT
      LAYER Metal3 ;
        RECT 0.0000 225.7800 0.2900 225.8500 ;
    END
  END ahbso_in_196
  PIN ahbso_in_195
    DIRECTION INPUT ;
    USE SIGNAL ;
    PORT
      LAYER Metal3 ;
        RECT 0.0000 222.9300 0.2900 223.0000 ;
    END
  END ahbso_in_195
  PIN ahbso_in_194
    DIRECTION INPUT ;
    USE SIGNAL ;
    PORT
      LAYER Metal9 ;
        RECT 0.0000 220.0800 0.2900 220.1500 ;
    END
  END ahbso_in_194
  PIN ahbso_in_193
    DIRECTION INPUT ;
    USE SIGNAL ;
    PORT
      LAYER Metal3 ;
        RECT 0.0000 212.6700 0.2900 212.7400 ;
    END
  END ahbso_in_193
  PIN ahbso_in_192
    DIRECTION INPUT ;
    USE SIGNAL ;
    PORT
      LAYER Metal5 ;
        RECT 0.0000 219.8900 0.2900 219.9600 ;
    END
  END ahbso_in_192
  PIN ahbso_in_191
    DIRECTION INPUT ;
    USE SIGNAL ;
    PORT
      LAYER Metal5 ;
        RECT 0.0000 217.8000 0.2900 217.8700 ;
    END
  END ahbso_in_191
  PIN ahbso_in_190
    DIRECTION INPUT ;
    USE SIGNAL ;
    PORT
      LAYER Metal3 ;
        RECT 0.0000 219.8900 0.2900 219.9600 ;
    END
  END ahbso_in_190
  PIN ahbso_in_189
    DIRECTION INPUT ;
    USE SIGNAL ;
    PORT
      LAYER Metal3 ;
        RECT 0.0000 217.8000 0.2900 217.8700 ;
    END
  END ahbso_in_189
  PIN ahbso_in_188
    DIRECTION INPUT ;
    USE SIGNAL ;
    PORT
      LAYER Metal3 ;
        RECT 0.0000 210.9600 0.2900 211.0300 ;
    END
  END ahbso_in_188
  PIN ahbso_in_187
    DIRECTION INPUT ;
    USE SIGNAL ;
    PORT
      LAYER Metal5 ;
        RECT 0.0000 206.2100 0.2900 206.2800 ;
    END
  END ahbso_in_187
  PIN ahbso_in_186
    DIRECTION INPUT ;
    USE SIGNAL ;
    PORT
      LAYER Metal3 ;
        RECT 0.0000 207.5400 0.2900 207.6100 ;
    END
  END ahbso_in_186
  PIN ahbso_in_185
    DIRECTION INPUT ;
    USE SIGNAL ;
    PORT
      LAYER Metal9 ;
        RECT 0.0000 204.1200 0.2900 204.1900 ;
    END
  END ahbso_in_185
  PIN ahbso_in_184
    DIRECTION INPUT ;
    USE SIGNAL ;
    PORT
      LAYER Metal3 ;
        RECT 0.0000 206.2100 0.2900 206.2800 ;
    END
  END ahbso_in_184
  PIN ahbso_in_183
    DIRECTION INPUT ;
    USE SIGNAL ;
    PORT
      LAYER Metal5 ;
        RECT 0.0000 204.1200 0.2900 204.1900 ;
    END
  END ahbso_in_183
  PIN ahbso_in_182
    DIRECTION INPUT ;
    USE SIGNAL ;
    PORT
      LAYER Metal3 ;
        RECT 0.0000 204.1200 0.2900 204.1900 ;
    END
  END ahbso_in_182
  PIN ahbso_in_181
    DIRECTION INPUT ;
    USE SIGNAL ;
    PORT
      LAYER Metal5 ;
        RECT 0.0000 213.0500 0.2900 213.1200 ;
    END
  END ahbso_in_181
  PIN ahbso_in_180
    DIRECTION INPUT ;
    USE SIGNAL ;
    PORT
      LAYER Metal3 ;
        RECT 0.0000 214.3800 0.2900 214.4500 ;
    END
  END ahbso_in_180
  PIN ahbso_in_179
    DIRECTION INPUT ;
    USE SIGNAL ;
    PORT
      LAYER Metal3 ;
        RECT 0.0000 213.0500 0.2900 213.1200 ;
    END
  END ahbso_in_179
  PIN ahbso_in_178
    DIRECTION INPUT ;
    USE SIGNAL ;
    PORT
      LAYER Metal5 ;
        RECT 0.0000 223.3100 0.2900 223.3800 ;
    END
  END ahbso_in_178
  PIN ahbso_in_177
    DIRECTION INPUT ;
    USE SIGNAL ;
    PORT
      LAYER Metal5 ;
        RECT 0.0000 224.6400 0.2900 224.7100 ;
    END
  END ahbso_in_177
  PIN ahbso_in_176
    DIRECTION INPUT ;
    USE SIGNAL ;
    PORT
      LAYER Metal5 ;
        RECT 0.0000 229.2000 0.2900 229.2700 ;
    END
  END ahbso_in_176
  PIN ahbso_in_175
    DIRECTION INPUT ;
    USE SIGNAL ;
    PORT
      LAYER Metal3 ;
        RECT 0.0000 232.0500 0.2900 232.1200 ;
    END
  END ahbso_in_175
  PIN ahbso_in_174
    DIRECTION INPUT ;
    USE SIGNAL ;
    PORT
      LAYER Metal3 ;
        RECT 0.0000 233.7600 0.2900 233.8300 ;
    END
  END ahbso_in_174
  PIN ahbso_in_173
    DIRECTION INPUT ;
    USE SIGNAL ;
    PORT
      LAYER Metal5 ;
        RECT 0.0000 236.9900 0.2900 237.0600 ;
    END
  END ahbso_in_173
  PIN ahbso_in_172
    DIRECTION INPUT ;
    USE SIGNAL ;
    PORT
      LAYER Metal5 ;
        RECT 0.0000 238.1300 0.2900 238.2000 ;
    END
  END ahbso_in_172
  PIN ahbso_in_171
    DIRECTION INPUT ;
    USE SIGNAL ;
    PORT
      LAYER Metal5 ;
        RECT 0.0000 241.9300 0.2900 242.0000 ;
    END
  END ahbso_in_171
  PIN ahbso_in_170
    DIRECTION INPUT ;
    USE SIGNAL ;
    PORT
      LAYER Metal9 ;
        RECT 0.0000 248.5800 0.2900 248.6500 ;
    END
  END ahbso_in_170
  PIN ahbso_in_169
    DIRECTION INPUT ;
    USE SIGNAL ;
    PORT
      LAYER Metal5 ;
        RECT 0.0000 244.9700 0.2900 245.0400 ;
    END
  END ahbso_in_169
  PIN ahbso_in_168
    DIRECTION INPUT ;
    USE SIGNAL ;
    PORT
      LAYER Metal6 ;
        RECT 20.2650 363.9400 20.3350 364.2300 ;
    END
  END ahbso_in_168
  PIN ahbso_in_167
    DIRECTION INPUT ;
    USE SIGNAL ;
    PORT
      LAYER Metal4 ;
        RECT 1.4650 363.9400 1.5350 364.2300 ;
    END
  END ahbso_in_167
  PIN ahbso_in_166
    DIRECTION INPUT ;
    USE SIGNAL ;
    PORT
      LAYER Metal6 ;
        RECT 20.6650 363.9400 20.7350 364.2300 ;
    END
  END ahbso_in_166
  PIN ahbso_in_165
    DIRECTION INPUT ;
    USE SIGNAL ;
    PORT
      LAYER Metal4 ;
        RECT 1.8650 363.9400 1.9350 364.2300 ;
    END
  END ahbso_in_165
  PIN ahbso_in_164
    DIRECTION INPUT ;
    USE SIGNAL ;
    PORT
      LAYER Metal6 ;
        RECT 21.0650 363.9400 21.1350 364.2300 ;
    END
  END ahbso_in_164
  PIN ahbso_in_163
    DIRECTION INPUT ;
    USE SIGNAL ;
    PORT
      LAYER Metal4 ;
        RECT 2.2650 363.9400 2.3350 364.2300 ;
    END
  END ahbso_in_163
  PIN ahbso_in_162
    DIRECTION INPUT ;
    USE SIGNAL ;
    PORT
      LAYER Metal6 ;
        RECT 21.4650 363.9400 21.5350 364.2300 ;
    END
  END ahbso_in_162
  PIN ahbso_in_161
    DIRECTION INPUT ;
    USE SIGNAL ;
    PORT
      LAYER Metal4 ;
        RECT 2.6650 363.9400 2.7350 364.2300 ;
    END
  END ahbso_in_161
  PIN ahbso_in_160
    DIRECTION INPUT ;
    USE SIGNAL ;
    PORT
      LAYER Metal6 ;
        RECT 21.8650 363.9400 21.9350 364.2300 ;
    END
  END ahbso_in_160
  PIN ahbso_in_159
    DIRECTION INPUT ;
    USE SIGNAL ;
    PORT
      LAYER Metal4 ;
        RECT 3.0650 363.9400 3.1350 364.2300 ;
    END
  END ahbso_in_159
  PIN ahbso_in_158
    DIRECTION INPUT ;
    USE SIGNAL ;
    PORT
      LAYER Metal6 ;
        RECT 22.2650 363.9400 22.3350 364.2300 ;
    END
  END ahbso_in_158
  PIN ahbso_in_157
    DIRECTION INPUT ;
    USE SIGNAL ;
    PORT
      LAYER Metal4 ;
        RECT 3.4650 363.9400 3.5350 364.2300 ;
    END
  END ahbso_in_157
  PIN ahbso_in_156
    DIRECTION INPUT ;
    USE SIGNAL ;
    PORT
      LAYER Metal6 ;
        RECT 22.6650 363.9400 22.7350 364.2300 ;
    END
  END ahbso_in_156
  PIN ahbso_in_155
    DIRECTION INPUT ;
    USE SIGNAL ;
    PORT
      LAYER Metal4 ;
        RECT 3.8650 363.9400 3.9350 364.2300 ;
    END
  END ahbso_in_155
  PIN ahbso_in_154
    DIRECTION INPUT ;
    USE SIGNAL ;
    PORT
      LAYER Metal6 ;
        RECT 23.0650 363.9400 23.1350 364.2300 ;
    END
  END ahbso_in_154
  PIN ahbso_in_153
    DIRECTION INPUT ;
    USE SIGNAL ;
    PORT
      LAYER Metal4 ;
        RECT 4.2650 363.9400 4.3350 364.2300 ;
    END
  END ahbso_in_153
  PIN ahbso_in_152
    DIRECTION INPUT ;
    USE SIGNAL ;
    PORT
      LAYER Metal4 ;
        RECT 198.6650 363.9400 198.7350 364.2300 ;
    END
  END ahbso_in_152
  PIN ahbso_in_150
    DIRECTION INPUT ;
    USE SIGNAL ;
    PORT
      LAYER Metal2 ;
        RECT 123.6650 363.9400 123.7350 364.2300 ;
    END
  END ahbso_in_150
  PIN ahbso_in_149
    DIRECTION INPUT ;
    USE SIGNAL ;
    PORT
      LAYER Metal4 ;
        RECT 229.4650 363.9400 229.5350 364.2300 ;
    END
  END ahbso_in_149
  PIN ahbso_in_148
    DIRECTION INPUT ;
    USE SIGNAL ;
    PORT
      LAYER Metal4 ;
        RECT 238.0650 363.9400 238.1350 364.2300 ;
    END
  END ahbso_in_148
  PIN ahbso_in_147
    DIRECTION INPUT ;
    USE SIGNAL ;
    PORT
      LAYER Metal4 ;
        RECT 253.2650 363.9400 253.3350 364.2300 ;
    END
  END ahbso_in_147
  PIN ahbso_in_146
    DIRECTION INPUT ;
    USE SIGNAL ;
    PORT
      LAYER Metal4 ;
        RECT 269.0650 363.9400 269.1350 364.2300 ;
    END
  END ahbso_in_146
  PIN ahbso_in_145
    DIRECTION INPUT ;
    USE SIGNAL ;
    PORT
      LAYER Metal2 ;
        RECT 275.8650 363.9400 275.9350 364.2300 ;
    END
  END ahbso_in_145
  PIN ahbso_in_144
    DIRECTION INPUT ;
    USE SIGNAL ;
    PORT
      LAYER Metal2 ;
        RECT 287.6650 363.9400 287.7350 364.2300 ;
    END
  END ahbso_in_144
  PIN ahbso_in_143
    DIRECTION INPUT ;
    USE SIGNAL ;
    PORT
      LAYER Metal2 ;
        RECT 289.8650 363.9400 289.9350 364.2300 ;
    END
  END ahbso_in_143
  PIN ahbso_in_142
    DIRECTION INPUT ;
    USE SIGNAL ;
    PORT
      LAYER Metal2 ;
        RECT 285.2650 363.9400 285.3350 364.2300 ;
    END
  END ahbso_in_142
  PIN ahbso_in_141
    DIRECTION INPUT ;
    USE SIGNAL ;
    PORT
      LAYER Metal2 ;
        RECT 276.4650 363.9400 276.5350 364.2300 ;
    END
  END ahbso_in_141
  PIN ahbso_in_140
    DIRECTION INPUT ;
    USE SIGNAL ;
    PORT
      LAYER Metal6 ;
        RECT 288.2650 363.9400 288.3350 364.2300 ;
    END
  END ahbso_in_140
  PIN ahbso_in_139
    DIRECTION INPUT ;
    USE SIGNAL ;
    PORT
      LAYER Metal2 ;
        RECT 296.0650 363.9400 296.1350 364.2300 ;
    END
  END ahbso_in_139
  PIN ahbso_in_138
    DIRECTION INPUT ;
    USE SIGNAL ;
    PORT
      LAYER Metal2 ;
        RECT 302.4650 363.9400 302.5350 364.2300 ;
    END
  END ahbso_in_138
  PIN ahbso_in_137
    DIRECTION INPUT ;
    USE SIGNAL ;
    PORT
      LAYER Metal2 ;
        RECT 306.8650 363.9400 306.9350 364.2300 ;
    END
  END ahbso_in_137
  PIN ahbso_in_136
    DIRECTION INPUT ;
    USE SIGNAL ;
    PORT
      LAYER Metal2 ;
        RECT 304.6650 363.9400 304.7350 364.2300 ;
    END
  END ahbso_in_136
  PIN ahbso_in_135
    DIRECTION INPUT ;
    USE SIGNAL ;
    PORT
      LAYER Metal4 ;
        RECT 288.2650 363.9400 288.3350 364.2300 ;
    END
  END ahbso_in_135
  PIN ahbso_in_134
    DIRECTION INPUT ;
    USE SIGNAL ;
    PORT
      LAYER Metal4 ;
        RECT 298.4650 363.9400 298.5350 364.2300 ;
    END
  END ahbso_in_134
  PIN ahbso_in_133
    DIRECTION INPUT ;
    USE SIGNAL ;
    PORT
      LAYER Metal4 ;
        RECT 299.4650 363.9400 299.5350 364.2300 ;
    END
  END ahbso_in_133
  PIN ahbso_in_132
    DIRECTION INPUT ;
    USE SIGNAL ;
    PORT
      LAYER Metal2 ;
        RECT 292.8650 363.9400 292.9350 364.2300 ;
    END
  END ahbso_in_132
  PIN ahbso_in_131
    DIRECTION INPUT ;
    USE SIGNAL ;
    PORT
      LAYER Metal2 ;
        RECT 298.4650 363.9400 298.5350 364.2300 ;
    END
  END ahbso_in_131
  PIN ahbso_in_130
    DIRECTION INPUT ;
    USE SIGNAL ;
    PORT
      LAYER Metal2 ;
        RECT 299.2650 363.9400 299.3350 364.2300 ;
    END
  END ahbso_in_130
  PIN ahbso_in_129
    DIRECTION INPUT ;
    USE SIGNAL ;
    PORT
      LAYER Metal2 ;
        RECT 293.6650 363.9400 293.7350 364.2300 ;
    END
  END ahbso_in_129
  PIN ahbso_in_128
    DIRECTION INPUT ;
    USE SIGNAL ;
    PORT
      LAYER Metal2 ;
        RECT 289.0650 363.9400 289.1350 364.2300 ;
    END
  END ahbso_in_128
  PIN ahbso_in_127
    DIRECTION INPUT ;
    USE SIGNAL ;
    PORT
      LAYER Metal2 ;
        RECT 266.4650 363.9400 266.5350 364.2300 ;
    END
  END ahbso_in_127
  PIN ahbso_in_126
    DIRECTION INPUT ;
    USE SIGNAL ;
    PORT
      LAYER Metal2 ;
        RECT 259.2650 363.9400 259.3350 364.2300 ;
    END
  END ahbso_in_126
  PIN ahbso_in_125
    DIRECTION INPUT ;
    USE SIGNAL ;
    PORT
      LAYER Metal2 ;
        RECT 241.0650 363.9400 241.1350 364.2300 ;
    END
  END ahbso_in_125
  PIN ahbso_in_124
    DIRECTION INPUT ;
    USE SIGNAL ;
    PORT
      LAYER Metal2 ;
        RECT 243.2650 363.9400 243.3350 364.2300 ;
    END
  END ahbso_in_124
  PIN ahbso_in_123
    DIRECTION INPUT ;
    USE SIGNAL ;
    PORT
      LAYER Metal2 ;
        RECT 261.6650 363.9400 261.7350 364.2300 ;
    END
  END ahbso_in_123
  PIN ahbso_in_122
    DIRECTION INPUT ;
    USE SIGNAL ;
    PORT
      LAYER Metal2 ;
        RECT 269.0650 363.9400 269.1350 364.2300 ;
    END
  END ahbso_in_122
  PIN ahbso_in_121
    DIRECTION INPUT ;
    USE SIGNAL ;
    PORT
      LAYER Metal2 ;
        RECT 223.6650 363.9400 223.7350 364.2300 ;
    END
  END ahbso_in_121
  PIN ahbso_in_120
    DIRECTION INPUT ;
    USE SIGNAL ;
    PORT
      LAYER Metal2 ;
        RECT 168.2650 363.9400 168.3350 364.2300 ;
    END
  END ahbso_in_120
  PIN ahbso_in_119
    DIRECTION INPUT ;
    USE SIGNAL ;
    PORT
      LAYER Metal4 ;
        RECT 23.0650 363.9400 23.1350 364.2300 ;
    END
  END ahbso_in_119
  PIN ahbso_in_118
    DIRECTION INPUT ;
    USE SIGNAL ;
    PORT
      LAYER Metal2 ;
        RECT 216.2650 363.9400 216.3350 364.2300 ;
    END
  END ahbso_in_118
  PIN ahbso_in_117
    DIRECTION INPUT ;
    USE SIGNAL ;
    PORT
      LAYER Metal6 ;
        RECT 23.4650 363.9400 23.5350 364.2300 ;
    END
  END ahbso_in_117
  PIN ahbso_in_116
    DIRECTION INPUT ;
    USE SIGNAL ;
    PORT
      LAYER Metal4 ;
        RECT 4.6650 363.9400 4.7350 364.2300 ;
    END
  END ahbso_in_116
  PIN ahbso_in_115
    DIRECTION INPUT ;
    USE SIGNAL ;
    PORT
      LAYER Metal6 ;
        RECT 23.8650 363.9400 23.9350 364.2300 ;
    END
  END ahbso_in_115
  PIN ahbso_in_114
    DIRECTION INPUT ;
    USE SIGNAL ;
    PORT
      LAYER Metal4 ;
        RECT 5.0650 363.9400 5.1350 364.2300 ;
    END
  END ahbso_in_114
  PIN ahbso_in_113
    DIRECTION INPUT ;
    USE SIGNAL ;
    PORT
      LAYER Metal6 ;
        RECT 24.2650 363.9400 24.3350 364.2300 ;
    END
  END ahbso_in_113
  PIN ahbso_in_112
    DIRECTION INPUT ;
    USE SIGNAL ;
    PORT
      LAYER Metal4 ;
        RECT 5.8650 363.9400 5.9350 364.2300 ;
    END
  END ahbso_in_112
  PIN ahbso_in_111
    DIRECTION INPUT ;
    USE SIGNAL ;
    PORT
      LAYER Metal6 ;
        RECT 24.6650 363.9400 24.7350 364.2300 ;
    END
  END ahbso_in_111
  PIN ahbso_in_110
    DIRECTION INPUT ;
    USE SIGNAL ;
    PORT
      LAYER Metal4 ;
        RECT 6.2650 363.9400 6.3350 364.2300 ;
    END
  END ahbso_in_110
  PIN ahbso_in_109
    DIRECTION INPUT ;
    USE SIGNAL ;
    PORT
      LAYER Metal6 ;
        RECT 25.0650 363.9400 25.1350 364.2300 ;
    END
  END ahbso_in_109
  PIN ahbso_in_108
    DIRECTION INPUT ;
    USE SIGNAL ;
    PORT
      LAYER Metal4 ;
        RECT 6.6650 363.9400 6.7350 364.2300 ;
    END
  END ahbso_in_108
  PIN ahbso_in_107
    DIRECTION INPUT ;
    USE SIGNAL ;
    PORT
      LAYER Metal6 ;
        RECT 25.4650 363.9400 25.5350 364.2300 ;
    END
  END ahbso_in_107
  PIN ahbso_in_106
    DIRECTION INPUT ;
    USE SIGNAL ;
    PORT
      LAYER Metal4 ;
        RECT 7.0650 363.9400 7.1350 364.2300 ;
    END
  END ahbso_in_106
  PIN ahbso_in_105
    DIRECTION INPUT ;
    USE SIGNAL ;
    PORT
      LAYER Metal6 ;
        RECT 25.8650 363.9400 25.9350 364.2300 ;
    END
  END ahbso_in_105
  PIN ahbso_in_104
    DIRECTION INPUT ;
    USE SIGNAL ;
    PORT
      LAYER Metal4 ;
        RECT 7.4650 363.9400 7.5350 364.2300 ;
    END
  END ahbso_in_104
  PIN ahbso_in_103
    DIRECTION INPUT ;
    USE SIGNAL ;
    PORT
      LAYER Metal6 ;
        RECT 26.2650 363.9400 26.3350 364.2300 ;
    END
  END ahbso_in_103
  PIN ahbso_in_102
    DIRECTION INPUT ;
    USE SIGNAL ;
    PORT
      LAYER Metal4 ;
        RECT 7.8650 363.9400 7.9350 364.2300 ;
    END
  END ahbso_in_102
  PIN ahbso_in_101
    DIRECTION INPUT ;
    USE SIGNAL ;
    PORT
      LAYER Metal3 ;
        RECT 0.0000 300.2600 0.2900 300.3300 ;
    END
  END ahbso_in_101
  PIN ahbso_in_99
    DIRECTION INPUT ;
    USE SIGNAL ;
    PORT
      LAYER Metal2 ;
        RECT 160.2650 363.9400 160.3350 364.2300 ;
    END
  END ahbso_in_99
  PIN ahbso_in_98
    DIRECTION INPUT ;
    USE SIGNAL ;
    PORT
      LAYER Metal5 ;
        RECT 0.0000 319.4500 0.2900 319.5200 ;
    END
  END ahbso_in_98
  PIN ahbso_in_97
    DIRECTION INPUT ;
    USE SIGNAL ;
    PORT
      LAYER Metal3 ;
        RECT 0.0000 319.6400 0.2900 319.7100 ;
    END
  END ahbso_in_97
  PIN ahbso_in_96
    DIRECTION INPUT ;
    USE SIGNAL ;
    PORT
      LAYER Metal9 ;
        RECT 0.0000 320.4000 0.2900 320.4700 ;
    END
  END ahbso_in_96
  PIN ahbso_in_95
    DIRECTION INPUT ;
    USE SIGNAL ;
    PORT
      LAYER Metal9 ;
        RECT 0.0000 321.1600 0.2900 321.2300 ;
    END
  END ahbso_in_95
  PIN ahbso_in_94
    DIRECTION INPUT ;
    USE SIGNAL ;
    PORT
      LAYER Metal5 ;
        RECT 0.0000 321.5400 0.2900 321.6100 ;
    END
  END ahbso_in_94
  PIN ahbso_in_93
    DIRECTION INPUT ;
    USE SIGNAL ;
    PORT
      LAYER Metal2 ;
        RECT 71.2650 363.9400 71.3350 364.2300 ;
    END
  END ahbso_in_93
  PIN ahbso_in_92
    DIRECTION INPUT ;
    USE SIGNAL ;
    PORT
      LAYER Metal2 ;
        RECT 75.4650 363.9400 75.5350 364.2300 ;
    END
  END ahbso_in_92
  PIN ahbso_in_91
    DIRECTION INPUT ;
    USE SIGNAL ;
    PORT
      LAYER Metal2 ;
        RECT 79.2650 363.9400 79.3350 364.2300 ;
    END
  END ahbso_in_91
  PIN ahbso_in_90
    DIRECTION INPUT ;
    USE SIGNAL ;
    PORT
      LAYER Metal5 ;
        RECT 0.0000 362.9600 0.2900 363.0300 ;
    END
  END ahbso_in_90
  PIN ahbso_in_89
    DIRECTION INPUT ;
    USE SIGNAL ;
    PORT
      LAYER Metal3 ;
        RECT 0.0000 362.7700 0.2900 362.8400 ;
    END
  END ahbso_in_89
  PIN ahbso_in_88
    DIRECTION INPUT ;
    USE SIGNAL ;
    PORT
      LAYER Metal2 ;
        RECT 87.4650 363.9400 87.5350 364.2300 ;
    END
  END ahbso_in_88
  PIN ahbso_in_87
    DIRECTION INPUT ;
    USE SIGNAL ;
    PORT
      LAYER Metal5 ;
        RECT 0.0000 362.5800 0.2900 362.6500 ;
    END
  END ahbso_in_87
  PIN ahbso_in_86
    DIRECTION INPUT ;
    USE SIGNAL ;
    PORT
      LAYER Metal9 ;
        RECT 0.0000 321.9200 0.2900 321.9900 ;
    END
  END ahbso_in_86
  PIN ahbso_in_85
    DIRECTION INPUT ;
    USE SIGNAL ;
    PORT
      LAYER Metal5 ;
        RECT 0.0000 321.9200 0.2900 321.9900 ;
    END
  END ahbso_in_85
  PIN ahbso_in_84
    DIRECTION INPUT ;
    USE SIGNAL ;
    PORT
      LAYER Metal5 ;
        RECT 0.0000 314.3200 0.2900 314.3900 ;
    END
  END ahbso_in_84
  PIN ahbso_in_83
    DIRECTION INPUT ;
    USE SIGNAL ;
    PORT
      LAYER Metal3 ;
        RECT 0.0000 319.2600 0.2900 319.3300 ;
    END
  END ahbso_in_83
  PIN ahbso_in_82
    DIRECTION INPUT ;
    USE SIGNAL ;
    PORT
      LAYER Metal5 ;
        RECT 0.0000 321.1600 0.2900 321.2300 ;
    END
  END ahbso_in_82
  PIN ahbso_in_81
    DIRECTION INPUT ;
    USE SIGNAL ;
    PORT
      LAYER Metal5 ;
        RECT 0.0000 322.3000 0.2900 322.3700 ;
    END
  END ahbso_in_81
  PIN ahbso_in_80
    DIRECTION INPUT ;
    USE SIGNAL ;
    PORT
      LAYER Metal9 ;
        RECT 0.0000 322.6800 0.2900 322.7500 ;
    END
  END ahbso_in_80
  PIN ahbso_in_79
    DIRECTION INPUT ;
    USE SIGNAL ;
    PORT
      LAYER Metal5 ;
        RECT 0.0000 322.6800 0.2900 322.7500 ;
    END
  END ahbso_in_79
  PIN ahbso_in_78
    DIRECTION INPUT ;
    USE SIGNAL ;
    PORT
      LAYER Metal3 ;
        RECT 0.0000 322.8700 0.2900 322.9400 ;
    END
  END ahbso_in_78
  PIN ahbso_in_77
    DIRECTION INPUT ;
    USE SIGNAL ;
    PORT
      LAYER Metal5 ;
        RECT 0.0000 323.0600 0.2900 323.1300 ;
    END
  END ahbso_in_77
  PIN ahbso_in_76
    DIRECTION INPUT ;
    USE SIGNAL ;
    PORT
      LAYER Metal5 ;
        RECT 0.0000 323.8200 0.2900 323.8900 ;
    END
  END ahbso_in_76
  PIN ahbso_in_75
    DIRECTION INPUT ;
    USE SIGNAL ;
    PORT
      LAYER Metal5 ;
        RECT 0.0000 324.2000 0.2900 324.2700 ;
    END
  END ahbso_in_75
  PIN ahbso_in_74
    DIRECTION INPUT ;
    USE SIGNAL ;
    PORT
      LAYER Metal9 ;
        RECT 0.0000 324.5800 0.2900 324.6500 ;
    END
  END ahbso_in_74
  PIN ahbso_in_73
    DIRECTION INPUT ;
    USE SIGNAL ;
    PORT
      LAYER Metal5 ;
        RECT 0.0000 324.5800 0.2900 324.6500 ;
    END
  END ahbso_in_73
  PIN ahbso_in_72
    DIRECTION INPUT ;
    USE SIGNAL ;
    PORT
      LAYER Metal2 ;
        RECT 80.4650 363.9400 80.5350 364.2300 ;
    END
  END ahbso_in_72
  PIN ahbso_in_71
    DIRECTION INPUT ;
    USE SIGNAL ;
    PORT
      LAYER Metal5 ;
        RECT 0.0000 324.9600 0.2900 325.0300 ;
    END
  END ahbso_in_71
  PIN ahbso_in_70
    DIRECTION INPUT ;
    USE SIGNAL ;
    PORT
      LAYER Metal5 ;
        RECT 0.0000 329.3300 0.2900 329.4000 ;
    END
  END ahbso_in_70
  PIN ahbso_in_69
    DIRECTION INPUT ;
    USE SIGNAL ;
    PORT
      LAYER Metal9 ;
        RECT 0.0000 329.5200 0.2900 329.5900 ;
    END
  END ahbso_in_69
  PIN ahbso_in_68
    DIRECTION INPUT ;
    USE SIGNAL ;
    PORT
      LAYER Metal9 ;
        RECT 0.0000 325.3400 0.2900 325.4100 ;
    END
  END ahbso_in_68
  PIN ahbso_in_67
    DIRECTION INPUT ;
    USE SIGNAL ;
    PORT
      LAYER Metal3 ;
        RECT 0.0000 299.5000 0.2900 299.5700 ;
    END
  END ahbso_in_67
  PIN ahbso_in_66
    DIRECTION INPUT ;
    USE SIGNAL ;
    PORT
      LAYER Metal6 ;
        RECT 26.6650 363.9400 26.7350 364.2300 ;
    END
  END ahbso_in_66
  PIN ahbso_in_65
    DIRECTION INPUT ;
    USE SIGNAL ;
    PORT
      LAYER Metal4 ;
        RECT 8.2650 363.9400 8.3350 364.2300 ;
    END
  END ahbso_in_65
  PIN ahbso_in_64
    DIRECTION INPUT ;
    USE SIGNAL ;
    PORT
      LAYER Metal6 ;
        RECT 27.0650 363.9400 27.1350 364.2300 ;
    END
  END ahbso_in_64
  PIN ahbso_in_63
    DIRECTION INPUT ;
    USE SIGNAL ;
    PORT
      LAYER Metal4 ;
        RECT 8.6650 363.9400 8.7350 364.2300 ;
    END
  END ahbso_in_63
  PIN ahbso_in_62
    DIRECTION INPUT ;
    USE SIGNAL ;
    PORT
      LAYER Metal6 ;
        RECT 27.4650 363.9400 27.5350 364.2300 ;
    END
  END ahbso_in_62
  PIN ahbso_in_61
    DIRECTION INPUT ;
    USE SIGNAL ;
    PORT
      LAYER Metal4 ;
        RECT 9.0650 363.9400 9.1350 364.2300 ;
    END
  END ahbso_in_61
  PIN ahbso_in_60
    DIRECTION INPUT ;
    USE SIGNAL ;
    PORT
      LAYER Metal6 ;
        RECT 27.8650 363.9400 27.9350 364.2300 ;
    END
  END ahbso_in_60
  PIN ahbso_in_59
    DIRECTION INPUT ;
    USE SIGNAL ;
    PORT
      LAYER Metal4 ;
        RECT 9.4650 363.9400 9.5350 364.2300 ;
    END
  END ahbso_in_59
  PIN ahbso_in_58
    DIRECTION INPUT ;
    USE SIGNAL ;
    PORT
      LAYER Metal6 ;
        RECT 28.2650 363.9400 28.3350 364.2300 ;
    END
  END ahbso_in_58
  PIN ahbso_in_57
    DIRECTION INPUT ;
    USE SIGNAL ;
    PORT
      LAYER Metal4 ;
        RECT 9.8650 363.9400 9.9350 364.2300 ;
    END
  END ahbso_in_57
  PIN ahbso_in_56
    DIRECTION INPUT ;
    USE SIGNAL ;
    PORT
      LAYER Metal6 ;
        RECT 28.6650 363.9400 28.7350 364.2300 ;
    END
  END ahbso_in_56
  PIN ahbso_in_55
    DIRECTION INPUT ;
    USE SIGNAL ;
    PORT
      LAYER Metal4 ;
        RECT 11.2650 363.9400 11.3350 364.2300 ;
    END
  END ahbso_in_55
  PIN ahbso_in_54
    DIRECTION INPUT ;
    USE SIGNAL ;
    PORT
      LAYER Metal6 ;
        RECT 29.0650 363.9400 29.1350 364.2300 ;
    END
  END ahbso_in_54
  PIN ahbso_in_53
    DIRECTION INPUT ;
    USE SIGNAL ;
    PORT
      LAYER Metal4 ;
        RECT 11.6650 363.9400 11.7350 364.2300 ;
    END
  END ahbso_in_53
  PIN ahbso_in_52
    DIRECTION INPUT ;
    USE SIGNAL ;
    PORT
      LAYER Metal6 ;
        RECT 29.4650 363.9400 29.5350 364.2300 ;
    END
  END ahbso_in_52
  PIN ahbso_in_51
    DIRECTION INPUT ;
    USE SIGNAL ;
    PORT
      LAYER Metal4 ;
        RECT 12.0650 363.9400 12.1350 364.2300 ;
    END
  END ahbso_in_51
  PIN ahbso_in_50
    DIRECTION INPUT ;
    USE SIGNAL ;
    PORT
      LAYER Metal4 ;
        RECT 243.4650 363.9400 243.5350 364.2300 ;
    END
  END ahbso_in_50
  PIN ahbso_in_48
    DIRECTION INPUT ;
    USE SIGNAL ;
    PORT
      LAYER Metal9 ;
        RECT 0.0000 288.8600 0.2900 288.9300 ;
    END
  END ahbso_in_48
  PIN ahbso_in_47
    DIRECTION INPUT ;
    USE SIGNAL ;
    PORT
      LAYER Metal5 ;
        RECT 0.0000 288.8600 0.2900 288.9300 ;
    END
  END ahbso_in_47
  PIN ahbso_in_46
    DIRECTION INPUT ;
    USE SIGNAL ;
    PORT
      LAYER Metal3 ;
        RECT 0.0000 288.8600 0.2900 288.9300 ;
    END
  END ahbso_in_46
  PIN ahbso_in_45
    DIRECTION INPUT ;
    USE SIGNAL ;
    PORT
      LAYER Metal5 ;
        RECT 0.0000 289.2400 0.2900 289.3100 ;
    END
  END ahbso_in_45
  PIN ahbso_in_44
    DIRECTION INPUT ;
    USE SIGNAL ;
    PORT
      LAYER Metal2 ;
        RECT 183.2650 363.9400 183.3350 364.2300 ;
    END
  END ahbso_in_44
  PIN ahbso_in_43
    DIRECTION INPUT ;
    USE SIGNAL ;
    PORT
      LAYER Metal2 ;
        RECT 158.2650 363.9400 158.3350 364.2300 ;
    END
  END ahbso_in_43
  PIN ahbso_in_42
    DIRECTION INPUT ;
    USE SIGNAL ;
    PORT
      LAYER Metal3 ;
        RECT 0.0000 289.2400 0.2900 289.3100 ;
    END
  END ahbso_in_42
  PIN ahbso_in_41
    DIRECTION INPUT ;
    USE SIGNAL ;
    PORT
      LAYER Metal2 ;
        RECT 151.4650 363.9400 151.5350 364.2300 ;
    END
  END ahbso_in_41
  PIN ahbso_in_40
    DIRECTION INPUT ;
    USE SIGNAL ;
    PORT
      LAYER Metal9 ;
        RECT 0.0000 289.6200 0.2900 289.6900 ;
    END
  END ahbso_in_40
  PIN ahbso_in_39
    DIRECTION INPUT ;
    USE SIGNAL ;
    PORT
      LAYER Metal5 ;
        RECT 0.0000 289.6200 0.2900 289.6900 ;
    END
  END ahbso_in_39
  PIN ahbso_in_38
    DIRECTION INPUT ;
    USE SIGNAL ;
    PORT
      LAYER Metal3 ;
        RECT 0.0000 289.6200 0.2900 289.6900 ;
    END
  END ahbso_in_38
  PIN ahbso_in_37
    DIRECTION INPUT ;
    USE SIGNAL ;
    PORT
      LAYER Metal5 ;
        RECT 0.0000 290.0000 0.2900 290.0700 ;
    END
  END ahbso_in_37
  PIN ahbso_in_36
    DIRECTION INPUT ;
    USE SIGNAL ;
    PORT
      LAYER Metal3 ;
        RECT 0.0000 290.0000 0.2900 290.0700 ;
    END
  END ahbso_in_36
  PIN ahbso_in_35
    DIRECTION INPUT ;
    USE SIGNAL ;
    PORT
      LAYER Metal4 ;
        RECT 141.2650 363.9400 141.3350 364.2300 ;
    END
  END ahbso_in_35
  PIN ahbso_in_34
    DIRECTION INPUT ;
    USE SIGNAL ;
    PORT
      LAYER Metal9 ;
        RECT 0.0000 290.3800 0.2900 290.4500 ;
    END
  END ahbso_in_34
  PIN ahbso_in_33
    DIRECTION INPUT ;
    USE SIGNAL ;
    PORT
      LAYER Metal5 ;
        RECT 0.0000 290.3800 0.2900 290.4500 ;
    END
  END ahbso_in_33
  PIN ahbso_in_32
    DIRECTION INPUT ;
    USE SIGNAL ;
    PORT
      LAYER Metal5 ;
        RECT 0.0000 290.7600 0.2900 290.8300 ;
    END
  END ahbso_in_32
  PIN ahbso_in_31
    DIRECTION INPUT ;
    USE SIGNAL ;
    PORT
      LAYER Metal3 ;
        RECT 0.0000 290.7600 0.2900 290.8300 ;
    END
  END ahbso_in_31
  PIN ahbso_in_30
    DIRECTION INPUT ;
    USE SIGNAL ;
    PORT
      LAYER Metal2 ;
        RECT 135.2650 363.9400 135.3350 364.2300 ;
    END
  END ahbso_in_30
  PIN ahbso_in_29
    DIRECTION INPUT ;
    USE SIGNAL ;
    PORT
      LAYER Metal9 ;
        RECT 0.0000 291.1400 0.2900 291.2100 ;
    END
  END ahbso_in_29
  PIN ahbso_in_28
    DIRECTION INPUT ;
    USE SIGNAL ;
    PORT
      LAYER Metal5 ;
        RECT 0.0000 291.1400 0.2900 291.2100 ;
    END
  END ahbso_in_28
  PIN ahbso_in_27
    DIRECTION INPUT ;
    USE SIGNAL ;
    PORT
      LAYER Metal3 ;
        RECT 0.0000 291.1400 0.2900 291.2100 ;
    END
  END ahbso_in_27
  PIN ahbso_in_26
    DIRECTION INPUT ;
    USE SIGNAL ;
    PORT
      LAYER Metal5 ;
        RECT 0.0000 291.5200 0.2900 291.5900 ;
    END
  END ahbso_in_26
  PIN ahbso_in_25
    DIRECTION INPUT ;
    USE SIGNAL ;
    PORT
      LAYER Metal3 ;
        RECT 0.0000 291.5200 0.2900 291.5900 ;
    END
  END ahbso_in_25
  PIN ahbso_in_24
    DIRECTION INPUT ;
    USE SIGNAL ;
    PORT
      LAYER Metal9 ;
        RECT 0.0000 291.9000 0.2900 291.9700 ;
    END
  END ahbso_in_24
  PIN ahbso_in_23
    DIRECTION INPUT ;
    USE SIGNAL ;
    PORT
      LAYER Metal5 ;
        RECT 0.0000 291.9000 0.2900 291.9700 ;
    END
  END ahbso_in_23
  PIN ahbso_in_22
    DIRECTION INPUT ;
    USE SIGNAL ;
    PORT
      LAYER Metal3 ;
        RECT 0.0000 291.9000 0.2900 291.9700 ;
    END
  END ahbso_in_22
  PIN ahbso_in_21
    DIRECTION INPUT ;
    USE SIGNAL ;
    PORT
      LAYER Metal5 ;
        RECT 0.0000 292.2800 0.2900 292.3500 ;
    END
  END ahbso_in_21
  PIN ahbso_in_20
    DIRECTION INPUT ;
    USE SIGNAL ;
    PORT
      LAYER Metal3 ;
        RECT 0.0000 292.2800 0.2900 292.3500 ;
    END
  END ahbso_in_20
  PIN ahbso_in_19
    DIRECTION INPUT ;
    USE SIGNAL ;
    PORT
      LAYER Metal9 ;
        RECT 0.0000 292.6600 0.2900 292.7300 ;
    END
  END ahbso_in_19
  PIN ahbso_in_18
    DIRECTION INPUT ;
    USE SIGNAL ;
    PORT
      LAYER Metal5 ;
        RECT 0.0000 292.6600 0.2900 292.7300 ;
    END
  END ahbso_in_18
  PIN ahbso_in_17
    DIRECTION INPUT ;
    USE SIGNAL ;
    PORT
      LAYER Metal6 ;
        RECT 178.2650 363.9400 178.3350 364.2300 ;
    END
  END ahbso_in_17
  PIN ahbso_in_16
    DIRECTION INPUT ;
    USE SIGNAL ;
    PORT
      LAYER Metal3 ;
        RECT 0.0000 292.6600 0.2900 292.7300 ;
    END
  END ahbso_in_16
  PIN ahbso_in_15
    DIRECTION INPUT ;
    USE SIGNAL ;
    PORT
      LAYER Metal6 ;
        RECT 29.8650 363.9400 29.9350 364.2300 ;
    END
  END ahbso_in_15
  PIN ahbso_in_14
    DIRECTION INPUT ;
    USE SIGNAL ;
    PORT
      LAYER Metal4 ;
        RECT 12.4650 363.9400 12.5350 364.2300 ;
    END
  END ahbso_in_14
  PIN ahbso_in_13
    DIRECTION INPUT ;
    USE SIGNAL ;
    PORT
      LAYER Metal6 ;
        RECT 30.2650 363.9400 30.3350 364.2300 ;
    END
  END ahbso_in_13
  PIN ahbso_in_12
    DIRECTION INPUT ;
    USE SIGNAL ;
    PORT
      LAYER Metal4 ;
        RECT 12.8650 363.9400 12.9350 364.2300 ;
    END
  END ahbso_in_12
  PIN ahbso_in_11
    DIRECTION INPUT ;
    USE SIGNAL ;
    PORT
      LAYER Metal6 ;
        RECT 30.6650 363.9400 30.7350 364.2300 ;
    END
  END ahbso_in_11
  PIN ahbso_in_10
    DIRECTION INPUT ;
    USE SIGNAL ;
    PORT
      LAYER Metal4 ;
        RECT 13.2650 363.9400 13.3350 364.2300 ;
    END
  END ahbso_in_10
  PIN ahbso_in_9
    DIRECTION INPUT ;
    USE SIGNAL ;
    PORT
      LAYER Metal6 ;
        RECT 31.0650 363.9400 31.1350 364.2300 ;
    END
  END ahbso_in_9
  PIN ahbso_in_8
    DIRECTION INPUT ;
    USE SIGNAL ;
    PORT
      LAYER Metal4 ;
        RECT 13.6650 363.9400 13.7350 364.2300 ;
    END
  END ahbso_in_8
  PIN ahbso_in_7
    DIRECTION INPUT ;
    USE SIGNAL ;
    PORT
      LAYER Metal6 ;
        RECT 31.4650 363.9400 31.5350 364.2300 ;
    END
  END ahbso_in_7
  PIN ahbso_in_6
    DIRECTION INPUT ;
    USE SIGNAL ;
    PORT
      LAYER Metal4 ;
        RECT 14.0650 363.9400 14.1350 364.2300 ;
    END
  END ahbso_in_6
  PIN ahbso_in_5
    DIRECTION INPUT ;
    USE SIGNAL ;
    PORT
      LAYER Metal6 ;
        RECT 31.8650 363.9400 31.9350 364.2300 ;
    END
  END ahbso_in_5
  PIN ahbso_in_4
    DIRECTION INPUT ;
    USE SIGNAL ;
    PORT
      LAYER Metal4 ;
        RECT 14.4650 363.9400 14.5350 364.2300 ;
    END
  END ahbso_in_4
  PIN ahbso_in_3
    DIRECTION INPUT ;
    USE SIGNAL ;
    PORT
      LAYER Metal6 ;
        RECT 32.2650 363.9400 32.3350 364.2300 ;
    END
  END ahbso_in_3
  PIN ahbso_in_2
    DIRECTION INPUT ;
    USE SIGNAL ;
    PORT
      LAYER Metal4 ;
        RECT 14.8650 363.9400 14.9350 364.2300 ;
    END
  END ahbso_in_2
  PIN ahbso_in_1
    DIRECTION INPUT ;
    USE SIGNAL ;
    PORT
      LAYER Metal6 ;
        RECT 32.6650 363.9400 32.7350 364.2300 ;
    END
  END ahbso_in_1
  PIN ahbso_in_0
    DIRECTION INPUT ;
    USE SIGNAL ;
    PORT
      LAYER Metal4 ;
        RECT 15.2650 363.9400 15.3350 364.2300 ;
    END
  END ahbso_in_0
  PIN ext_irq
    DIRECTION INPUT ;
    USE SIGNAL ;
    PORT
      LAYER Metal2 ;
        RECT 371.2650 363.9400 371.3350 364.2300 ;
    END
  END ext_irq
  PIN scan_enable_2core
    DIRECTION INPUT ;
    USE SIGNAL ;
    PORT
      LAYER Metal5 ;
        RECT 0.0000 329.7100 0.2900 329.7800 ;
    END
  END scan_enable_2core
  PIN BG_scan_in
    DIRECTION INPUT ;
    USE SIGNAL ;
    PORT
      LAYER Metal2 ;
        RECT 122.6650 363.9400 122.7350 364.2300 ;
    END
  END BG_scan_in
  PIN BG_scan_out
    DIRECTION OUTPUT ;
    USE SIGNAL ;
    PORT
      LAYER Metal2 ;
        RECT 68.2650 363.9400 68.3350 364.2300 ;
    END
  END BG_scan_out
  PIN BG_scan_in_2
    DIRECTION INPUT ;
    USE SIGNAL ;
    PORT
      LAYER Metal4 ;
        RECT 268.2650 363.9400 268.3350 364.2300 ;
    END
  END BG_scan_in_2
  PIN BG_scan_out_2
    DIRECTION OUTPUT ;
    USE SIGNAL ;
    PORT
      LAYER Metal3 ;
        RECT 0.0000 296.8400 0.2900 296.9100 ;
    END
  END BG_scan_out_2
  PIN BG_scan_in_3
    DIRECTION INPUT ;
    USE SIGNAL ;
    PORT
      LAYER Metal9 ;
        RECT 0.0000 297.2200 0.2900 297.2900 ;
    END
  END BG_scan_in_3
  PIN BG_scan_in_4
    DIRECTION INPUT ;
    USE SIGNAL ;
    PORT
      LAYER Metal5 ;
        RECT 0.0000 297.2200 0.2900 297.2900 ;
    END
  END BG_scan_in_4
  PIN BG_scan_in_5
    DIRECTION INPUT ;
    USE SIGNAL ;
    PORT
      LAYER Metal3 ;
        RECT 0.0000 290.3800 0.2900 290.4500 ;
    END
  END BG_scan_in_5
  PIN BG_scan_in_6
    DIRECTION INPUT ;
    USE SIGNAL ;
    PORT
      LAYER Metal2 ;
        RECT 42.2650 363.9400 42.3350 364.2300 ;
    END
  END BG_scan_in_6
  PIN BG_scan_in_7
    DIRECTION INPUT ;
    USE SIGNAL ;
    PORT
      LAYER Metal9 ;
        RECT 3360.9100 117.8600 3361.2000 117.9300 ;
    END
  END BG_scan_in_7
  PIN BG_scan_out_3
    DIRECTION OUTPUT ;
    USE SIGNAL ;
    PORT
      LAYER Metal2 ;
        RECT 2181.2650 363.9400 2181.3350 364.2300 ;
    END
  END BG_scan_out_3
  PIN BG_scan_in_8
    DIRECTION INPUT ;
    USE SIGNAL ;
    PORT
      LAYER Metal2 ;
        RECT 1822.0650 363.9400 1822.1350 364.2300 ;
    END
  END BG_scan_in_8
  PIN BG_scan_out_4
    DIRECTION OUTPUT ;
    USE SIGNAL ;
    PORT
      LAYER Metal3 ;
        RECT 3360.9100 333.5100 3361.2000 333.5800 ;
    END
  END BG_scan_out_4
  PIN BG_scan_in_9
    DIRECTION INPUT ;
    USE SIGNAL ;
    PORT
      LAYER Metal2 ;
        RECT 2117.8650 363.9400 2117.9350 364.2300 ;
    END
  END BG_scan_in_9
  PIN BG_scan_out_5
    DIRECTION OUTPUT ;
    USE SIGNAL ;
    PORT
      LAYER Metal2 ;
        RECT 2175.0650 363.9400 2175.1350 364.2300 ;
    END
  END BG_scan_out_5
  PIN BG_scan_in_10
    DIRECTION INPUT ;
    USE SIGNAL ;
    PORT
      LAYER Metal3 ;
        RECT 3360.9100 331.8000 3361.2000 331.8700 ;
    END
  END BG_scan_in_10
  PIN BG_scan_out_6
    DIRECTION OUTPUT ;
    USE SIGNAL ;
    PORT
      LAYER Metal9 ;
        RECT 3360.9100 188.1600 3361.2000 188.2300 ;
    END
  END BG_scan_out_6
  PIN BG_scan_in_11
    DIRECTION INPUT ;
    USE SIGNAL ;
    PORT
      LAYER Metal9 ;
        RECT 3360.9100 290.3800 3361.2000 290.4500 ;
    END
  END BG_scan_in_11
  PIN BG_scan_out_7
    DIRECTION OUTPUT ;
    USE SIGNAL ;
    PORT
      LAYER Metal2 ;
        RECT 2001.0650 363.9400 2001.1350 364.2300 ;
    END
  END BG_scan_out_7
  PIN BG_scan_in_12
    DIRECTION INPUT ;
    USE SIGNAL ;
    PORT
      LAYER Metal2 ;
        RECT 1897.0650 363.9400 1897.1350 364.2300 ;
    END
  END BG_scan_in_12
  PIN BG_scan_out_8
    DIRECTION OUTPUT ;
    USE SIGNAL ;
    PORT
      LAYER Metal2 ;
        RECT 1617.0650 363.9400 1617.1350 364.2300 ;
    END
  END BG_scan_out_8
  PIN BG_scan_in_13
    DIRECTION INPUT ;
    USE SIGNAL ;
    PORT
      LAYER Metal2 ;
        RECT 2008.8650 363.9400 2008.9350 364.2300 ;
    END
  END BG_scan_in_13
  PIN BG_scan_out_9
    DIRECTION OUTPUT ;
    USE SIGNAL ;
    PORT
      LAYER Metal2 ;
        RECT 2078.0650 363.9400 2078.1350 364.2300 ;
    END
  END BG_scan_out_9
  PIN BG_scan_in_14
    DIRECTION INPUT ;
    USE SIGNAL ;
    PORT
      LAYER Metal2 ;
        RECT 1622.0650 363.9400 1622.1350 364.2300 ;
    END
  END BG_scan_in_14
  PIN BG_scan_out_10
    DIRECTION OUTPUT ;
    USE SIGNAL ;
    PORT
      LAYER Metal2 ;
        RECT 1726.0650 363.9400 1726.1350 364.2300 ;
    END
  END BG_scan_out_10
  PIN BG_scan_in_15
    DIRECTION INPUT ;
    USE SIGNAL ;
    PORT
      LAYER Metal2 ;
        RECT 1731.0650 363.9400 1731.1350 364.2300 ;
    END
  END BG_scan_in_15
  PIN BG_scan_out_11
    DIRECTION OUTPUT ;
    USE SIGNAL ;
    PORT
      LAYER Metal4 ;
        RECT 2118.0650 363.9400 2118.1350 364.2300 ;
    END
  END BG_scan_out_11
  PIN BG_scan_in_16
    DIRECTION INPUT ;
    USE SIGNAL ;
    PORT
      LAYER Metal3 ;
        RECT 3360.9100 345.1000 3361.2000 345.1700 ;
    END
  END BG_scan_in_16
  PIN BG_scan_out_12
    DIRECTION OUTPUT ;
    USE SIGNAL ;
    PORT
      LAYER Metal2 ;
        RECT 2232.0650 363.9400 2232.1350 364.2300 ;
    END
  END BG_scan_out_12
  PIN BG_scan_in_17
    DIRECTION INPUT ;
    USE SIGNAL ;
    PORT
      LAYER Metal2 ;
        RECT 2672.0650 363.9400 2672.1350 364.2300 ;
    END
  END BG_scan_in_17
  PIN BG_scan_out_13
    DIRECTION OUTPUT ;
    USE SIGNAL ;
    PORT
      LAYER Metal2 ;
        RECT 2429.2650 363.9400 2429.3350 364.2300 ;
    END
  END BG_scan_out_13
  PIN clk_2core__L13_N51
    DIRECTION INPUT ;
    USE SIGNAL ;
    PORT
      LAYER Metal2 ;
        RECT 141.4650 363.9400 141.5350 364.2300 ;
    END
  END clk_2core__L13_N51
  PIN clk_2core__L13_N52
    DIRECTION INPUT ;
    USE SIGNAL ;
    PORT
      LAYER Metal2 ;
        RECT 198.4650 363.9400 198.5350 364.2300 ;
    END
  END clk_2core__L13_N52
  PIN clk_2core__L13_N53
    DIRECTION INPUT ;
    USE SIGNAL ;
    PORT
      LAYER Metal2 ;
        RECT 115.0650 363.9400 115.1350 364.2300 ;
    END
  END clk_2core__L13_N53
  PIN clk_2core__L13_N54
    DIRECTION INPUT ;
    USE SIGNAL ;
    PORT
      LAYER Metal2 ;
        RECT 33.0650 363.9400 33.1350 364.2300 ;
    END
  END clk_2core__L13_N54
  PIN clk_2core__L13_N55
    DIRECTION INPUT ;
    USE SIGNAL ;
    PORT
      LAYER Metal2 ;
        RECT 107.2650 363.9400 107.3350 364.2300 ;
    END
  END clk_2core__L13_N55
  PIN clk_2core__L13_N56
    DIRECTION INPUT ;
    USE SIGNAL ;
    PORT
      LAYER Metal2 ;
        RECT 19.8650 363.9400 19.9350 364.2300 ;
    END
  END clk_2core__L13_N56
  PIN clk_2core__L13_N57
    DIRECTION INPUT ;
    USE SIGNAL ;
    PORT
      LAYER Metal2 ;
        RECT 124.6650 363.9400 124.7350 364.2300 ;
    END
  END clk_2core__L13_N57
  PIN clk_2core__L13_N58
    DIRECTION INPUT ;
    USE SIGNAL ;
    PORT
      LAYER Metal3 ;
        RECT 0.0000 258.6500 0.2900 258.7200 ;
    END
  END clk_2core__L13_N58
  PIN clk_2core__L13_N59
    DIRECTION INPUT ;
    USE SIGNAL ;
    PORT
      LAYER Metal3 ;
        RECT 0.0000 251.8100 0.2900 251.8800 ;
    END
  END clk_2core__L13_N59
  PIN clk_2core__L13_N60
    DIRECTION INPUT ;
    USE SIGNAL ;
    PORT
      LAYER Metal2 ;
        RECT 204.0650 363.9400 204.1350 364.2300 ;
    END
  END clk_2core__L13_N60
  PIN clk_2core__L13_N61
    DIRECTION INPUT ;
    USE SIGNAL ;
    PORT
      LAYER Metal2 ;
        RECT 97.0650 363.9400 97.1350 364.2300 ;
    END
  END clk_2core__L13_N61
  PIN clk_2core__L13_N62
    DIRECTION INPUT ;
    USE SIGNAL ;
    PORT
      LAYER Metal2 ;
        RECT 170.4650 363.9400 170.5350 364.2300 ;
    END
  END clk_2core__L13_N62
  PIN clk_2core__L13_N63
    DIRECTION INPUT ;
    USE SIGNAL ;
    PORT
      LAYER Metal2 ;
        RECT 249.8650 363.9400 249.9350 364.2300 ;
    END
  END clk_2core__L13_N63
  PIN clk_2core__L13_N64
    DIRECTION INPUT ;
    USE SIGNAL ;
    PORT
      LAYER Metal2 ;
        RECT 299.6650 363.9400 299.7350 364.2300 ;
    END
  END clk_2core__L13_N64
  PIN clk_2core__L13_N65
    DIRECTION INPUT ;
    USE SIGNAL ;
    PORT
      LAYER Metal2 ;
        RECT 292.0650 363.9400 292.1350 364.2300 ;
    END
  END clk_2core__L13_N65
  PIN clk_2core__L13_N66
    DIRECTION INPUT ;
    USE SIGNAL ;
    PORT
      LAYER Metal2 ;
        RECT 268.2650 363.9400 268.3350 364.2300 ;
    END
  END clk_2core__L13_N66
  PIN clk_2core__L13_N67
    DIRECTION INPUT ;
    USE SIGNAL ;
    PORT
      LAYER Metal2 ;
        RECT 310.8650 363.9400 310.9350 364.2300 ;
    END
  END clk_2core__L13_N67
  PIN clk_2core__L13_N68
    DIRECTION INPUT ;
    USE SIGNAL ;
    PORT
      LAYER Metal2 ;
        RECT 281.6650 363.9400 281.7350 364.2300 ;
    END
  END clk_2core__L13_N68
  PIN clk_2core__L13_N69
    DIRECTION INPUT ;
    USE SIGNAL ;
    PORT
      LAYER Metal2 ;
        RECT 343.8650 363.9400 343.9350 364.2300 ;
    END
  END clk_2core__L13_N69
  PIN clk_2core__L13_N70
    DIRECTION INPUT ;
    USE SIGNAL ;
    PORT
      LAYER Metal2 ;
        RECT 337.6650 363.9400 337.7350 364.2300 ;
    END
  END clk_2core__L13_N70
  PIN clk_2core__L13_N71
    DIRECTION INPUT ;
    USE SIGNAL ;
    PORT
      LAYER Metal2 ;
        RECT 318.2650 363.9400 318.3350 364.2300 ;
    END
  END clk_2core__L13_N71
  PIN clk_2core__L13_N72
    DIRECTION INPUT ;
    USE SIGNAL ;
    PORT
      LAYER Metal2 ;
        RECT 343.0650 363.9400 343.1350 364.2300 ;
    END
  END clk_2core__L13_N72
  PIN clk_2core__L13_N73
    DIRECTION INPUT ;
    USE SIGNAL ;
    PORT
      LAYER Metal2 ;
        RECT 233.8650 363.9400 233.9350 364.2300 ;
    END
  END clk_2core__L13_N73
  PIN clk_2core__L15_N184
    DIRECTION INPUT ;
    USE SIGNAL ;
    PORT
      LAYER Metal2 ;
        RECT 264.2650 363.9400 264.3350 364.2300 ;
    END
  END clk_2core__L15_N184
  PIN clk_2core__L15_N185
    DIRECTION INPUT ;
    USE SIGNAL ;
    PORT
      LAYER Metal2 ;
        RECT 5.2650 363.9400 5.3350 364.2300 ;
    END
  END clk_2core__L15_N185
  PIN clk_2core__L15_N186
    DIRECTION INPUT ;
    USE SIGNAL ;
    PORT
      LAYER Metal4 ;
        RECT 5.4650 363.9400 5.5350 364.2300 ;
    END
  END clk_2core__L15_N186
  PIN clk_2core__L15_N188
    DIRECTION INPUT ;
    USE SIGNAL ;
    PORT
      LAYER Metal2 ;
        RECT 26.6650 363.9400 26.7350 364.2300 ;
    END
  END clk_2core__L15_N188
  PIN clk_2core__L15_N189
    DIRECTION INPUT ;
    USE SIGNAL ;
    PORT
      LAYER Metal2 ;
        RECT 258.8650 363.9400 258.9350 364.2300 ;
    END
  END clk_2core__L15_N189
  PIN VSS
    DIRECTION INOUT ;
    USE GROUND ;
    PORT
      LAYER Metal8 ;
        RECT 2511.2000 364.1600 2521.2000 364.2300 ;
    END
    PORT
      LAYER Metal8 ;
        RECT 1671.2000 0.0000 1681.2000 0.0700 ;
    END
    PORT
      LAYER Metal8 ;
        RECT 1671.2000 364.1600 1681.2000 364.2300 ;
    END
    PORT
      LAYER Metal9 ;
        RECT 3361.1300 210.0000 3361.2000 220.0000 ;
    END
    PORT
      LAYER Metal9 ;
        RECT 3361.1300 90.0000 3361.2000 100.0000 ;
    END
    PORT
      LAYER Metal8 ;
        RECT 3231.2000 364.1600 3241.2000 364.2300 ;
    END
    PORT
      LAYER Metal8 ;
        RECT 3111.2000 364.1600 3121.2000 364.2300 ;
    END
    PORT
      LAYER Metal8 ;
        RECT 2991.2000 364.1600 3001.2000 364.2300 ;
    END
    PORT
      LAYER Metal8 ;
        RECT 3231.2000 0.0000 3241.2000 0.0700 ;
    END
    PORT
      LAYER Metal8 ;
        RECT 3111.2000 0.0000 3121.2000 0.0700 ;
    END
    PORT
      LAYER Metal8 ;
        RECT 2991.2000 0.0000 3001.2000 0.0700 ;
    END
    PORT
      LAYER Metal8 ;
        RECT 2871.2000 364.1600 2881.2000 364.2300 ;
    END
    PORT
      LAYER Metal8 ;
        RECT 2751.2000 364.1600 2761.2000 364.2300 ;
    END
    PORT
      LAYER Metal8 ;
        RECT 2631.2000 364.1600 2641.2000 364.2300 ;
    END
    PORT
      LAYER Metal8 ;
        RECT 2871.2000 0.0000 2881.2000 0.0700 ;
    END
    PORT
      LAYER Metal8 ;
        RECT 2751.2000 0.0000 2761.2000 0.0700 ;
    END
    PORT
      LAYER Metal8 ;
        RECT 2631.2000 0.0000 2641.2000 0.0700 ;
    END
    PORT
      LAYER Metal8 ;
        RECT 2391.2000 0.0000 2401.2000 0.0700 ;
    END
    PORT
      LAYER Metal8 ;
        RECT 2391.2000 364.1600 2401.2000 364.2300 ;
    END
    PORT
      LAYER Metal8 ;
        RECT 2271.2000 0.0000 2281.2000 0.0700 ;
    END
    PORT
      LAYER Metal8 ;
        RECT 2271.2000 364.1600 2281.2000 364.2300 ;
    END
    PORT
      LAYER Metal8 ;
        RECT 2511.2000 0.0000 2521.2000 0.0700 ;
    END
    PORT
      LAYER Metal8 ;
        RECT 2151.2000 0.0000 2161.2000 0.0700 ;
    END
    PORT
      LAYER Metal8 ;
        RECT 2151.2000 364.1600 2161.2000 364.2300 ;
    END
    PORT
      LAYER Metal8 ;
        RECT 2031.2000 0.0000 2041.2000 0.0700 ;
    END
    PORT
      LAYER Metal8 ;
        RECT 2031.2000 364.1600 2041.2000 364.2300 ;
    END
    PORT
      LAYER Metal8 ;
        RECT 1911.2000 0.0000 1921.2000 0.0700 ;
    END
    PORT
      LAYER Metal8 ;
        RECT 1911.2000 364.1600 1921.2000 364.2300 ;
    END
    PORT
      LAYER Metal8 ;
        RECT 1791.2000 0.0000 1801.2000 0.0700 ;
    END
    PORT
      LAYER Metal8 ;
        RECT 1791.2000 364.1600 1801.2000 364.2300 ;
    END
    PORT
      LAYER Metal8 ;
        RECT 1551.2000 0.0000 1561.2000 0.0700 ;
    END
    PORT
      LAYER Metal8 ;
        RECT 1551.2000 364.1600 1561.2000 364.2300 ;
    END
    PORT
      LAYER Metal8 ;
        RECT 1431.2000 0.0000 1441.2000 0.0700 ;
    END
    PORT
      LAYER Metal8 ;
        RECT 1431.2000 364.1600 1441.2000 364.2300 ;
    END
    PORT
      LAYER Metal8 ;
        RECT 1311.2000 0.0000 1321.2000 0.0700 ;
    END
    PORT
      LAYER Metal8 ;
        RECT 1311.2000 364.1600 1321.2000 364.2300 ;
    END
    PORT
      LAYER Metal8 ;
        RECT 1191.2000 0.0000 1201.2000 0.0700 ;
    END
    PORT
      LAYER Metal8 ;
        RECT 1191.2000 364.1600 1201.2000 364.2300 ;
    END
    PORT
      LAYER Metal8 ;
        RECT 1071.2000 0.0000 1081.2000 0.0700 ;
    END
    PORT
      LAYER Metal8 ;
        RECT 1071.2000 364.1600 1081.2000 364.2300 ;
    END
    PORT
      LAYER Metal8 ;
        RECT 831.2000 0.0000 841.2000 0.0700 ;
    END
    PORT
      LAYER Metal8 ;
        RECT 831.2000 364.1600 841.2000 364.2300 ;
    END
    PORT
      LAYER Metal8 ;
        RECT 951.2000 0.0000 961.2000 0.0700 ;
    END
    PORT
      LAYER Metal8 ;
        RECT 951.2000 364.1600 961.2000 364.2300 ;
    END
    PORT
      LAYER Metal8 ;
        RECT 711.2000 0.0000 721.2000 0.0700 ;
    END
    PORT
      LAYER Metal8 ;
        RECT 711.2000 364.1600 721.2000 364.2300 ;
    END
    PORT
      LAYER Metal9 ;
        RECT 3361.1300 330.0000 3361.2000 340.0000 ;
    END
    PORT
      LAYER Metal9 ;
        RECT 0.0000 330.0000 0.0700 340.0000 ;
    END
    PORT
      LAYER Metal9 ;
        RECT 0.0000 210.0000 0.0700 220.0000 ;
    END
    PORT
      LAYER Metal9 ;
        RECT 0.0000 90.0000 0.0700 100.0000 ;
    END
    PORT
      LAYER Metal8 ;
        RECT 591.2000 0.0000 601.2000 0.0700 ;
    END
    PORT
      LAYER Metal8 ;
        RECT 591.2000 364.1600 601.2000 364.2300 ;
    END
    PORT
      LAYER Metal8 ;
        RECT 471.2000 0.0000 481.2000 0.0700 ;
    END
    PORT
      LAYER Metal8 ;
        RECT 471.2000 364.1600 481.2000 364.2300 ;
    END
    PORT
      LAYER Metal8 ;
        RECT 351.2000 0.0000 361.2000 0.0700 ;
    END
    PORT
      LAYER Metal8 ;
        RECT 351.2000 364.1600 361.2000 364.2300 ;
    END
    PORT
      LAYER Metal8 ;
        RECT 231.2000 0.0000 241.2000 0.0700 ;
    END
    PORT
      LAYER Metal8 ;
        RECT 231.2000 364.1600 241.2000 364.2300 ;
    END
    PORT
      LAYER Metal8 ;
        RECT 111.2000 0.0000 121.2000 0.0700 ;
    END
    PORT
      LAYER Metal8 ;
        RECT 111.2000 364.1600 121.2000 364.2300 ;
    END
    PORT
      LAYER Metal7 ;
        RECT -8.8000 0.0000 1.2000 364.2300 ;
    END
  END VSS
  PIN VDD
    DIRECTION INOUT ;
    USE POWER ;
    PORT
      LAYER Metal8 ;
        RECT 2491.2000 364.1600 2501.2000 364.2300 ;
    END
    PORT
      LAYER Metal8 ;
        RECT 1651.2000 0.0000 1661.2000 0.0700 ;
    END
    PORT
      LAYER Metal8 ;
        RECT 1651.2000 364.1600 1661.2000 364.2300 ;
    END
    PORT
      LAYER Metal8 ;
        RECT 811.2000 0.0000 821.2000 0.0700 ;
    END
    PORT
      LAYER Metal8 ;
        RECT 811.2000 364.1600 821.2000 364.2300 ;
    END
    PORT
      LAYER Metal9 ;
        RECT 3361.1300 310.0000 3361.2000 320.0000 ;
    END
    PORT
      LAYER Metal9 ;
        RECT 3361.1300 190.0000 3361.2000 200.0000 ;
    END
    PORT
      LAYER Metal9 ;
        RECT 3361.1300 70.0000 3361.2000 80.0000 ;
    END
    PORT
      LAYER Metal8 ;
        RECT 3211.2000 364.1600 3221.2000 364.2300 ;
    END
    PORT
      LAYER Metal8 ;
        RECT 3091.2000 364.1600 3101.2000 364.2300 ;
    END
    PORT
      LAYER Metal8 ;
        RECT 2971.2000 364.1600 2981.2000 364.2300 ;
    END
    PORT
      LAYER Metal8 ;
        RECT 3211.2000 0.0000 3221.2000 0.0700 ;
    END
    PORT
      LAYER Metal8 ;
        RECT 3091.2000 0.0000 3101.2000 0.0700 ;
    END
    PORT
      LAYER Metal8 ;
        RECT 2971.2000 0.0000 2981.2000 0.0700 ;
    END
    PORT
      LAYER Metal8 ;
        RECT 2851.2000 364.1600 2861.2000 364.2300 ;
    END
    PORT
      LAYER Metal8 ;
        RECT 2731.2000 364.1600 2741.2000 364.2300 ;
    END
    PORT
      LAYER Metal8 ;
        RECT 2611.2000 364.1600 2621.2000 364.2300 ;
    END
    PORT
      LAYER Metal8 ;
        RECT 2851.2000 0.0000 2861.2000 0.0700 ;
    END
    PORT
      LAYER Metal8 ;
        RECT 2731.2000 0.0000 2741.2000 0.0700 ;
    END
    PORT
      LAYER Metal8 ;
        RECT 2611.2000 0.0000 2621.2000 0.0700 ;
    END
    PORT
      LAYER Metal8 ;
        RECT 2371.2000 0.0000 2381.2000 0.0700 ;
    END
    PORT
      LAYER Metal8 ;
        RECT 2371.2000 364.1600 2381.2000 364.2300 ;
    END
    PORT
      LAYER Metal8 ;
        RECT 2251.2000 0.0000 2261.2000 0.0700 ;
    END
    PORT
      LAYER Metal8 ;
        RECT 2251.2000 364.1600 2261.2000 364.2300 ;
    END
    PORT
      LAYER Metal8 ;
        RECT 2491.2000 0.0000 2501.2000 0.0700 ;
    END
    PORT
      LAYER Metal8 ;
        RECT 2131.2000 0.0000 2141.2000 0.0700 ;
    END
    PORT
      LAYER Metal8 ;
        RECT 2131.2000 364.1600 2141.2000 364.2300 ;
    END
    PORT
      LAYER Metal8 ;
        RECT 2011.2000 0.0000 2021.2000 0.0700 ;
    END
    PORT
      LAYER Metal8 ;
        RECT 2011.2000 364.1600 2021.2000 364.2300 ;
    END
    PORT
      LAYER Metal8 ;
        RECT 1891.2000 0.0000 1901.2000 0.0700 ;
    END
    PORT
      LAYER Metal8 ;
        RECT 1891.2000 364.1600 1901.2000 364.2300 ;
    END
    PORT
      LAYER Metal8 ;
        RECT 1771.2000 0.0000 1781.2000 0.0700 ;
    END
    PORT
      LAYER Metal8 ;
        RECT 1771.2000 364.1600 1781.2000 364.2300 ;
    END
    PORT
      LAYER Metal8 ;
        RECT 1531.2000 0.0000 1541.2000 0.0700 ;
    END
    PORT
      LAYER Metal8 ;
        RECT 1531.2000 364.1600 1541.2000 364.2300 ;
    END
    PORT
      LAYER Metal8 ;
        RECT 1411.2000 0.0000 1421.2000 0.0700 ;
    END
    PORT
      LAYER Metal8 ;
        RECT 1411.2000 364.1600 1421.2000 364.2300 ;
    END
    PORT
      LAYER Metal8 ;
        RECT 1291.2000 0.0000 1301.2000 0.0700 ;
    END
    PORT
      LAYER Metal8 ;
        RECT 1291.2000 364.1600 1301.2000 364.2300 ;
    END
    PORT
      LAYER Metal8 ;
        RECT 1171.2000 0.0000 1181.2000 0.0700 ;
    END
    PORT
      LAYER Metal8 ;
        RECT 1171.2000 364.1600 1181.2000 364.2300 ;
    END
    PORT
      LAYER Metal8 ;
        RECT 1051.2000 0.0000 1061.2000 0.0700 ;
    END
    PORT
      LAYER Metal8 ;
        RECT 1051.2000 364.1600 1061.2000 364.2300 ;
    END
    PORT
      LAYER Metal8 ;
        RECT 931.2000 0.0000 941.2000 0.0700 ;
    END
    PORT
      LAYER Metal8 ;
        RECT 931.2000 364.1600 941.2000 364.2300 ;
    END
    PORT
      LAYER Metal8 ;
        RECT 691.2000 0.0000 701.2000 0.0700 ;
    END
    PORT
      LAYER Metal8 ;
        RECT 691.2000 364.1600 701.2000 364.2300 ;
    END
    PORT
      LAYER Metal9 ;
        RECT 0.0000 310.0000 0.0700 320.0000 ;
    END
    PORT
      LAYER Metal9 ;
        RECT 0.0000 190.0000 0.0700 200.0000 ;
    END
    PORT
      LAYER Metal9 ;
        RECT 0.0000 70.0000 0.0700 80.0000 ;
    END
    PORT
      LAYER Metal8 ;
        RECT 571.2000 0.0000 581.2000 0.0700 ;
    END
    PORT
      LAYER Metal8 ;
        RECT 571.2000 364.1600 581.2000 364.2300 ;
    END
    PORT
      LAYER Metal8 ;
        RECT 451.2000 0.0000 461.2000 0.0700 ;
    END
    PORT
      LAYER Metal8 ;
        RECT 451.2000 364.1600 461.2000 364.2300 ;
    END
    PORT
      LAYER Metal8 ;
        RECT 331.2000 0.0000 341.2000 0.0700 ;
    END
    PORT
      LAYER Metal8 ;
        RECT 331.2000 364.1600 341.2000 364.2300 ;
    END
    PORT
      LAYER Metal8 ;
        RECT 211.2000 0.0000 221.2000 0.0700 ;
    END
    PORT
      LAYER Metal8 ;
        RECT 211.2000 364.1600 221.2000 364.2300 ;
    END
    PORT
      LAYER Metal8 ;
        RECT 91.2000 0.0000 101.2000 0.0700 ;
    END
    PORT
      LAYER Metal8 ;
        RECT 91.2000 364.1600 101.2000 364.2300 ;
    END
  END VDD
  OBS
    LAYER Metal9 ;
      RECT 0.0000 0.0000 3361.2000 88.7500 ;
      RECT 2.4500 88.7500 3361.2000 101.2500 ;
      RECT 0.0000 101.2500 3361.2000 208.7500 ;
      RECT 2.4500 208.7500 3361.2000 221.2500 ;
      RECT 0.0000 221.2500 3361.2000 328.7500 ;
      RECT 2.4500 328.7500 3361.2000 341.2500 ;
      RECT 0.0000 341.2500 3361.2000 364.2300 ;
    LAYER Metal8 ;
      RECT 0.0000 0.0000 3361.2000 88.7500 ;
      RECT 2.4500 88.7500 3361.2000 101.2500 ;
      RECT 0.0000 101.2500 3361.2000 208.7500 ;
      RECT 2.4500 208.7500 3361.2000 221.2500 ;
      RECT 0.0000 221.2500 3361.2000 328.7500 ;
      RECT 2.4500 328.7500 3361.2000 341.2500 ;
      RECT 0.0000 341.2500 3361.2000 364.2300 ;
    LAYER Metal7 ;
      RECT 2.4500 0.0000 3361.2000 88.7500 ;
      RECT 2.4500 88.7500 3361.2000 101.2500 ;
      RECT 2.4500 101.2500 3361.2000 208.7500 ;
      RECT 2.4500 208.7500 3361.2000 221.2500 ;
      RECT 2.4500 221.2500 3361.2000 328.7500 ;
      RECT 2.4500 328.7500 3361.2000 341.2500 ;
      RECT 2.4500 341.2500 3361.2000 364.2300 ;
    LAYER Metal6 ;
      RECT 0.0000 0.0000 3361.2000 364.2300 ;
    LAYER Metal5 ;
      RECT 0.0000 0.0000 3361.2000 364.2300 ;
    LAYER Metal4 ;
      RECT 0.0000 0.0000 3361.2000 364.2300 ;
    LAYER Metal3 ;
      RECT 0.0000 0.0000 3361.2000 364.2300 ;
    LAYER Metal2 ;
      RECT 0.0000 0.0000 3361.2000 364.2300 ;
    LAYER Metal1 ;
      RECT 0.0000 0.0000 3361.2000 364.2300 ;
  END
END leon

END LIBRARY
